VERSION 5.7 ;
  NOWIREEXTENSIONATPIN ON ;
  DIVIDERCHAR "/" ;
  BUSBITCHARS "[]" ;
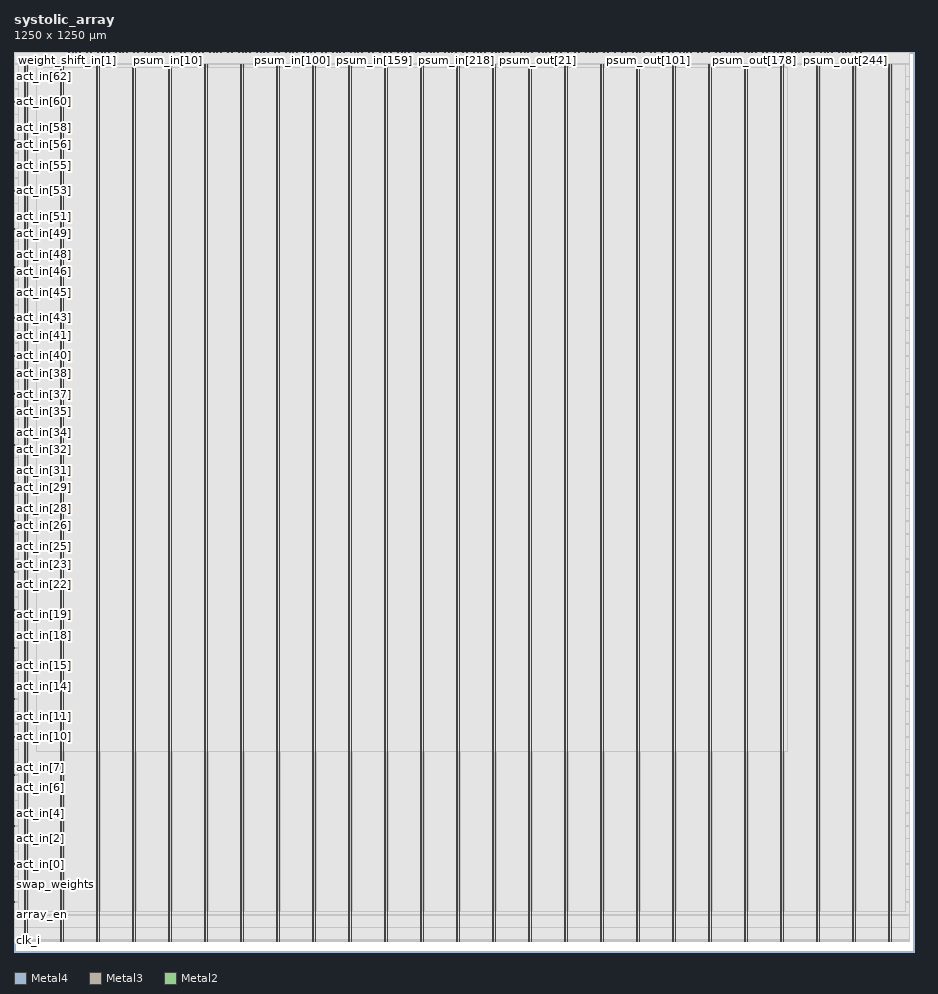
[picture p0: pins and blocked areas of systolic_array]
MACRO systolic_array
  CLASS BLOCK ;
  FOREIGN systolic_array ;
  ORIGIN 0.000 0.000 ;
  SIZE 1250.000 BY 1250.000 ;
  PIN VDD
    DIRECTION INOUT ;
    USE POWER ;
    PORT
      LAYER Metal4 ;
        RECT 15.260 14.900 16.260 1232.500 ;
    END
    PORT
      LAYER Metal4 ;
        RECT 65.260 14.900 66.260 1232.500 ;
    END
    PORT
      LAYER Metal4 ;
        RECT 115.260 14.900 116.260 1232.500 ;
    END
    PORT
      LAYER Metal4 ;
        RECT 165.260 14.900 166.260 1232.500 ;
    END
    PORT
      LAYER Metal4 ;
        RECT 215.260 14.900 216.260 1232.500 ;
    END
    PORT
      LAYER Metal4 ;
        RECT 265.260 14.900 266.260 1232.500 ;
    END
    PORT
      LAYER Metal4 ;
        RECT 315.260 14.900 316.260 1232.500 ;
    END
    PORT
      LAYER Metal4 ;
        RECT 365.260 14.900 366.260 1232.500 ;
    END
    PORT
      LAYER Metal4 ;
        RECT 415.260 14.900 416.260 1232.500 ;
    END
    PORT
      LAYER Metal4 ;
        RECT 465.260 14.900 466.260 1232.500 ;
    END
    PORT
      LAYER Metal4 ;
        RECT 515.260 14.900 516.260 1232.500 ;
    END
    PORT
      LAYER Metal4 ;
        RECT 565.260 14.900 566.260 1232.500 ;
    END
    PORT
      LAYER Metal4 ;
        RECT 615.260 14.900 616.260 1232.500 ;
    END
    PORT
      LAYER Metal4 ;
        RECT 665.260 14.900 666.260 1232.500 ;
    END
    PORT
      LAYER Metal4 ;
        RECT 715.260 14.900 716.260 1232.500 ;
    END
    PORT
      LAYER Metal4 ;
        RECT 765.260 14.900 766.260 1232.500 ;
    END
    PORT
      LAYER Metal4 ;
        RECT 815.260 14.900 816.260 1232.500 ;
    END
    PORT
      LAYER Metal4 ;
        RECT 865.260 14.900 866.260 1232.500 ;
    END
    PORT
      LAYER Metal4 ;
        RECT 915.260 14.900 916.260 1232.500 ;
    END
    PORT
      LAYER Metal4 ;
        RECT 965.260 14.900 966.260 1232.500 ;
    END
    PORT
      LAYER Metal4 ;
        RECT 1015.260 14.900 1016.260 1232.500 ;
    END
    PORT
      LAYER Metal4 ;
        RECT 1065.260 14.900 1066.260 1232.500 ;
    END
    PORT
      LAYER Metal4 ;
        RECT 1115.260 14.900 1116.260 1232.500 ;
    END
    PORT
      LAYER Metal4 ;
        RECT 1165.260 14.900 1166.260 1232.500 ;
    END
    PORT
      LAYER Metal4 ;
        RECT 1215.260 14.900 1216.260 1232.500 ;
    END
  END VDD
  PIN VSS
    DIRECTION INOUT ;
    USE GROUND ;
    PORT
      LAYER Metal4 ;
        RECT 18.260 14.900 19.260 1232.500 ;
    END
    PORT
      LAYER Metal4 ;
        RECT 68.260 14.900 69.260 1232.500 ;
    END
    PORT
      LAYER Metal4 ;
        RECT 118.260 14.900 119.260 1232.500 ;
    END
    PORT
      LAYER Metal4 ;
        RECT 168.260 14.900 169.260 1232.500 ;
    END
    PORT
      LAYER Metal4 ;
        RECT 218.260 14.900 219.260 1232.500 ;
    END
    PORT
      LAYER Metal4 ;
        RECT 268.260 14.900 269.260 1232.500 ;
    END
    PORT
      LAYER Metal4 ;
        RECT 318.260 14.900 319.260 1232.500 ;
    END
    PORT
      LAYER Metal4 ;
        RECT 368.260 14.900 369.260 1232.500 ;
    END
    PORT
      LAYER Metal4 ;
        RECT 418.260 14.900 419.260 1232.500 ;
    END
    PORT
      LAYER Metal4 ;
        RECT 468.260 14.900 469.260 1232.500 ;
    END
    PORT
      LAYER Metal4 ;
        RECT 518.260 14.900 519.260 1232.500 ;
    END
    PORT
      LAYER Metal4 ;
        RECT 568.260 14.900 569.260 1232.500 ;
    END
    PORT
      LAYER Metal4 ;
        RECT 618.260 14.900 619.260 1232.500 ;
    END
    PORT
      LAYER Metal4 ;
        RECT 668.260 14.900 669.260 1232.500 ;
    END
    PORT
      LAYER Metal4 ;
        RECT 718.260 14.900 719.260 1232.500 ;
    END
    PORT
      LAYER Metal4 ;
        RECT 768.260 14.900 769.260 1232.500 ;
    END
    PORT
      LAYER Metal4 ;
        RECT 818.260 14.900 819.260 1232.500 ;
    END
    PORT
      LAYER Metal4 ;
        RECT 868.260 14.900 869.260 1232.500 ;
    END
    PORT
      LAYER Metal4 ;
        RECT 918.260 14.900 919.260 1232.500 ;
    END
    PORT
      LAYER Metal4 ;
        RECT 968.260 14.900 969.260 1232.500 ;
    END
    PORT
      LAYER Metal4 ;
        RECT 1018.260 14.900 1019.260 1232.500 ;
    END
    PORT
      LAYER Metal4 ;
        RECT 1068.260 14.900 1069.260 1232.500 ;
    END
    PORT
      LAYER Metal4 ;
        RECT 1118.260 14.900 1119.260 1232.500 ;
    END
    PORT
      LAYER Metal4 ;
        RECT 1168.260 14.900 1169.260 1232.500 ;
    END
    PORT
      LAYER Metal4 ;
        RECT 1218.260 14.900 1219.260 1232.500 ;
    END
  END VSS
  PIN act_in[0]
    DIRECTION INPUT ;
    USE SIGNAL ;
    ANTENNAGATEAREA 0.180700 ;
    PORT
      LAYER Metal3 ;
        RECT 0.000 122.020 0.400 122.420 ;
    END
  END act_in[0]
  PIN act_in[10]
    DIRECTION INPUT ;
    USE SIGNAL ;
    ANTENNAGATEAREA 0.180700 ;
    PORT
      LAYER Metal3 ;
        RECT 0.000 298.420 0.400 298.820 ;
    END
  END act_in[10]
  PIN act_in[11]
    DIRECTION INPUT ;
    USE SIGNAL ;
    ANTENNAGATEAREA 0.180700 ;
    PORT
      LAYER Metal3 ;
        RECT 0.000 316.060 0.400 316.460 ;
    END
  END act_in[11]
  PIN act_in[12]
    DIRECTION INPUT ;
    USE SIGNAL ;
    ANTENNAGATEAREA 0.180700 ;
    PORT
      LAYER Metal3 ;
        RECT 0.000 333.700 0.400 334.100 ;
    END
  END act_in[12]
  PIN act_in[13]
    DIRECTION INPUT ;
    USE SIGNAL ;
    ANTENNAGATEAREA 0.180700 ;
    PORT
      LAYER Metal3 ;
        RECT 0.000 351.340 0.400 351.740 ;
    END
  END act_in[13]
  PIN act_in[14]
    DIRECTION INPUT ;
    USE SIGNAL ;
    ANTENNAGATEAREA 0.180700 ;
    PORT
      LAYER Metal3 ;
        RECT 0.000 368.980 0.400 369.380 ;
    END
  END act_in[14]
  PIN act_in[15]
    DIRECTION INPUT ;
    USE SIGNAL ;
    ANTENNAGATEAREA 0.180700 ;
    PORT
      LAYER Metal3 ;
        RECT 0.000 386.620 0.400 387.020 ;
    END
  END act_in[15]
  PIN act_in[16]
    DIRECTION INPUT ;
    USE SIGNAL ;
    ANTENNAGATEAREA 0.180700 ;
    PORT
      LAYER Metal3 ;
        RECT 0.000 404.260 0.400 404.660 ;
    END
  END act_in[16]
  PIN act_in[17]
    DIRECTION INPUT ;
    USE SIGNAL ;
    ANTENNAGATEAREA 0.180700 ;
    PORT
      LAYER Metal3 ;
        RECT 0.000 421.900 0.400 422.300 ;
    END
  END act_in[17]
  PIN act_in[18]
    DIRECTION INPUT ;
    USE SIGNAL ;
    ANTENNAGATEAREA 0.180700 ;
    PORT
      LAYER Metal3 ;
        RECT 0.000 439.540 0.400 439.940 ;
    END
  END act_in[18]
  PIN act_in[19]
    DIRECTION INPUT ;
    USE SIGNAL ;
    ANTENNAGATEAREA 0.180700 ;
    PORT
      LAYER Metal3 ;
        RECT 0.000 457.180 0.400 457.580 ;
    END
  END act_in[19]
  PIN act_in[1]
    DIRECTION INPUT ;
    USE SIGNAL ;
    ANTENNAGATEAREA 0.180700 ;
    PORT
      LAYER Metal3 ;
        RECT 0.000 139.660 0.400 140.060 ;
    END
  END act_in[1]
  PIN act_in[20]
    DIRECTION INPUT ;
    USE SIGNAL ;
    ANTENNAGATEAREA 0.180700 ;
    PORT
      LAYER Metal3 ;
        RECT 0.000 474.820 0.400 475.220 ;
    END
  END act_in[20]
  PIN act_in[21]
    DIRECTION INPUT ;
    USE SIGNAL ;
    ANTENNAGATEAREA 0.180700 ;
    PORT
      LAYER Metal3 ;
        RECT 0.000 492.460 0.400 492.860 ;
    END
  END act_in[21]
  PIN act_in[22]
    DIRECTION INPUT ;
    USE SIGNAL ;
    ANTENNAGATEAREA 0.180700 ;
    PORT
      LAYER Metal3 ;
        RECT 0.000 510.100 0.400 510.500 ;
    END
  END act_in[22]
  PIN act_in[23]
    DIRECTION INPUT ;
    USE SIGNAL ;
    ANTENNAGATEAREA 0.180700 ;
    PORT
      LAYER Metal3 ;
        RECT 0.000 527.740 0.400 528.140 ;
    END
  END act_in[23]
  PIN act_in[24]
    DIRECTION INPUT ;
    USE SIGNAL ;
    ANTENNAGATEAREA 0.180700 ;
    PORT
      LAYER Metal3 ;
        RECT 0.000 545.380 0.400 545.780 ;
    END
  END act_in[24]
  PIN act_in[25]
    DIRECTION INPUT ;
    USE SIGNAL ;
    ANTENNAGATEAREA 0.180700 ;
    PORT
      LAYER Metal3 ;
        RECT 0.000 563.020 0.400 563.420 ;
    END
  END act_in[25]
  PIN act_in[26]
    DIRECTION INPUT ;
    USE SIGNAL ;
    ANTENNAGATEAREA 0.180700 ;
    PORT
      LAYER Metal3 ;
        RECT 0.000 580.660 0.400 581.060 ;
    END
  END act_in[26]
  PIN act_in[27]
    DIRECTION INPUT ;
    USE SIGNAL ;
    ANTENNAGATEAREA 0.180700 ;
    PORT
      LAYER Metal3 ;
        RECT 0.000 598.300 0.400 598.700 ;
    END
  END act_in[27]
  PIN act_in[28]
    DIRECTION INPUT ;
    USE SIGNAL ;
    ANTENNAGATEAREA 0.180700 ;
    PORT
      LAYER Metal3 ;
        RECT 0.000 615.940 0.400 616.340 ;
    END
  END act_in[28]
  PIN act_in[29]
    DIRECTION INPUT ;
    USE SIGNAL ;
    ANTENNAGATEAREA 0.180700 ;
    PORT
      LAYER Metal3 ;
        RECT 0.000 633.580 0.400 633.980 ;
    END
  END act_in[29]
  PIN act_in[2]
    DIRECTION INPUT ;
    USE SIGNAL ;
    ANTENNAGATEAREA 0.180700 ;
    PORT
      LAYER Metal3 ;
        RECT 0.000 157.300 0.400 157.700 ;
    END
  END act_in[2]
  PIN act_in[30]
    DIRECTION INPUT ;
    USE SIGNAL ;
    ANTENNAGATEAREA 0.180700 ;
    PORT
      LAYER Metal3 ;
        RECT 0.000 651.220 0.400 651.620 ;
    END
  END act_in[30]
  PIN act_in[31]
    DIRECTION INPUT ;
    USE SIGNAL ;
    ANTENNAGATEAREA 0.180700 ;
    PORT
      LAYER Metal3 ;
        RECT 0.000 668.860 0.400 669.260 ;
    END
  END act_in[31]
  PIN act_in[32]
    DIRECTION INPUT ;
    USE SIGNAL ;
    ANTENNAGATEAREA 0.180700 ;
    PORT
      LAYER Metal3 ;
        RECT 0.000 686.500 0.400 686.900 ;
    END
  END act_in[32]
  PIN act_in[33]
    DIRECTION INPUT ;
    USE SIGNAL ;
    ANTENNAGATEAREA 0.180700 ;
    PORT
      LAYER Metal3 ;
        RECT 0.000 704.140 0.400 704.540 ;
    END
  END act_in[33]
  PIN act_in[34]
    DIRECTION INPUT ;
    USE SIGNAL ;
    ANTENNAGATEAREA 0.180700 ;
    PORT
      LAYER Metal3 ;
        RECT 0.000 721.780 0.400 722.180 ;
    END
  END act_in[34]
  PIN act_in[35]
    DIRECTION INPUT ;
    USE SIGNAL ;
    ANTENNAGATEAREA 0.180700 ;
    PORT
      LAYER Metal3 ;
        RECT 0.000 739.420 0.400 739.820 ;
    END
  END act_in[35]
  PIN act_in[36]
    DIRECTION INPUT ;
    USE SIGNAL ;
    ANTENNAGATEAREA 0.180700 ;
    PORT
      LAYER Metal3 ;
        RECT 0.000 757.060 0.400 757.460 ;
    END
  END act_in[36]
  PIN act_in[37]
    DIRECTION INPUT ;
    USE SIGNAL ;
    ANTENNAGATEAREA 0.180700 ;
    PORT
      LAYER Metal3 ;
        RECT 0.000 774.700 0.400 775.100 ;
    END
  END act_in[37]
  PIN act_in[38]
    DIRECTION INPUT ;
    USE SIGNAL ;
    ANTENNAGATEAREA 0.180700 ;
    PORT
      LAYER Metal3 ;
        RECT 0.000 792.340 0.400 792.740 ;
    END
  END act_in[38]
  PIN act_in[39]
    DIRECTION INPUT ;
    USE SIGNAL ;
    ANTENNAGATEAREA 0.180700 ;
    PORT
      LAYER Metal3 ;
        RECT 0.000 809.980 0.400 810.380 ;
    END
  END act_in[39]
  PIN act_in[3]
    DIRECTION INPUT ;
    USE SIGNAL ;
    ANTENNAGATEAREA 0.180700 ;
    PORT
      LAYER Metal3 ;
        RECT 0.000 174.940 0.400 175.340 ;
    END
  END act_in[3]
  PIN act_in[40]
    DIRECTION INPUT ;
    USE SIGNAL ;
    ANTENNAGATEAREA 0.180700 ;
    PORT
      LAYER Metal3 ;
        RECT 0.000 827.620 0.400 828.020 ;
    END
  END act_in[40]
  PIN act_in[41]
    DIRECTION INPUT ;
    USE SIGNAL ;
    ANTENNAGATEAREA 0.180700 ;
    PORT
      LAYER Metal3 ;
        RECT 0.000 845.260 0.400 845.660 ;
    END
  END act_in[41]
  PIN act_in[42]
    DIRECTION INPUT ;
    USE SIGNAL ;
    ANTENNAGATEAREA 0.180700 ;
    PORT
      LAYER Metal3 ;
        RECT 0.000 862.900 0.400 863.300 ;
    END
  END act_in[42]
  PIN act_in[43]
    DIRECTION INPUT ;
    USE SIGNAL ;
    ANTENNAGATEAREA 0.180700 ;
    PORT
      LAYER Metal3 ;
        RECT 0.000 880.540 0.400 880.940 ;
    END
  END act_in[43]
  PIN act_in[44]
    DIRECTION INPUT ;
    USE SIGNAL ;
    ANTENNAGATEAREA 0.180700 ;
    PORT
      LAYER Metal3 ;
        RECT 0.000 898.180 0.400 898.580 ;
    END
  END act_in[44]
  PIN act_in[45]
    DIRECTION INPUT ;
    USE SIGNAL ;
    ANTENNAGATEAREA 0.180700 ;
    PORT
      LAYER Metal3 ;
        RECT 0.000 915.820 0.400 916.220 ;
    END
  END act_in[45]
  PIN act_in[46]
    DIRECTION INPUT ;
    USE SIGNAL ;
    ANTENNAGATEAREA 0.180700 ;
    PORT
      LAYER Metal3 ;
        RECT 0.000 933.460 0.400 933.860 ;
    END
  END act_in[46]
  PIN act_in[47]
    DIRECTION INPUT ;
    USE SIGNAL ;
    ANTENNAGATEAREA 0.180700 ;
    PORT
      LAYER Metal3 ;
        RECT 0.000 951.100 0.400 951.500 ;
    END
  END act_in[47]
  PIN act_in[48]
    DIRECTION INPUT ;
    USE SIGNAL ;
    ANTENNAGATEAREA 0.180700 ;
    PORT
      LAYER Metal3 ;
        RECT 0.000 968.740 0.400 969.140 ;
    END
  END act_in[48]
  PIN act_in[49]
    DIRECTION INPUT ;
    USE SIGNAL ;
    ANTENNAGATEAREA 0.180700 ;
    PORT
      LAYER Metal3 ;
        RECT 0.000 986.380 0.400 986.780 ;
    END
  END act_in[49]
  PIN act_in[4]
    DIRECTION INPUT ;
    USE SIGNAL ;
    ANTENNAGATEAREA 0.180700 ;
    PORT
      LAYER Metal3 ;
        RECT 0.000 192.580 0.400 192.980 ;
    END
  END act_in[4]
  PIN act_in[50]
    DIRECTION INPUT ;
    USE SIGNAL ;
    ANTENNAGATEAREA 0.180700 ;
    PORT
      LAYER Metal3 ;
        RECT 0.000 1004.020 0.400 1004.420 ;
    END
  END act_in[50]
  PIN act_in[51]
    DIRECTION INPUT ;
    USE SIGNAL ;
    ANTENNAGATEAREA 0.180700 ;
    PORT
      LAYER Metal3 ;
        RECT 0.000 1021.660 0.400 1022.060 ;
    END
  END act_in[51]
  PIN act_in[52]
    DIRECTION INPUT ;
    USE SIGNAL ;
    ANTENNAGATEAREA 0.180700 ;
    PORT
      LAYER Metal3 ;
        RECT 0.000 1039.300 0.400 1039.700 ;
    END
  END act_in[52]
  PIN act_in[53]
    DIRECTION INPUT ;
    USE SIGNAL ;
    ANTENNAGATEAREA 0.180700 ;
    PORT
      LAYER Metal3 ;
        RECT 0.000 1056.940 0.400 1057.340 ;
    END
  END act_in[53]
  PIN act_in[54]
    DIRECTION INPUT ;
    USE SIGNAL ;
    ANTENNAGATEAREA 0.180700 ;
    PORT
      LAYER Metal3 ;
        RECT 0.000 1074.580 0.400 1074.980 ;
    END
  END act_in[54]
  PIN act_in[55]
    DIRECTION INPUT ;
    USE SIGNAL ;
    ANTENNAGATEAREA 0.180700 ;
    PORT
      LAYER Metal3 ;
        RECT 0.000 1092.220 0.400 1092.620 ;
    END
  END act_in[55]
  PIN act_in[56]
    DIRECTION INPUT ;
    USE SIGNAL ;
    ANTENNAGATEAREA 0.180700 ;
    PORT
      LAYER Metal3 ;
        RECT 0.000 1109.860 0.400 1110.260 ;
    END
  END act_in[56]
  PIN act_in[57]
    DIRECTION INPUT ;
    USE SIGNAL ;
    ANTENNAGATEAREA 0.180700 ;
    PORT
      LAYER Metal3 ;
        RECT 0.000 1127.500 0.400 1127.900 ;
    END
  END act_in[57]
  PIN act_in[58]
    DIRECTION INPUT ;
    USE SIGNAL ;
    ANTENNAGATEAREA 0.180700 ;
    PORT
      LAYER Metal3 ;
        RECT 0.000 1145.140 0.400 1145.540 ;
    END
  END act_in[58]
  PIN act_in[59]
    DIRECTION INPUT ;
    USE SIGNAL ;
    ANTENNAGATEAREA 0.180700 ;
    PORT
      LAYER Metal3 ;
        RECT 0.000 1162.780 0.400 1163.180 ;
    END
  END act_in[59]
  PIN act_in[5]
    DIRECTION INPUT ;
    USE SIGNAL ;
    ANTENNAGATEAREA 0.180700 ;
    PORT
      LAYER Metal3 ;
        RECT 0.000 210.220 0.400 210.620 ;
    END
  END act_in[5]
  PIN act_in[60]
    DIRECTION INPUT ;
    USE SIGNAL ;
    ANTENNAGATEAREA 0.180700 ;
    PORT
      LAYER Metal3 ;
        RECT 0.000 1180.420 0.400 1180.820 ;
    END
  END act_in[60]
  PIN act_in[61]
    DIRECTION INPUT ;
    USE SIGNAL ;
    ANTENNAGATEAREA 0.180700 ;
    PORT
      LAYER Metal3 ;
        RECT 0.000 1198.060 0.400 1198.460 ;
    END
  END act_in[61]
  PIN act_in[62]
    DIRECTION INPUT ;
    USE SIGNAL ;
    ANTENNAGATEAREA 0.180700 ;
    PORT
      LAYER Metal3 ;
        RECT 0.000 1215.700 0.400 1216.100 ;
    END
  END act_in[62]
  PIN act_in[63]
    DIRECTION INPUT ;
    USE SIGNAL ;
    ANTENNAGATEAREA 0.180700 ;
    PORT
      LAYER Metal3 ;
        RECT 0.000 1233.340 0.400 1233.740 ;
    END
  END act_in[63]
  PIN act_in[6]
    DIRECTION INPUT ;
    USE SIGNAL ;
    ANTENNAGATEAREA 0.180700 ;
    PORT
      LAYER Metal3 ;
        RECT 0.000 227.860 0.400 228.260 ;
    END
  END act_in[6]
  PIN act_in[7]
    DIRECTION INPUT ;
    USE SIGNAL ;
    ANTENNAGATEAREA 0.180700 ;
    PORT
      LAYER Metal3 ;
        RECT 0.000 245.500 0.400 245.900 ;
    END
  END act_in[7]
  PIN act_in[8]
    DIRECTION INPUT ;
    USE SIGNAL ;
    ANTENNAGATEAREA 0.180700 ;
    PORT
      LAYER Metal3 ;
        RECT 0.000 263.140 0.400 263.540 ;
    END
  END act_in[8]
  PIN act_in[9]
    DIRECTION INPUT ;
    USE SIGNAL ;
    ANTENNAGATEAREA 0.180700 ;
    PORT
      LAYER Metal3 ;
        RECT 0.000 280.780 0.400 281.180 ;
    END
  END act_in[9]
  PIN array_en
    DIRECTION INPUT ;
    USE SIGNAL ;
    ANTENNAGATEAREA 0.180700 ;
    PORT
      LAYER Metal3 ;
        RECT 0.000 51.460 0.400 51.860 ;
    END
  END array_en
  PIN clk_i
    DIRECTION INPUT ;
    USE SIGNAL ;
    ANTENNAGATEAREA 0.725400 ;
    PORT
      LAYER Metal3 ;
        RECT 0.000 16.180 0.400 16.580 ;
    END
  END clk_i
  PIN psum_in[0]
    DIRECTION INPUT ;
    USE SIGNAL ;
    ANTENNAGATEAREA 0.180700 ;
    PORT
      LAYER Metal2 ;
        RECT 195.160 1249.600 195.560 1250.000 ;
    END
  END psum_in[0]
  PIN psum_in[100]
    DIRECTION INPUT ;
    USE SIGNAL ;
    ANTENNAGATEAREA 0.180700 ;
    PORT
      LAYER Metal2 ;
        RECT 387.160 1249.600 387.560 1250.000 ;
    END
  END psum_in[100]
  PIN psum_in[101]
    DIRECTION INPUT ;
    USE SIGNAL ;
    ANTENNAGATEAREA 0.180700 ;
    PORT
      LAYER Metal2 ;
        RECT 389.080 1249.600 389.480 1250.000 ;
    END
  END psum_in[101]
  PIN psum_in[102]
    DIRECTION INPUT ;
    USE SIGNAL ;
    ANTENNAGATEAREA 0.180700 ;
    PORT
      LAYER Metal2 ;
        RECT 391.000 1249.600 391.400 1250.000 ;
    END
  END psum_in[102]
  PIN psum_in[103]
    DIRECTION INPUT ;
    USE SIGNAL ;
    ANTENNAGATEAREA 0.180700 ;
    PORT
      LAYER Metal2 ;
        RECT 392.920 1249.600 393.320 1250.000 ;
    END
  END psum_in[103]
  PIN psum_in[104]
    DIRECTION INPUT ;
    USE SIGNAL ;
    ANTENNAGATEAREA 0.180700 ;
    PORT
      LAYER Metal2 ;
        RECT 394.840 1249.600 395.240 1250.000 ;
    END
  END psum_in[104]
  PIN psum_in[105]
    DIRECTION INPUT ;
    USE SIGNAL ;
    ANTENNAGATEAREA 0.180700 ;
    PORT
      LAYER Metal2 ;
        RECT 396.760 1249.600 397.160 1250.000 ;
    END
  END psum_in[105]
  PIN psum_in[106]
    DIRECTION INPUT ;
    USE SIGNAL ;
    ANTENNAGATEAREA 0.180700 ;
    PORT
      LAYER Metal2 ;
        RECT 398.680 1249.600 399.080 1250.000 ;
    END
  END psum_in[106]
  PIN psum_in[107]
    DIRECTION INPUT ;
    USE SIGNAL ;
    ANTENNAGATEAREA 0.180700 ;
    PORT
      LAYER Metal2 ;
        RECT 400.600 1249.600 401.000 1250.000 ;
    END
  END psum_in[107]
  PIN psum_in[108]
    DIRECTION INPUT ;
    USE SIGNAL ;
    ANTENNAGATEAREA 0.180700 ;
    PORT
      LAYER Metal2 ;
        RECT 402.520 1249.600 402.920 1250.000 ;
    END
  END psum_in[108]
  PIN psum_in[109]
    DIRECTION INPUT ;
    USE SIGNAL ;
    ANTENNAGATEAREA 0.180700 ;
    PORT
      LAYER Metal2 ;
        RECT 404.440 1249.600 404.840 1250.000 ;
    END
  END psum_in[109]
  PIN psum_in[10]
    DIRECTION INPUT ;
    USE SIGNAL ;
    ANTENNAGATEAREA 0.180700 ;
    PORT
      LAYER Metal2 ;
        RECT 214.360 1249.600 214.760 1250.000 ;
    END
  END psum_in[10]
  PIN psum_in[110]
    DIRECTION INPUT ;
    USE SIGNAL ;
    ANTENNAGATEAREA 0.180700 ;
    PORT
      LAYER Metal2 ;
        RECT 406.360 1249.600 406.760 1250.000 ;
    END
  END psum_in[110]
  PIN psum_in[111]
    DIRECTION INPUT ;
    USE SIGNAL ;
    ANTENNAGATEAREA 0.180700 ;
    PORT
      LAYER Metal2 ;
        RECT 408.280 1249.600 408.680 1250.000 ;
    END
  END psum_in[111]
  PIN psum_in[112]
    DIRECTION INPUT ;
    USE SIGNAL ;
    ANTENNAGATEAREA 0.180700 ;
    PORT
      LAYER Metal2 ;
        RECT 410.200 1249.600 410.600 1250.000 ;
    END
  END psum_in[112]
  PIN psum_in[113]
    DIRECTION INPUT ;
    USE SIGNAL ;
    ANTENNAGATEAREA 0.180700 ;
    PORT
      LAYER Metal2 ;
        RECT 412.120 1249.600 412.520 1250.000 ;
    END
  END psum_in[113]
  PIN psum_in[114]
    DIRECTION INPUT ;
    USE SIGNAL ;
    ANTENNAGATEAREA 0.180700 ;
    PORT
      LAYER Metal2 ;
        RECT 414.040 1249.600 414.440 1250.000 ;
    END
  END psum_in[114]
  PIN psum_in[115]
    DIRECTION INPUT ;
    USE SIGNAL ;
    ANTENNAGATEAREA 0.180700 ;
    PORT
      LAYER Metal2 ;
        RECT 415.960 1249.600 416.360 1250.000 ;
    END
  END psum_in[115]
  PIN psum_in[116]
    DIRECTION INPUT ;
    USE SIGNAL ;
    ANTENNAGATEAREA 0.180700 ;
    PORT
      LAYER Metal2 ;
        RECT 417.880 1249.600 418.280 1250.000 ;
    END
  END psum_in[116]
  PIN psum_in[117]
    DIRECTION INPUT ;
    USE SIGNAL ;
    ANTENNAGATEAREA 0.180700 ;
    PORT
      LAYER Metal2 ;
        RECT 419.800 1249.600 420.200 1250.000 ;
    END
  END psum_in[117]
  PIN psum_in[118]
    DIRECTION INPUT ;
    USE SIGNAL ;
    ANTENNAGATEAREA 0.180700 ;
    PORT
      LAYER Metal2 ;
        RECT 421.720 1249.600 422.120 1250.000 ;
    END
  END psum_in[118]
  PIN psum_in[119]
    DIRECTION INPUT ;
    USE SIGNAL ;
    ANTENNAGATEAREA 0.180700 ;
    PORT
      LAYER Metal2 ;
        RECT 423.640 1249.600 424.040 1250.000 ;
    END
  END psum_in[119]
  PIN psum_in[11]
    DIRECTION INPUT ;
    USE SIGNAL ;
    ANTENNAGATEAREA 0.180700 ;
    PORT
      LAYER Metal2 ;
        RECT 216.280 1249.600 216.680 1250.000 ;
    END
  END psum_in[11]
  PIN psum_in[120]
    DIRECTION INPUT ;
    USE SIGNAL ;
    ANTENNAGATEAREA 0.180700 ;
    PORT
      LAYER Metal2 ;
        RECT 425.560 1249.600 425.960 1250.000 ;
    END
  END psum_in[120]
  PIN psum_in[121]
    DIRECTION INPUT ;
    USE SIGNAL ;
    ANTENNAGATEAREA 0.180700 ;
    PORT
      LAYER Metal2 ;
        RECT 427.480 1249.600 427.880 1250.000 ;
    END
  END psum_in[121]
  PIN psum_in[122]
    DIRECTION INPUT ;
    USE SIGNAL ;
    ANTENNAGATEAREA 0.180700 ;
    PORT
      LAYER Metal2 ;
        RECT 429.400 1249.600 429.800 1250.000 ;
    END
  END psum_in[122]
  PIN psum_in[123]
    DIRECTION INPUT ;
    USE SIGNAL ;
    ANTENNAGATEAREA 0.180700 ;
    PORT
      LAYER Metal2 ;
        RECT 431.320 1249.600 431.720 1250.000 ;
    END
  END psum_in[123]
  PIN psum_in[124]
    DIRECTION INPUT ;
    USE SIGNAL ;
    ANTENNAGATEAREA 0.180700 ;
    PORT
      LAYER Metal2 ;
        RECT 433.240 1249.600 433.640 1250.000 ;
    END
  END psum_in[124]
  PIN psum_in[125]
    DIRECTION INPUT ;
    USE SIGNAL ;
    ANTENNAGATEAREA 0.180700 ;
    PORT
      LAYER Metal2 ;
        RECT 435.160 1249.600 435.560 1250.000 ;
    END
  END psum_in[125]
  PIN psum_in[126]
    DIRECTION INPUT ;
    USE SIGNAL ;
    ANTENNAGATEAREA 0.180700 ;
    PORT
      LAYER Metal2 ;
        RECT 437.080 1249.600 437.480 1250.000 ;
    END
  END psum_in[126]
  PIN psum_in[127]
    DIRECTION INPUT ;
    USE SIGNAL ;
    ANTENNAGATEAREA 0.180700 ;
    PORT
      LAYER Metal2 ;
        RECT 439.000 1249.600 439.400 1250.000 ;
    END
  END psum_in[127]
  PIN psum_in[128]
    DIRECTION INPUT ;
    USE SIGNAL ;
    ANTENNAGATEAREA 0.180700 ;
    PORT
      LAYER Metal2 ;
        RECT 440.920 1249.600 441.320 1250.000 ;
    END
  END psum_in[128]
  PIN psum_in[129]
    DIRECTION INPUT ;
    USE SIGNAL ;
    ANTENNAGATEAREA 0.180700 ;
    PORT
      LAYER Metal2 ;
        RECT 442.840 1249.600 443.240 1250.000 ;
    END
  END psum_in[129]
  PIN psum_in[12]
    DIRECTION INPUT ;
    USE SIGNAL ;
    ANTENNAGATEAREA 0.180700 ;
    PORT
      LAYER Metal2 ;
        RECT 218.200 1249.600 218.600 1250.000 ;
    END
  END psum_in[12]
  PIN psum_in[130]
    DIRECTION INPUT ;
    USE SIGNAL ;
    ANTENNAGATEAREA 0.180700 ;
    PORT
      LAYER Metal2 ;
        RECT 444.760 1249.600 445.160 1250.000 ;
    END
  END psum_in[130]
  PIN psum_in[131]
    DIRECTION INPUT ;
    USE SIGNAL ;
    ANTENNAGATEAREA 0.180700 ;
    PORT
      LAYER Metal2 ;
        RECT 446.680 1249.600 447.080 1250.000 ;
    END
  END psum_in[131]
  PIN psum_in[132]
    DIRECTION INPUT ;
    USE SIGNAL ;
    ANTENNAGATEAREA 0.180700 ;
    PORT
      LAYER Metal2 ;
        RECT 448.600 1249.600 449.000 1250.000 ;
    END
  END psum_in[132]
  PIN psum_in[133]
    DIRECTION INPUT ;
    USE SIGNAL ;
    ANTENNAGATEAREA 0.180700 ;
    PORT
      LAYER Metal2 ;
        RECT 450.520 1249.600 450.920 1250.000 ;
    END
  END psum_in[133]
  PIN psum_in[134]
    DIRECTION INPUT ;
    USE SIGNAL ;
    ANTENNAGATEAREA 0.180700 ;
    PORT
      LAYER Metal2 ;
        RECT 452.440 1249.600 452.840 1250.000 ;
    END
  END psum_in[134]
  PIN psum_in[135]
    DIRECTION INPUT ;
    USE SIGNAL ;
    ANTENNAGATEAREA 0.180700 ;
    PORT
      LAYER Metal2 ;
        RECT 454.360 1249.600 454.760 1250.000 ;
    END
  END psum_in[135]
  PIN psum_in[136]
    DIRECTION INPUT ;
    USE SIGNAL ;
    ANTENNAGATEAREA 0.180700 ;
    PORT
      LAYER Metal2 ;
        RECT 456.280 1249.600 456.680 1250.000 ;
    END
  END psum_in[136]
  PIN psum_in[137]
    DIRECTION INPUT ;
    USE SIGNAL ;
    ANTENNAGATEAREA 0.180700 ;
    PORT
      LAYER Metal2 ;
        RECT 458.200 1249.600 458.600 1250.000 ;
    END
  END psum_in[137]
  PIN psum_in[138]
    DIRECTION INPUT ;
    USE SIGNAL ;
    ANTENNAGATEAREA 0.180700 ;
    PORT
      LAYER Metal2 ;
        RECT 460.120 1249.600 460.520 1250.000 ;
    END
  END psum_in[138]
  PIN psum_in[139]
    DIRECTION INPUT ;
    USE SIGNAL ;
    ANTENNAGATEAREA 0.180700 ;
    PORT
      LAYER Metal2 ;
        RECT 462.040 1249.600 462.440 1250.000 ;
    END
  END psum_in[139]
  PIN psum_in[13]
    DIRECTION INPUT ;
    USE SIGNAL ;
    ANTENNAGATEAREA 0.180700 ;
    PORT
      LAYER Metal2 ;
        RECT 220.120 1249.600 220.520 1250.000 ;
    END
  END psum_in[13]
  PIN psum_in[140]
    DIRECTION INPUT ;
    USE SIGNAL ;
    ANTENNAGATEAREA 0.180700 ;
    PORT
      LAYER Metal2 ;
        RECT 463.960 1249.600 464.360 1250.000 ;
    END
  END psum_in[140]
  PIN psum_in[141]
    DIRECTION INPUT ;
    USE SIGNAL ;
    ANTENNAGATEAREA 0.180700 ;
    PORT
      LAYER Metal2 ;
        RECT 465.880 1249.600 466.280 1250.000 ;
    END
  END psum_in[141]
  PIN psum_in[142]
    DIRECTION INPUT ;
    USE SIGNAL ;
    ANTENNAGATEAREA 0.180700 ;
    PORT
      LAYER Metal2 ;
        RECT 467.800 1249.600 468.200 1250.000 ;
    END
  END psum_in[142]
  PIN psum_in[143]
    DIRECTION INPUT ;
    USE SIGNAL ;
    ANTENNAGATEAREA 0.180700 ;
    PORT
      LAYER Metal2 ;
        RECT 469.720 1249.600 470.120 1250.000 ;
    END
  END psum_in[143]
  PIN psum_in[144]
    DIRECTION INPUT ;
    USE SIGNAL ;
    ANTENNAGATEAREA 0.180700 ;
    PORT
      LAYER Metal2 ;
        RECT 471.640 1249.600 472.040 1250.000 ;
    END
  END psum_in[144]
  PIN psum_in[145]
    DIRECTION INPUT ;
    USE SIGNAL ;
    ANTENNAGATEAREA 0.180700 ;
    PORT
      LAYER Metal2 ;
        RECT 473.560 1249.600 473.960 1250.000 ;
    END
  END psum_in[145]
  PIN psum_in[146]
    DIRECTION INPUT ;
    USE SIGNAL ;
    ANTENNAGATEAREA 0.180700 ;
    PORT
      LAYER Metal2 ;
        RECT 475.480 1249.600 475.880 1250.000 ;
    END
  END psum_in[146]
  PIN psum_in[147]
    DIRECTION INPUT ;
    USE SIGNAL ;
    ANTENNAGATEAREA 0.180700 ;
    PORT
      LAYER Metal2 ;
        RECT 477.400 1249.600 477.800 1250.000 ;
    END
  END psum_in[147]
  PIN psum_in[148]
    DIRECTION INPUT ;
    USE SIGNAL ;
    ANTENNAGATEAREA 0.180700 ;
    PORT
      LAYER Metal2 ;
        RECT 479.320 1249.600 479.720 1250.000 ;
    END
  END psum_in[148]
  PIN psum_in[149]
    DIRECTION INPUT ;
    USE SIGNAL ;
    ANTENNAGATEAREA 0.180700 ;
    PORT
      LAYER Metal2 ;
        RECT 481.240 1249.600 481.640 1250.000 ;
    END
  END psum_in[149]
  PIN psum_in[14]
    DIRECTION INPUT ;
    USE SIGNAL ;
    ANTENNAGATEAREA 0.180700 ;
    PORT
      LAYER Metal2 ;
        RECT 222.040 1249.600 222.440 1250.000 ;
    END
  END psum_in[14]
  PIN psum_in[150]
    DIRECTION INPUT ;
    USE SIGNAL ;
    ANTENNAGATEAREA 0.180700 ;
    PORT
      LAYER Metal2 ;
        RECT 483.160 1249.600 483.560 1250.000 ;
    END
  END psum_in[150]
  PIN psum_in[151]
    DIRECTION INPUT ;
    USE SIGNAL ;
    ANTENNAGATEAREA 0.180700 ;
    PORT
      LAYER Metal2 ;
        RECT 485.080 1249.600 485.480 1250.000 ;
    END
  END psum_in[151]
  PIN psum_in[152]
    DIRECTION INPUT ;
    USE SIGNAL ;
    ANTENNAGATEAREA 0.180700 ;
    PORT
      LAYER Metal2 ;
        RECT 487.000 1249.600 487.400 1250.000 ;
    END
  END psum_in[152]
  PIN psum_in[153]
    DIRECTION INPUT ;
    USE SIGNAL ;
    ANTENNAGATEAREA 0.180700 ;
    PORT
      LAYER Metal2 ;
        RECT 488.920 1249.600 489.320 1250.000 ;
    END
  END psum_in[153]
  PIN psum_in[154]
    DIRECTION INPUT ;
    USE SIGNAL ;
    ANTENNAGATEAREA 0.180700 ;
    PORT
      LAYER Metal2 ;
        RECT 490.840 1249.600 491.240 1250.000 ;
    END
  END psum_in[154]
  PIN psum_in[155]
    DIRECTION INPUT ;
    USE SIGNAL ;
    ANTENNAGATEAREA 0.180700 ;
    PORT
      LAYER Metal2 ;
        RECT 492.760 1249.600 493.160 1250.000 ;
    END
  END psum_in[155]
  PIN psum_in[156]
    DIRECTION INPUT ;
    USE SIGNAL ;
    ANTENNAGATEAREA 0.180700 ;
    PORT
      LAYER Metal2 ;
        RECT 494.680 1249.600 495.080 1250.000 ;
    END
  END psum_in[156]
  PIN psum_in[157]
    DIRECTION INPUT ;
    USE SIGNAL ;
    ANTENNAGATEAREA 0.180700 ;
    PORT
      LAYER Metal2 ;
        RECT 496.600 1249.600 497.000 1250.000 ;
    END
  END psum_in[157]
  PIN psum_in[158]
    DIRECTION INPUT ;
    USE SIGNAL ;
    ANTENNAGATEAREA 0.180700 ;
    PORT
      LAYER Metal2 ;
        RECT 498.520 1249.600 498.920 1250.000 ;
    END
  END psum_in[158]
  PIN psum_in[159]
    DIRECTION INPUT ;
    USE SIGNAL ;
    ANTENNAGATEAREA 0.180700 ;
    PORT
      LAYER Metal2 ;
        RECT 500.440 1249.600 500.840 1250.000 ;
    END
  END psum_in[159]
  PIN psum_in[15]
    DIRECTION INPUT ;
    USE SIGNAL ;
    ANTENNAGATEAREA 0.180700 ;
    PORT
      LAYER Metal2 ;
        RECT 223.960 1249.600 224.360 1250.000 ;
    END
  END psum_in[15]
  PIN psum_in[160]
    DIRECTION INPUT ;
    USE SIGNAL ;
    ANTENNAGATEAREA 0.180700 ;
    PORT
      LAYER Metal2 ;
        RECT 502.360 1249.600 502.760 1250.000 ;
    END
  END psum_in[160]
  PIN psum_in[161]
    DIRECTION INPUT ;
    USE SIGNAL ;
    ANTENNAGATEAREA 0.180700 ;
    PORT
      LAYER Metal2 ;
        RECT 504.280 1249.600 504.680 1250.000 ;
    END
  END psum_in[161]
  PIN psum_in[162]
    DIRECTION INPUT ;
    USE SIGNAL ;
    ANTENNAGATEAREA 0.180700 ;
    PORT
      LAYER Metal2 ;
        RECT 506.200 1249.600 506.600 1250.000 ;
    END
  END psum_in[162]
  PIN psum_in[163]
    DIRECTION INPUT ;
    USE SIGNAL ;
    ANTENNAGATEAREA 0.180700 ;
    PORT
      LAYER Metal2 ;
        RECT 508.120 1249.600 508.520 1250.000 ;
    END
  END psum_in[163]
  PIN psum_in[164]
    DIRECTION INPUT ;
    USE SIGNAL ;
    ANTENNAGATEAREA 0.180700 ;
    PORT
      LAYER Metal2 ;
        RECT 510.040 1249.600 510.440 1250.000 ;
    END
  END psum_in[164]
  PIN psum_in[165]
    DIRECTION INPUT ;
    USE SIGNAL ;
    ANTENNAGATEAREA 0.180700 ;
    PORT
      LAYER Metal2 ;
        RECT 511.960 1249.600 512.360 1250.000 ;
    END
  END psum_in[165]
  PIN psum_in[166]
    DIRECTION INPUT ;
    USE SIGNAL ;
    ANTENNAGATEAREA 0.180700 ;
    PORT
      LAYER Metal2 ;
        RECT 513.880 1249.600 514.280 1250.000 ;
    END
  END psum_in[166]
  PIN psum_in[167]
    DIRECTION INPUT ;
    USE SIGNAL ;
    ANTENNAGATEAREA 0.180700 ;
    PORT
      LAYER Metal2 ;
        RECT 515.800 1249.600 516.200 1250.000 ;
    END
  END psum_in[167]
  PIN psum_in[168]
    DIRECTION INPUT ;
    USE SIGNAL ;
    ANTENNAGATEAREA 0.180700 ;
    PORT
      LAYER Metal2 ;
        RECT 517.720 1249.600 518.120 1250.000 ;
    END
  END psum_in[168]
  PIN psum_in[169]
    DIRECTION INPUT ;
    USE SIGNAL ;
    ANTENNAGATEAREA 0.180700 ;
    PORT
      LAYER Metal2 ;
        RECT 519.640 1249.600 520.040 1250.000 ;
    END
  END psum_in[169]
  PIN psum_in[16]
    DIRECTION INPUT ;
    USE SIGNAL ;
    ANTENNAGATEAREA 0.180700 ;
    PORT
      LAYER Metal2 ;
        RECT 225.880 1249.600 226.280 1250.000 ;
    END
  END psum_in[16]
  PIN psum_in[170]
    DIRECTION INPUT ;
    USE SIGNAL ;
    ANTENNAGATEAREA 0.180700 ;
    PORT
      LAYER Metal2 ;
        RECT 521.560 1249.600 521.960 1250.000 ;
    END
  END psum_in[170]
  PIN psum_in[171]
    DIRECTION INPUT ;
    USE SIGNAL ;
    ANTENNAGATEAREA 0.180700 ;
    PORT
      LAYER Metal2 ;
        RECT 523.480 1249.600 523.880 1250.000 ;
    END
  END psum_in[171]
  PIN psum_in[172]
    DIRECTION INPUT ;
    USE SIGNAL ;
    ANTENNAGATEAREA 0.180700 ;
    PORT
      LAYER Metal2 ;
        RECT 525.400 1249.600 525.800 1250.000 ;
    END
  END psum_in[172]
  PIN psum_in[173]
    DIRECTION INPUT ;
    USE SIGNAL ;
    ANTENNAGATEAREA 0.180700 ;
    PORT
      LAYER Metal2 ;
        RECT 527.320 1249.600 527.720 1250.000 ;
    END
  END psum_in[173]
  PIN psum_in[174]
    DIRECTION INPUT ;
    USE SIGNAL ;
    ANTENNAGATEAREA 0.180700 ;
    PORT
      LAYER Metal2 ;
        RECT 529.240 1249.600 529.640 1250.000 ;
    END
  END psum_in[174]
  PIN psum_in[175]
    DIRECTION INPUT ;
    USE SIGNAL ;
    ANTENNAGATEAREA 0.180700 ;
    PORT
      LAYER Metal2 ;
        RECT 531.160 1249.600 531.560 1250.000 ;
    END
  END psum_in[175]
  PIN psum_in[176]
    DIRECTION INPUT ;
    USE SIGNAL ;
    ANTENNAGATEAREA 0.180700 ;
    PORT
      LAYER Metal2 ;
        RECT 533.080 1249.600 533.480 1250.000 ;
    END
  END psum_in[176]
  PIN psum_in[177]
    DIRECTION INPUT ;
    USE SIGNAL ;
    ANTENNAGATEAREA 0.180700 ;
    PORT
      LAYER Metal2 ;
        RECT 535.000 1249.600 535.400 1250.000 ;
    END
  END psum_in[177]
  PIN psum_in[178]
    DIRECTION INPUT ;
    USE SIGNAL ;
    ANTENNAGATEAREA 0.180700 ;
    PORT
      LAYER Metal2 ;
        RECT 536.920 1249.600 537.320 1250.000 ;
    END
  END psum_in[178]
  PIN psum_in[179]
    DIRECTION INPUT ;
    USE SIGNAL ;
    ANTENNAGATEAREA 0.180700 ;
    PORT
      LAYER Metal2 ;
        RECT 538.840 1249.600 539.240 1250.000 ;
    END
  END psum_in[179]
  PIN psum_in[17]
    DIRECTION INPUT ;
    USE SIGNAL ;
    ANTENNAGATEAREA 0.180700 ;
    PORT
      LAYER Metal2 ;
        RECT 227.800 1249.600 228.200 1250.000 ;
    END
  END psum_in[17]
  PIN psum_in[180]
    DIRECTION INPUT ;
    USE SIGNAL ;
    ANTENNAGATEAREA 0.180700 ;
    PORT
      LAYER Metal2 ;
        RECT 540.760 1249.600 541.160 1250.000 ;
    END
  END psum_in[180]
  PIN psum_in[181]
    DIRECTION INPUT ;
    USE SIGNAL ;
    ANTENNAGATEAREA 0.180700 ;
    PORT
      LAYER Metal2 ;
        RECT 542.680 1249.600 543.080 1250.000 ;
    END
  END psum_in[181]
  PIN psum_in[182]
    DIRECTION INPUT ;
    USE SIGNAL ;
    ANTENNAGATEAREA 0.180700 ;
    PORT
      LAYER Metal2 ;
        RECT 544.600 1249.600 545.000 1250.000 ;
    END
  END psum_in[182]
  PIN psum_in[183]
    DIRECTION INPUT ;
    USE SIGNAL ;
    ANTENNAGATEAREA 0.180700 ;
    PORT
      LAYER Metal2 ;
        RECT 546.520 1249.600 546.920 1250.000 ;
    END
  END psum_in[183]
  PIN psum_in[184]
    DIRECTION INPUT ;
    USE SIGNAL ;
    ANTENNAGATEAREA 0.180700 ;
    PORT
      LAYER Metal2 ;
        RECT 548.440 1249.600 548.840 1250.000 ;
    END
  END psum_in[184]
  PIN psum_in[185]
    DIRECTION INPUT ;
    USE SIGNAL ;
    ANTENNAGATEAREA 0.180700 ;
    PORT
      LAYER Metal2 ;
        RECT 550.360 1249.600 550.760 1250.000 ;
    END
  END psum_in[185]
  PIN psum_in[186]
    DIRECTION INPUT ;
    USE SIGNAL ;
    ANTENNAGATEAREA 0.180700 ;
    PORT
      LAYER Metal2 ;
        RECT 552.280 1249.600 552.680 1250.000 ;
    END
  END psum_in[186]
  PIN psum_in[187]
    DIRECTION INPUT ;
    USE SIGNAL ;
    ANTENNAGATEAREA 0.180700 ;
    PORT
      LAYER Metal2 ;
        RECT 554.200 1249.600 554.600 1250.000 ;
    END
  END psum_in[187]
  PIN psum_in[188]
    DIRECTION INPUT ;
    USE SIGNAL ;
    ANTENNAGATEAREA 0.180700 ;
    PORT
      LAYER Metal2 ;
        RECT 556.120 1249.600 556.520 1250.000 ;
    END
  END psum_in[188]
  PIN psum_in[189]
    DIRECTION INPUT ;
    USE SIGNAL ;
    ANTENNAGATEAREA 0.180700 ;
    PORT
      LAYER Metal2 ;
        RECT 558.040 1249.600 558.440 1250.000 ;
    END
  END psum_in[189]
  PIN psum_in[18]
    DIRECTION INPUT ;
    USE SIGNAL ;
    ANTENNAGATEAREA 0.180700 ;
    PORT
      LAYER Metal2 ;
        RECT 229.720 1249.600 230.120 1250.000 ;
    END
  END psum_in[18]
  PIN psum_in[190]
    DIRECTION INPUT ;
    USE SIGNAL ;
    ANTENNAGATEAREA 0.180700 ;
    PORT
      LAYER Metal2 ;
        RECT 559.960 1249.600 560.360 1250.000 ;
    END
  END psum_in[190]
  PIN psum_in[191]
    DIRECTION INPUT ;
    USE SIGNAL ;
    ANTENNAGATEAREA 0.180700 ;
    PORT
      LAYER Metal2 ;
        RECT 561.880 1249.600 562.280 1250.000 ;
    END
  END psum_in[191]
  PIN psum_in[192]
    DIRECTION INPUT ;
    USE SIGNAL ;
    ANTENNAGATEAREA 0.180700 ;
    PORT
      LAYER Metal2 ;
        RECT 563.800 1249.600 564.200 1250.000 ;
    END
  END psum_in[192]
  PIN psum_in[193]
    DIRECTION INPUT ;
    USE SIGNAL ;
    ANTENNAGATEAREA 0.180700 ;
    PORT
      LAYER Metal2 ;
        RECT 565.720 1249.600 566.120 1250.000 ;
    END
  END psum_in[193]
  PIN psum_in[194]
    DIRECTION INPUT ;
    USE SIGNAL ;
    ANTENNAGATEAREA 0.180700 ;
    PORT
      LAYER Metal2 ;
        RECT 567.640 1249.600 568.040 1250.000 ;
    END
  END psum_in[194]
  PIN psum_in[195]
    DIRECTION INPUT ;
    USE SIGNAL ;
    ANTENNAGATEAREA 0.180700 ;
    PORT
      LAYER Metal2 ;
        RECT 569.560 1249.600 569.960 1250.000 ;
    END
  END psum_in[195]
  PIN psum_in[196]
    DIRECTION INPUT ;
    USE SIGNAL ;
    ANTENNAGATEAREA 0.180700 ;
    PORT
      LAYER Metal2 ;
        RECT 571.480 1249.600 571.880 1250.000 ;
    END
  END psum_in[196]
  PIN psum_in[197]
    DIRECTION INPUT ;
    USE SIGNAL ;
    ANTENNAGATEAREA 0.180700 ;
    PORT
      LAYER Metal2 ;
        RECT 573.400 1249.600 573.800 1250.000 ;
    END
  END psum_in[197]
  PIN psum_in[198]
    DIRECTION INPUT ;
    USE SIGNAL ;
    ANTENNAGATEAREA 0.180700 ;
    PORT
      LAYER Metal2 ;
        RECT 575.320 1249.600 575.720 1250.000 ;
    END
  END psum_in[198]
  PIN psum_in[199]
    DIRECTION INPUT ;
    USE SIGNAL ;
    ANTENNAGATEAREA 0.180700 ;
    PORT
      LAYER Metal2 ;
        RECT 577.240 1249.600 577.640 1250.000 ;
    END
  END psum_in[199]
  PIN psum_in[19]
    DIRECTION INPUT ;
    USE SIGNAL ;
    ANTENNAGATEAREA 0.180700 ;
    PORT
      LAYER Metal2 ;
        RECT 231.640 1249.600 232.040 1250.000 ;
    END
  END psum_in[19]
  PIN psum_in[1]
    DIRECTION INPUT ;
    USE SIGNAL ;
    ANTENNAGATEAREA 0.180700 ;
    PORT
      LAYER Metal2 ;
        RECT 197.080 1249.600 197.480 1250.000 ;
    END
  END psum_in[1]
  PIN psum_in[200]
    DIRECTION INPUT ;
    USE SIGNAL ;
    ANTENNAGATEAREA 0.180700 ;
    PORT
      LAYER Metal2 ;
        RECT 579.160 1249.600 579.560 1250.000 ;
    END
  END psum_in[200]
  PIN psum_in[201]
    DIRECTION INPUT ;
    USE SIGNAL ;
    ANTENNAGATEAREA 0.180700 ;
    PORT
      LAYER Metal2 ;
        RECT 581.080 1249.600 581.480 1250.000 ;
    END
  END psum_in[201]
  PIN psum_in[202]
    DIRECTION INPUT ;
    USE SIGNAL ;
    ANTENNAGATEAREA 0.180700 ;
    PORT
      LAYER Metal2 ;
        RECT 583.000 1249.600 583.400 1250.000 ;
    END
  END psum_in[202]
  PIN psum_in[203]
    DIRECTION INPUT ;
    USE SIGNAL ;
    ANTENNAGATEAREA 0.180700 ;
    PORT
      LAYER Metal2 ;
        RECT 584.920 1249.600 585.320 1250.000 ;
    END
  END psum_in[203]
  PIN psum_in[204]
    DIRECTION INPUT ;
    USE SIGNAL ;
    ANTENNAGATEAREA 0.180700 ;
    PORT
      LAYER Metal2 ;
        RECT 586.840 1249.600 587.240 1250.000 ;
    END
  END psum_in[204]
  PIN psum_in[205]
    DIRECTION INPUT ;
    USE SIGNAL ;
    ANTENNAGATEAREA 0.180700 ;
    PORT
      LAYER Metal2 ;
        RECT 588.760 1249.600 589.160 1250.000 ;
    END
  END psum_in[205]
  PIN psum_in[206]
    DIRECTION INPUT ;
    USE SIGNAL ;
    ANTENNAGATEAREA 0.180700 ;
    PORT
      LAYER Metal2 ;
        RECT 590.680 1249.600 591.080 1250.000 ;
    END
  END psum_in[206]
  PIN psum_in[207]
    DIRECTION INPUT ;
    USE SIGNAL ;
    ANTENNAGATEAREA 0.180700 ;
    PORT
      LAYER Metal2 ;
        RECT 592.600 1249.600 593.000 1250.000 ;
    END
  END psum_in[207]
  PIN psum_in[208]
    DIRECTION INPUT ;
    USE SIGNAL ;
    ANTENNAGATEAREA 0.180700 ;
    PORT
      LAYER Metal2 ;
        RECT 594.520 1249.600 594.920 1250.000 ;
    END
  END psum_in[208]
  PIN psum_in[209]
    DIRECTION INPUT ;
    USE SIGNAL ;
    ANTENNAGATEAREA 0.180700 ;
    PORT
      LAYER Metal2 ;
        RECT 596.440 1249.600 596.840 1250.000 ;
    END
  END psum_in[209]
  PIN psum_in[20]
    DIRECTION INPUT ;
    USE SIGNAL ;
    ANTENNAGATEAREA 0.180700 ;
    PORT
      LAYER Metal2 ;
        RECT 233.560 1249.600 233.960 1250.000 ;
    END
  END psum_in[20]
  PIN psum_in[210]
    DIRECTION INPUT ;
    USE SIGNAL ;
    ANTENNAGATEAREA 0.180700 ;
    PORT
      LAYER Metal2 ;
        RECT 598.360 1249.600 598.760 1250.000 ;
    END
  END psum_in[210]
  PIN psum_in[211]
    DIRECTION INPUT ;
    USE SIGNAL ;
    ANTENNAGATEAREA 0.180700 ;
    PORT
      LAYER Metal2 ;
        RECT 600.280 1249.600 600.680 1250.000 ;
    END
  END psum_in[211]
  PIN psum_in[212]
    DIRECTION INPUT ;
    USE SIGNAL ;
    ANTENNAGATEAREA 0.180700 ;
    PORT
      LAYER Metal2 ;
        RECT 602.200 1249.600 602.600 1250.000 ;
    END
  END psum_in[212]
  PIN psum_in[213]
    DIRECTION INPUT ;
    USE SIGNAL ;
    ANTENNAGATEAREA 0.180700 ;
    PORT
      LAYER Metal2 ;
        RECT 604.120 1249.600 604.520 1250.000 ;
    END
  END psum_in[213]
  PIN psum_in[214]
    DIRECTION INPUT ;
    USE SIGNAL ;
    ANTENNAGATEAREA 0.180700 ;
    PORT
      LAYER Metal2 ;
        RECT 606.040 1249.600 606.440 1250.000 ;
    END
  END psum_in[214]
  PIN psum_in[215]
    DIRECTION INPUT ;
    USE SIGNAL ;
    ANTENNAGATEAREA 0.180700 ;
    PORT
      LAYER Metal2 ;
        RECT 607.960 1249.600 608.360 1250.000 ;
    END
  END psum_in[215]
  PIN psum_in[216]
    DIRECTION INPUT ;
    USE SIGNAL ;
    ANTENNAGATEAREA 0.180700 ;
    PORT
      LAYER Metal2 ;
        RECT 609.880 1249.600 610.280 1250.000 ;
    END
  END psum_in[216]
  PIN psum_in[217]
    DIRECTION INPUT ;
    USE SIGNAL ;
    ANTENNAGATEAREA 0.180700 ;
    PORT
      LAYER Metal2 ;
        RECT 611.800 1249.600 612.200 1250.000 ;
    END
  END psum_in[217]
  PIN psum_in[218]
    DIRECTION INPUT ;
    USE SIGNAL ;
    ANTENNAGATEAREA 0.180700 ;
    PORT
      LAYER Metal2 ;
        RECT 613.720 1249.600 614.120 1250.000 ;
    END
  END psum_in[218]
  PIN psum_in[219]
    DIRECTION INPUT ;
    USE SIGNAL ;
    ANTENNAGATEAREA 0.180700 ;
    PORT
      LAYER Metal2 ;
        RECT 615.640 1249.600 616.040 1250.000 ;
    END
  END psum_in[219]
  PIN psum_in[21]
    DIRECTION INPUT ;
    USE SIGNAL ;
    ANTENNAGATEAREA 0.180700 ;
    PORT
      LAYER Metal2 ;
        RECT 235.480 1249.600 235.880 1250.000 ;
    END
  END psum_in[21]
  PIN psum_in[220]
    DIRECTION INPUT ;
    USE SIGNAL ;
    ANTENNAGATEAREA 0.180700 ;
    PORT
      LAYER Metal2 ;
        RECT 617.560 1249.600 617.960 1250.000 ;
    END
  END psum_in[220]
  PIN psum_in[221]
    DIRECTION INPUT ;
    USE SIGNAL ;
    ANTENNAGATEAREA 0.180700 ;
    PORT
      LAYER Metal2 ;
        RECT 619.480 1249.600 619.880 1250.000 ;
    END
  END psum_in[221]
  PIN psum_in[222]
    DIRECTION INPUT ;
    USE SIGNAL ;
    ANTENNAGATEAREA 0.180700 ;
    PORT
      LAYER Metal2 ;
        RECT 621.400 1249.600 621.800 1250.000 ;
    END
  END psum_in[222]
  PIN psum_in[223]
    DIRECTION INPUT ;
    USE SIGNAL ;
    ANTENNAGATEAREA 0.180700 ;
    PORT
      LAYER Metal2 ;
        RECT 623.320 1249.600 623.720 1250.000 ;
    END
  END psum_in[223]
  PIN psum_in[224]
    DIRECTION INPUT ;
    USE SIGNAL ;
    ANTENNAGATEAREA 0.180700 ;
    PORT
      LAYER Metal2 ;
        RECT 625.240 1249.600 625.640 1250.000 ;
    END
  END psum_in[224]
  PIN psum_in[225]
    DIRECTION INPUT ;
    USE SIGNAL ;
    ANTENNAGATEAREA 0.180700 ;
    PORT
      LAYER Metal2 ;
        RECT 627.160 1249.600 627.560 1250.000 ;
    END
  END psum_in[225]
  PIN psum_in[226]
    DIRECTION INPUT ;
    USE SIGNAL ;
    ANTENNAGATEAREA 0.180700 ;
    PORT
      LAYER Metal2 ;
        RECT 629.080 1249.600 629.480 1250.000 ;
    END
  END psum_in[226]
  PIN psum_in[227]
    DIRECTION INPUT ;
    USE SIGNAL ;
    ANTENNAGATEAREA 0.180700 ;
    PORT
      LAYER Metal2 ;
        RECT 631.000 1249.600 631.400 1250.000 ;
    END
  END psum_in[227]
  PIN psum_in[228]
    DIRECTION INPUT ;
    USE SIGNAL ;
    ANTENNAGATEAREA 0.180700 ;
    PORT
      LAYER Metal2 ;
        RECT 632.920 1249.600 633.320 1250.000 ;
    END
  END psum_in[228]
  PIN psum_in[229]
    DIRECTION INPUT ;
    USE SIGNAL ;
    ANTENNAGATEAREA 0.180700 ;
    PORT
      LAYER Metal2 ;
        RECT 634.840 1249.600 635.240 1250.000 ;
    END
  END psum_in[229]
  PIN psum_in[22]
    DIRECTION INPUT ;
    USE SIGNAL ;
    ANTENNAGATEAREA 0.180700 ;
    PORT
      LAYER Metal2 ;
        RECT 237.400 1249.600 237.800 1250.000 ;
    END
  END psum_in[22]
  PIN psum_in[230]
    DIRECTION INPUT ;
    USE SIGNAL ;
    ANTENNAGATEAREA 0.180700 ;
    PORT
      LAYER Metal2 ;
        RECT 636.760 1249.600 637.160 1250.000 ;
    END
  END psum_in[230]
  PIN psum_in[231]
    DIRECTION INPUT ;
    USE SIGNAL ;
    ANTENNAGATEAREA 0.180700 ;
    PORT
      LAYER Metal2 ;
        RECT 638.680 1249.600 639.080 1250.000 ;
    END
  END psum_in[231]
  PIN psum_in[232]
    DIRECTION INPUT ;
    USE SIGNAL ;
    ANTENNAGATEAREA 0.180700 ;
    PORT
      LAYER Metal2 ;
        RECT 640.600 1249.600 641.000 1250.000 ;
    END
  END psum_in[232]
  PIN psum_in[233]
    DIRECTION INPUT ;
    USE SIGNAL ;
    ANTENNAGATEAREA 0.180700 ;
    PORT
      LAYER Metal2 ;
        RECT 642.520 1249.600 642.920 1250.000 ;
    END
  END psum_in[233]
  PIN psum_in[234]
    DIRECTION INPUT ;
    USE SIGNAL ;
    ANTENNAGATEAREA 0.180700 ;
    PORT
      LAYER Metal2 ;
        RECT 644.440 1249.600 644.840 1250.000 ;
    END
  END psum_in[234]
  PIN psum_in[235]
    DIRECTION INPUT ;
    USE SIGNAL ;
    ANTENNAGATEAREA 0.180700 ;
    PORT
      LAYER Metal2 ;
        RECT 646.360 1249.600 646.760 1250.000 ;
    END
  END psum_in[235]
  PIN psum_in[236]
    DIRECTION INPUT ;
    USE SIGNAL ;
    ANTENNAGATEAREA 0.180700 ;
    PORT
      LAYER Metal2 ;
        RECT 648.280 1249.600 648.680 1250.000 ;
    END
  END psum_in[236]
  PIN psum_in[237]
    DIRECTION INPUT ;
    USE SIGNAL ;
    ANTENNAGATEAREA 0.180700 ;
    PORT
      LAYER Metal2 ;
        RECT 650.200 1249.600 650.600 1250.000 ;
    END
  END psum_in[237]
  PIN psum_in[238]
    DIRECTION INPUT ;
    USE SIGNAL ;
    ANTENNAGATEAREA 0.180700 ;
    PORT
      LAYER Metal2 ;
        RECT 652.120 1249.600 652.520 1250.000 ;
    END
  END psum_in[238]
  PIN psum_in[239]
    DIRECTION INPUT ;
    USE SIGNAL ;
    ANTENNAGATEAREA 0.180700 ;
    PORT
      LAYER Metal2 ;
        RECT 654.040 1249.600 654.440 1250.000 ;
    END
  END psum_in[239]
  PIN psum_in[23]
    DIRECTION INPUT ;
    USE SIGNAL ;
    ANTENNAGATEAREA 0.180700 ;
    PORT
      LAYER Metal2 ;
        RECT 239.320 1249.600 239.720 1250.000 ;
    END
  END psum_in[23]
  PIN psum_in[240]
    DIRECTION INPUT ;
    USE SIGNAL ;
    ANTENNAGATEAREA 0.180700 ;
    PORT
      LAYER Metal2 ;
        RECT 655.960 1249.600 656.360 1250.000 ;
    END
  END psum_in[240]
  PIN psum_in[241]
    DIRECTION INPUT ;
    USE SIGNAL ;
    ANTENNAGATEAREA 0.180700 ;
    PORT
      LAYER Metal2 ;
        RECT 657.880 1249.600 658.280 1250.000 ;
    END
  END psum_in[241]
  PIN psum_in[242]
    DIRECTION INPUT ;
    USE SIGNAL ;
    ANTENNAGATEAREA 0.180700 ;
    PORT
      LAYER Metal2 ;
        RECT 659.800 1249.600 660.200 1250.000 ;
    END
  END psum_in[242]
  PIN psum_in[243]
    DIRECTION INPUT ;
    USE SIGNAL ;
    ANTENNAGATEAREA 0.180700 ;
    PORT
      LAYER Metal2 ;
        RECT 661.720 1249.600 662.120 1250.000 ;
    END
  END psum_in[243]
  PIN psum_in[244]
    DIRECTION INPUT ;
    USE SIGNAL ;
    ANTENNAGATEAREA 0.180700 ;
    PORT
      LAYER Metal2 ;
        RECT 663.640 1249.600 664.040 1250.000 ;
    END
  END psum_in[244]
  PIN psum_in[245]
    DIRECTION INPUT ;
    USE SIGNAL ;
    ANTENNAGATEAREA 0.180700 ;
    PORT
      LAYER Metal2 ;
        RECT 665.560 1249.600 665.960 1250.000 ;
    END
  END psum_in[245]
  PIN psum_in[246]
    DIRECTION INPUT ;
    USE SIGNAL ;
    ANTENNAGATEAREA 0.180700 ;
    PORT
      LAYER Metal2 ;
        RECT 667.480 1249.600 667.880 1250.000 ;
    END
  END psum_in[246]
  PIN psum_in[247]
    DIRECTION INPUT ;
    USE SIGNAL ;
    ANTENNAGATEAREA 0.180700 ;
    PORT
      LAYER Metal2 ;
        RECT 669.400 1249.600 669.800 1250.000 ;
    END
  END psum_in[247]
  PIN psum_in[248]
    DIRECTION INPUT ;
    USE SIGNAL ;
    ANTENNAGATEAREA 0.180700 ;
    PORT
      LAYER Metal2 ;
        RECT 671.320 1249.600 671.720 1250.000 ;
    END
  END psum_in[248]
  PIN psum_in[249]
    DIRECTION INPUT ;
    USE SIGNAL ;
    ANTENNAGATEAREA 0.180700 ;
    PORT
      LAYER Metal2 ;
        RECT 673.240 1249.600 673.640 1250.000 ;
    END
  END psum_in[249]
  PIN psum_in[24]
    DIRECTION INPUT ;
    USE SIGNAL ;
    ANTENNAGATEAREA 0.180700 ;
    PORT
      LAYER Metal2 ;
        RECT 241.240 1249.600 241.640 1250.000 ;
    END
  END psum_in[24]
  PIN psum_in[250]
    DIRECTION INPUT ;
    USE SIGNAL ;
    ANTENNAGATEAREA 0.180700 ;
    PORT
      LAYER Metal2 ;
        RECT 675.160 1249.600 675.560 1250.000 ;
    END
  END psum_in[250]
  PIN psum_in[251]
    DIRECTION INPUT ;
    USE SIGNAL ;
    ANTENNAGATEAREA 0.180700 ;
    PORT
      LAYER Metal2 ;
        RECT 677.080 1249.600 677.480 1250.000 ;
    END
  END psum_in[251]
  PIN psum_in[252]
    DIRECTION INPUT ;
    USE SIGNAL ;
    ANTENNAGATEAREA 0.180700 ;
    PORT
      LAYER Metal2 ;
        RECT 679.000 1249.600 679.400 1250.000 ;
    END
  END psum_in[252]
  PIN psum_in[253]
    DIRECTION INPUT ;
    USE SIGNAL ;
    ANTENNAGATEAREA 0.180700 ;
    PORT
      LAYER Metal2 ;
        RECT 680.920 1249.600 681.320 1250.000 ;
    END
  END psum_in[253]
  PIN psum_in[254]
    DIRECTION INPUT ;
    USE SIGNAL ;
    ANTENNAGATEAREA 0.180700 ;
    PORT
      LAYER Metal2 ;
        RECT 682.840 1249.600 683.240 1250.000 ;
    END
  END psum_in[254]
  PIN psum_in[255]
    DIRECTION INPUT ;
    USE SIGNAL ;
    ANTENNAGATEAREA 0.180700 ;
    PORT
      LAYER Metal2 ;
        RECT 684.760 1249.600 685.160 1250.000 ;
    END
  END psum_in[255]
  PIN psum_in[25]
    DIRECTION INPUT ;
    USE SIGNAL ;
    ANTENNAGATEAREA 0.180700 ;
    PORT
      LAYER Metal2 ;
        RECT 243.160 1249.600 243.560 1250.000 ;
    END
  END psum_in[25]
  PIN psum_in[26]
    DIRECTION INPUT ;
    USE SIGNAL ;
    ANTENNAGATEAREA 0.180700 ;
    PORT
      LAYER Metal2 ;
        RECT 245.080 1249.600 245.480 1250.000 ;
    END
  END psum_in[26]
  PIN psum_in[27]
    DIRECTION INPUT ;
    USE SIGNAL ;
    ANTENNAGATEAREA 0.180700 ;
    PORT
      LAYER Metal2 ;
        RECT 247.000 1249.600 247.400 1250.000 ;
    END
  END psum_in[27]
  PIN psum_in[28]
    DIRECTION INPUT ;
    USE SIGNAL ;
    ANTENNAGATEAREA 0.180700 ;
    PORT
      LAYER Metal2 ;
        RECT 248.920 1249.600 249.320 1250.000 ;
    END
  END psum_in[28]
  PIN psum_in[29]
    DIRECTION INPUT ;
    USE SIGNAL ;
    ANTENNAGATEAREA 0.180700 ;
    PORT
      LAYER Metal2 ;
        RECT 250.840 1249.600 251.240 1250.000 ;
    END
  END psum_in[29]
  PIN psum_in[2]
    DIRECTION INPUT ;
    USE SIGNAL ;
    ANTENNAGATEAREA 0.180700 ;
    PORT
      LAYER Metal2 ;
        RECT 199.000 1249.600 199.400 1250.000 ;
    END
  END psum_in[2]
  PIN psum_in[30]
    DIRECTION INPUT ;
    USE SIGNAL ;
    ANTENNAGATEAREA 0.180700 ;
    PORT
      LAYER Metal2 ;
        RECT 252.760 1249.600 253.160 1250.000 ;
    END
  END psum_in[30]
  PIN psum_in[31]
    DIRECTION INPUT ;
    USE SIGNAL ;
    ANTENNAGATEAREA 0.180700 ;
    PORT
      LAYER Metal2 ;
        RECT 254.680 1249.600 255.080 1250.000 ;
    END
  END psum_in[31]
  PIN psum_in[32]
    DIRECTION INPUT ;
    USE SIGNAL ;
    ANTENNAGATEAREA 0.180700 ;
    PORT
      LAYER Metal2 ;
        RECT 256.600 1249.600 257.000 1250.000 ;
    END
  END psum_in[32]
  PIN psum_in[33]
    DIRECTION INPUT ;
    USE SIGNAL ;
    ANTENNAGATEAREA 0.180700 ;
    PORT
      LAYER Metal2 ;
        RECT 258.520 1249.600 258.920 1250.000 ;
    END
  END psum_in[33]
  PIN psum_in[34]
    DIRECTION INPUT ;
    USE SIGNAL ;
    ANTENNAGATEAREA 0.180700 ;
    PORT
      LAYER Metal2 ;
        RECT 260.440 1249.600 260.840 1250.000 ;
    END
  END psum_in[34]
  PIN psum_in[35]
    DIRECTION INPUT ;
    USE SIGNAL ;
    ANTENNAGATEAREA 0.180700 ;
    PORT
      LAYER Metal2 ;
        RECT 262.360 1249.600 262.760 1250.000 ;
    END
  END psum_in[35]
  PIN psum_in[36]
    DIRECTION INPUT ;
    USE SIGNAL ;
    ANTENNAGATEAREA 0.180700 ;
    PORT
      LAYER Metal2 ;
        RECT 264.280 1249.600 264.680 1250.000 ;
    END
  END psum_in[36]
  PIN psum_in[37]
    DIRECTION INPUT ;
    USE SIGNAL ;
    ANTENNAGATEAREA 0.180700 ;
    PORT
      LAYER Metal2 ;
        RECT 266.200 1249.600 266.600 1250.000 ;
    END
  END psum_in[37]
  PIN psum_in[38]
    DIRECTION INPUT ;
    USE SIGNAL ;
    ANTENNAGATEAREA 0.180700 ;
    PORT
      LAYER Metal2 ;
        RECT 268.120 1249.600 268.520 1250.000 ;
    END
  END psum_in[38]
  PIN psum_in[39]
    DIRECTION INPUT ;
    USE SIGNAL ;
    ANTENNAGATEAREA 0.180700 ;
    PORT
      LAYER Metal2 ;
        RECT 270.040 1249.600 270.440 1250.000 ;
    END
  END psum_in[39]
  PIN psum_in[3]
    DIRECTION INPUT ;
    USE SIGNAL ;
    ANTENNAGATEAREA 0.180700 ;
    PORT
      LAYER Metal2 ;
        RECT 200.920 1249.600 201.320 1250.000 ;
    END
  END psum_in[3]
  PIN psum_in[40]
    DIRECTION INPUT ;
    USE SIGNAL ;
    ANTENNAGATEAREA 0.180700 ;
    PORT
      LAYER Metal2 ;
        RECT 271.960 1249.600 272.360 1250.000 ;
    END
  END psum_in[40]
  PIN psum_in[41]
    DIRECTION INPUT ;
    USE SIGNAL ;
    ANTENNAGATEAREA 0.180700 ;
    PORT
      LAYER Metal2 ;
        RECT 273.880 1249.600 274.280 1250.000 ;
    END
  END psum_in[41]
  PIN psum_in[42]
    DIRECTION INPUT ;
    USE SIGNAL ;
    ANTENNAGATEAREA 0.180700 ;
    PORT
      LAYER Metal2 ;
        RECT 275.800 1249.600 276.200 1250.000 ;
    END
  END psum_in[42]
  PIN psum_in[43]
    DIRECTION INPUT ;
    USE SIGNAL ;
    ANTENNAGATEAREA 0.180700 ;
    PORT
      LAYER Metal2 ;
        RECT 277.720 1249.600 278.120 1250.000 ;
    END
  END psum_in[43]
  PIN psum_in[44]
    DIRECTION INPUT ;
    USE SIGNAL ;
    ANTENNAGATEAREA 0.180700 ;
    PORT
      LAYER Metal2 ;
        RECT 279.640 1249.600 280.040 1250.000 ;
    END
  END psum_in[44]
  PIN psum_in[45]
    DIRECTION INPUT ;
    USE SIGNAL ;
    ANTENNAGATEAREA 0.180700 ;
    PORT
      LAYER Metal2 ;
        RECT 281.560 1249.600 281.960 1250.000 ;
    END
  END psum_in[45]
  PIN psum_in[46]
    DIRECTION INPUT ;
    USE SIGNAL ;
    ANTENNAGATEAREA 0.180700 ;
    PORT
      LAYER Metal2 ;
        RECT 283.480 1249.600 283.880 1250.000 ;
    END
  END psum_in[46]
  PIN psum_in[47]
    DIRECTION INPUT ;
    USE SIGNAL ;
    ANTENNAGATEAREA 0.180700 ;
    PORT
      LAYER Metal2 ;
        RECT 285.400 1249.600 285.800 1250.000 ;
    END
  END psum_in[47]
  PIN psum_in[48]
    DIRECTION INPUT ;
    USE SIGNAL ;
    ANTENNAGATEAREA 0.180700 ;
    PORT
      LAYER Metal2 ;
        RECT 287.320 1249.600 287.720 1250.000 ;
    END
  END psum_in[48]
  PIN psum_in[49]
    DIRECTION INPUT ;
    USE SIGNAL ;
    ANTENNAGATEAREA 0.180700 ;
    PORT
      LAYER Metal2 ;
        RECT 289.240 1249.600 289.640 1250.000 ;
    END
  END psum_in[49]
  PIN psum_in[4]
    DIRECTION INPUT ;
    USE SIGNAL ;
    ANTENNAGATEAREA 0.180700 ;
    PORT
      LAYER Metal2 ;
        RECT 202.840 1249.600 203.240 1250.000 ;
    END
  END psum_in[4]
  PIN psum_in[50]
    DIRECTION INPUT ;
    USE SIGNAL ;
    ANTENNAGATEAREA 0.180700 ;
    PORT
      LAYER Metal2 ;
        RECT 291.160 1249.600 291.560 1250.000 ;
    END
  END psum_in[50]
  PIN psum_in[51]
    DIRECTION INPUT ;
    USE SIGNAL ;
    ANTENNAGATEAREA 0.180700 ;
    PORT
      LAYER Metal2 ;
        RECT 293.080 1249.600 293.480 1250.000 ;
    END
  END psum_in[51]
  PIN psum_in[52]
    DIRECTION INPUT ;
    USE SIGNAL ;
    ANTENNAGATEAREA 0.180700 ;
    PORT
      LAYER Metal2 ;
        RECT 295.000 1249.600 295.400 1250.000 ;
    END
  END psum_in[52]
  PIN psum_in[53]
    DIRECTION INPUT ;
    USE SIGNAL ;
    ANTENNAGATEAREA 0.180700 ;
    PORT
      LAYER Metal2 ;
        RECT 296.920 1249.600 297.320 1250.000 ;
    END
  END psum_in[53]
  PIN psum_in[54]
    DIRECTION INPUT ;
    USE SIGNAL ;
    ANTENNAGATEAREA 0.180700 ;
    PORT
      LAYER Metal2 ;
        RECT 298.840 1249.600 299.240 1250.000 ;
    END
  END psum_in[54]
  PIN psum_in[55]
    DIRECTION INPUT ;
    USE SIGNAL ;
    ANTENNAGATEAREA 0.180700 ;
    PORT
      LAYER Metal2 ;
        RECT 300.760 1249.600 301.160 1250.000 ;
    END
  END psum_in[55]
  PIN psum_in[56]
    DIRECTION INPUT ;
    USE SIGNAL ;
    ANTENNAGATEAREA 0.180700 ;
    PORT
      LAYER Metal2 ;
        RECT 302.680 1249.600 303.080 1250.000 ;
    END
  END psum_in[56]
  PIN psum_in[57]
    DIRECTION INPUT ;
    USE SIGNAL ;
    ANTENNAGATEAREA 0.180700 ;
    PORT
      LAYER Metal2 ;
        RECT 304.600 1249.600 305.000 1250.000 ;
    END
  END psum_in[57]
  PIN psum_in[58]
    DIRECTION INPUT ;
    USE SIGNAL ;
    ANTENNAGATEAREA 0.180700 ;
    PORT
      LAYER Metal2 ;
        RECT 306.520 1249.600 306.920 1250.000 ;
    END
  END psum_in[58]
  PIN psum_in[59]
    DIRECTION INPUT ;
    USE SIGNAL ;
    ANTENNAGATEAREA 0.180700 ;
    PORT
      LAYER Metal2 ;
        RECT 308.440 1249.600 308.840 1250.000 ;
    END
  END psum_in[59]
  PIN psum_in[5]
    DIRECTION INPUT ;
    USE SIGNAL ;
    ANTENNAGATEAREA 0.180700 ;
    PORT
      LAYER Metal2 ;
        RECT 204.760 1249.600 205.160 1250.000 ;
    END
  END psum_in[5]
  PIN psum_in[60]
    DIRECTION INPUT ;
    USE SIGNAL ;
    ANTENNAGATEAREA 0.180700 ;
    PORT
      LAYER Metal2 ;
        RECT 310.360 1249.600 310.760 1250.000 ;
    END
  END psum_in[60]
  PIN psum_in[61]
    DIRECTION INPUT ;
    USE SIGNAL ;
    ANTENNAGATEAREA 0.180700 ;
    PORT
      LAYER Metal2 ;
        RECT 312.280 1249.600 312.680 1250.000 ;
    END
  END psum_in[61]
  PIN psum_in[62]
    DIRECTION INPUT ;
    USE SIGNAL ;
    ANTENNAGATEAREA 0.180700 ;
    PORT
      LAYER Metal2 ;
        RECT 314.200 1249.600 314.600 1250.000 ;
    END
  END psum_in[62]
  PIN psum_in[63]
    DIRECTION INPUT ;
    USE SIGNAL ;
    ANTENNAGATEAREA 0.180700 ;
    PORT
      LAYER Metal2 ;
        RECT 316.120 1249.600 316.520 1250.000 ;
    END
  END psum_in[63]
  PIN psum_in[64]
    DIRECTION INPUT ;
    USE SIGNAL ;
    ANTENNAGATEAREA 0.180700 ;
    PORT
      LAYER Metal2 ;
        RECT 318.040 1249.600 318.440 1250.000 ;
    END
  END psum_in[64]
  PIN psum_in[65]
    DIRECTION INPUT ;
    USE SIGNAL ;
    ANTENNAGATEAREA 0.180700 ;
    PORT
      LAYER Metal2 ;
        RECT 319.960 1249.600 320.360 1250.000 ;
    END
  END psum_in[65]
  PIN psum_in[66]
    DIRECTION INPUT ;
    USE SIGNAL ;
    ANTENNAGATEAREA 0.180700 ;
    PORT
      LAYER Metal2 ;
        RECT 321.880 1249.600 322.280 1250.000 ;
    END
  END psum_in[66]
  PIN psum_in[67]
    DIRECTION INPUT ;
    USE SIGNAL ;
    ANTENNAGATEAREA 0.180700 ;
    PORT
      LAYER Metal2 ;
        RECT 323.800 1249.600 324.200 1250.000 ;
    END
  END psum_in[67]
  PIN psum_in[68]
    DIRECTION INPUT ;
    USE SIGNAL ;
    ANTENNAGATEAREA 0.180700 ;
    PORT
      LAYER Metal2 ;
        RECT 325.720 1249.600 326.120 1250.000 ;
    END
  END psum_in[68]
  PIN psum_in[69]
    DIRECTION INPUT ;
    USE SIGNAL ;
    ANTENNAGATEAREA 0.180700 ;
    PORT
      LAYER Metal2 ;
        RECT 327.640 1249.600 328.040 1250.000 ;
    END
  END psum_in[69]
  PIN psum_in[6]
    DIRECTION INPUT ;
    USE SIGNAL ;
    ANTENNAGATEAREA 0.180700 ;
    PORT
      LAYER Metal2 ;
        RECT 206.680 1249.600 207.080 1250.000 ;
    END
  END psum_in[6]
  PIN psum_in[70]
    DIRECTION INPUT ;
    USE SIGNAL ;
    ANTENNAGATEAREA 0.180700 ;
    PORT
      LAYER Metal2 ;
        RECT 329.560 1249.600 329.960 1250.000 ;
    END
  END psum_in[70]
  PIN psum_in[71]
    DIRECTION INPUT ;
    USE SIGNAL ;
    ANTENNAGATEAREA 0.180700 ;
    PORT
      LAYER Metal2 ;
        RECT 331.480 1249.600 331.880 1250.000 ;
    END
  END psum_in[71]
  PIN psum_in[72]
    DIRECTION INPUT ;
    USE SIGNAL ;
    ANTENNAGATEAREA 0.180700 ;
    PORT
      LAYER Metal2 ;
        RECT 333.400 1249.600 333.800 1250.000 ;
    END
  END psum_in[72]
  PIN psum_in[73]
    DIRECTION INPUT ;
    USE SIGNAL ;
    ANTENNAGATEAREA 0.180700 ;
    PORT
      LAYER Metal2 ;
        RECT 335.320 1249.600 335.720 1250.000 ;
    END
  END psum_in[73]
  PIN psum_in[74]
    DIRECTION INPUT ;
    USE SIGNAL ;
    ANTENNAGATEAREA 0.180700 ;
    PORT
      LAYER Metal2 ;
        RECT 337.240 1249.600 337.640 1250.000 ;
    END
  END psum_in[74]
  PIN psum_in[75]
    DIRECTION INPUT ;
    USE SIGNAL ;
    ANTENNAGATEAREA 0.180700 ;
    PORT
      LAYER Metal2 ;
        RECT 339.160 1249.600 339.560 1250.000 ;
    END
  END psum_in[75]
  PIN psum_in[76]
    DIRECTION INPUT ;
    USE SIGNAL ;
    ANTENNAGATEAREA 0.180700 ;
    PORT
      LAYER Metal2 ;
        RECT 341.080 1249.600 341.480 1250.000 ;
    END
  END psum_in[76]
  PIN psum_in[77]
    DIRECTION INPUT ;
    USE SIGNAL ;
    ANTENNAGATEAREA 0.180700 ;
    PORT
      LAYER Metal2 ;
        RECT 343.000 1249.600 343.400 1250.000 ;
    END
  END psum_in[77]
  PIN psum_in[78]
    DIRECTION INPUT ;
    USE SIGNAL ;
    ANTENNAGATEAREA 0.180700 ;
    PORT
      LAYER Metal2 ;
        RECT 344.920 1249.600 345.320 1250.000 ;
    END
  END psum_in[78]
  PIN psum_in[79]
    DIRECTION INPUT ;
    USE SIGNAL ;
    ANTENNAGATEAREA 0.180700 ;
    PORT
      LAYER Metal2 ;
        RECT 346.840 1249.600 347.240 1250.000 ;
    END
  END psum_in[79]
  PIN psum_in[7]
    DIRECTION INPUT ;
    USE SIGNAL ;
    ANTENNAGATEAREA 0.180700 ;
    PORT
      LAYER Metal2 ;
        RECT 208.600 1249.600 209.000 1250.000 ;
    END
  END psum_in[7]
  PIN psum_in[80]
    DIRECTION INPUT ;
    USE SIGNAL ;
    ANTENNAGATEAREA 0.180700 ;
    PORT
      LAYER Metal2 ;
        RECT 348.760 1249.600 349.160 1250.000 ;
    END
  END psum_in[80]
  PIN psum_in[81]
    DIRECTION INPUT ;
    USE SIGNAL ;
    ANTENNAGATEAREA 0.180700 ;
    PORT
      LAYER Metal2 ;
        RECT 350.680 1249.600 351.080 1250.000 ;
    END
  END psum_in[81]
  PIN psum_in[82]
    DIRECTION INPUT ;
    USE SIGNAL ;
    ANTENNAGATEAREA 0.180700 ;
    PORT
      LAYER Metal2 ;
        RECT 352.600 1249.600 353.000 1250.000 ;
    END
  END psum_in[82]
  PIN psum_in[83]
    DIRECTION INPUT ;
    USE SIGNAL ;
    ANTENNAGATEAREA 0.180700 ;
    PORT
      LAYER Metal2 ;
        RECT 354.520 1249.600 354.920 1250.000 ;
    END
  END psum_in[83]
  PIN psum_in[84]
    DIRECTION INPUT ;
    USE SIGNAL ;
    ANTENNAGATEAREA 0.180700 ;
    PORT
      LAYER Metal2 ;
        RECT 356.440 1249.600 356.840 1250.000 ;
    END
  END psum_in[84]
  PIN psum_in[85]
    DIRECTION INPUT ;
    USE SIGNAL ;
    ANTENNAGATEAREA 0.180700 ;
    PORT
      LAYER Metal2 ;
        RECT 358.360 1249.600 358.760 1250.000 ;
    END
  END psum_in[85]
  PIN psum_in[86]
    DIRECTION INPUT ;
    USE SIGNAL ;
    ANTENNAGATEAREA 0.180700 ;
    PORT
      LAYER Metal2 ;
        RECT 360.280 1249.600 360.680 1250.000 ;
    END
  END psum_in[86]
  PIN psum_in[87]
    DIRECTION INPUT ;
    USE SIGNAL ;
    ANTENNAGATEAREA 0.180700 ;
    PORT
      LAYER Metal2 ;
        RECT 362.200 1249.600 362.600 1250.000 ;
    END
  END psum_in[87]
  PIN psum_in[88]
    DIRECTION INPUT ;
    USE SIGNAL ;
    ANTENNAGATEAREA 0.180700 ;
    PORT
      LAYER Metal2 ;
        RECT 364.120 1249.600 364.520 1250.000 ;
    END
  END psum_in[88]
  PIN psum_in[89]
    DIRECTION INPUT ;
    USE SIGNAL ;
    ANTENNAGATEAREA 0.180700 ;
    PORT
      LAYER Metal2 ;
        RECT 366.040 1249.600 366.440 1250.000 ;
    END
  END psum_in[89]
  PIN psum_in[8]
    DIRECTION INPUT ;
    USE SIGNAL ;
    ANTENNAGATEAREA 0.180700 ;
    PORT
      LAYER Metal2 ;
        RECT 210.520 1249.600 210.920 1250.000 ;
    END
  END psum_in[8]
  PIN psum_in[90]
    DIRECTION INPUT ;
    USE SIGNAL ;
    ANTENNAGATEAREA 0.180700 ;
    PORT
      LAYER Metal2 ;
        RECT 367.960 1249.600 368.360 1250.000 ;
    END
  END psum_in[90]
  PIN psum_in[91]
    DIRECTION INPUT ;
    USE SIGNAL ;
    ANTENNAGATEAREA 0.180700 ;
    PORT
      LAYER Metal2 ;
        RECT 369.880 1249.600 370.280 1250.000 ;
    END
  END psum_in[91]
  PIN psum_in[92]
    DIRECTION INPUT ;
    USE SIGNAL ;
    ANTENNAGATEAREA 0.180700 ;
    PORT
      LAYER Metal2 ;
        RECT 371.800 1249.600 372.200 1250.000 ;
    END
  END psum_in[92]
  PIN psum_in[93]
    DIRECTION INPUT ;
    USE SIGNAL ;
    ANTENNAGATEAREA 0.180700 ;
    PORT
      LAYER Metal2 ;
        RECT 373.720 1249.600 374.120 1250.000 ;
    END
  END psum_in[93]
  PIN psum_in[94]
    DIRECTION INPUT ;
    USE SIGNAL ;
    ANTENNAGATEAREA 0.180700 ;
    PORT
      LAYER Metal2 ;
        RECT 375.640 1249.600 376.040 1250.000 ;
    END
  END psum_in[94]
  PIN psum_in[95]
    DIRECTION INPUT ;
    USE SIGNAL ;
    ANTENNAGATEAREA 0.180700 ;
    PORT
      LAYER Metal2 ;
        RECT 377.560 1249.600 377.960 1250.000 ;
    END
  END psum_in[95]
  PIN psum_in[96]
    DIRECTION INPUT ;
    USE SIGNAL ;
    ANTENNAGATEAREA 0.180700 ;
    PORT
      LAYER Metal2 ;
        RECT 379.480 1249.600 379.880 1250.000 ;
    END
  END psum_in[96]
  PIN psum_in[97]
    DIRECTION INPUT ;
    USE SIGNAL ;
    ANTENNAGATEAREA 0.180700 ;
    PORT
      LAYER Metal2 ;
        RECT 381.400 1249.600 381.800 1250.000 ;
    END
  END psum_in[97]
  PIN psum_in[98]
    DIRECTION INPUT ;
    USE SIGNAL ;
    ANTENNAGATEAREA 0.180700 ;
    PORT
      LAYER Metal2 ;
        RECT 383.320 1249.600 383.720 1250.000 ;
    END
  END psum_in[98]
  PIN psum_in[99]
    DIRECTION INPUT ;
    USE SIGNAL ;
    ANTENNAGATEAREA 0.180700 ;
    PORT
      LAYER Metal2 ;
        RECT 385.240 1249.600 385.640 1250.000 ;
    END
  END psum_in[99]
  PIN psum_in[9]
    DIRECTION INPUT ;
    USE SIGNAL ;
    ANTENNAGATEAREA 0.180700 ;
    PORT
      LAYER Metal2 ;
        RECT 212.440 1249.600 212.840 1250.000 ;
    END
  END psum_in[9]
  PIN psum_out[0]
    DIRECTION OUTPUT ;
    USE SIGNAL ;
    ANTENNADIFFAREA 0.708600 ;
    PORT
      LAYER Metal2 ;
        RECT 686.680 1249.600 687.080 1250.000 ;
    END
  END psum_out[0]
  PIN psum_out[100]
    DIRECTION OUTPUT ;
    USE SIGNAL ;
    ANTENNADIFFAREA 0.708600 ;
    PORT
      LAYER Metal2 ;
        RECT 878.680 1249.600 879.080 1250.000 ;
    END
  END psum_out[100]
  PIN psum_out[101]
    DIRECTION OUTPUT ;
    USE SIGNAL ;
    ANTENNADIFFAREA 0.708600 ;
    PORT
      LAYER Metal2 ;
        RECT 880.600 1249.600 881.000 1250.000 ;
    END
  END psum_out[101]
  PIN psum_out[102]
    DIRECTION OUTPUT ;
    USE SIGNAL ;
    ANTENNADIFFAREA 0.708600 ;
    PORT
      LAYER Metal2 ;
        RECT 882.520 1249.600 882.920 1250.000 ;
    END
  END psum_out[102]
  PIN psum_out[103]
    DIRECTION OUTPUT ;
    USE SIGNAL ;
    ANTENNADIFFAREA 0.708600 ;
    PORT
      LAYER Metal2 ;
        RECT 884.440 1249.600 884.840 1250.000 ;
    END
  END psum_out[103]
  PIN psum_out[104]
    DIRECTION OUTPUT ;
    USE SIGNAL ;
    ANTENNADIFFAREA 0.708600 ;
    PORT
      LAYER Metal2 ;
        RECT 886.360 1249.600 886.760 1250.000 ;
    END
  END psum_out[104]
  PIN psum_out[105]
    DIRECTION OUTPUT ;
    USE SIGNAL ;
    ANTENNADIFFAREA 0.708600 ;
    PORT
      LAYER Metal2 ;
        RECT 888.280 1249.600 888.680 1250.000 ;
    END
  END psum_out[105]
  PIN psum_out[106]
    DIRECTION OUTPUT ;
    USE SIGNAL ;
    ANTENNADIFFAREA 0.708600 ;
    PORT
      LAYER Metal2 ;
        RECT 890.200 1249.600 890.600 1250.000 ;
    END
  END psum_out[106]
  PIN psum_out[107]
    DIRECTION OUTPUT ;
    USE SIGNAL ;
    ANTENNADIFFAREA 0.708600 ;
    PORT
      LAYER Metal2 ;
        RECT 892.120 1249.600 892.520 1250.000 ;
    END
  END psum_out[107]
  PIN psum_out[108]
    DIRECTION OUTPUT ;
    USE SIGNAL ;
    ANTENNADIFFAREA 0.708600 ;
    PORT
      LAYER Metal2 ;
        RECT 894.040 1249.600 894.440 1250.000 ;
    END
  END psum_out[108]
  PIN psum_out[109]
    DIRECTION OUTPUT ;
    USE SIGNAL ;
    ANTENNADIFFAREA 0.708600 ;
    PORT
      LAYER Metal2 ;
        RECT 895.960 1249.600 896.360 1250.000 ;
    END
  END psum_out[109]
  PIN psum_out[10]
    DIRECTION OUTPUT ;
    USE SIGNAL ;
    ANTENNADIFFAREA 0.708600 ;
    PORT
      LAYER Metal2 ;
        RECT 705.880 1249.600 706.280 1250.000 ;
    END
  END psum_out[10]
  PIN psum_out[110]
    DIRECTION OUTPUT ;
    USE SIGNAL ;
    ANTENNADIFFAREA 0.708600 ;
    PORT
      LAYER Metal2 ;
        RECT 897.880 1249.600 898.280 1250.000 ;
    END
  END psum_out[110]
  PIN psum_out[111]
    DIRECTION OUTPUT ;
    USE SIGNAL ;
    ANTENNADIFFAREA 0.708600 ;
    PORT
      LAYER Metal2 ;
        RECT 899.800 1249.600 900.200 1250.000 ;
    END
  END psum_out[111]
  PIN psum_out[112]
    DIRECTION OUTPUT ;
    USE SIGNAL ;
    ANTENNADIFFAREA 0.708600 ;
    PORT
      LAYER Metal2 ;
        RECT 901.720 1249.600 902.120 1250.000 ;
    END
  END psum_out[112]
  PIN psum_out[113]
    DIRECTION OUTPUT ;
    USE SIGNAL ;
    ANTENNADIFFAREA 0.708600 ;
    PORT
      LAYER Metal2 ;
        RECT 903.640 1249.600 904.040 1250.000 ;
    END
  END psum_out[113]
  PIN psum_out[114]
    DIRECTION OUTPUT ;
    USE SIGNAL ;
    ANTENNADIFFAREA 0.708600 ;
    PORT
      LAYER Metal2 ;
        RECT 905.560 1249.600 905.960 1250.000 ;
    END
  END psum_out[114]
  PIN psum_out[115]
    DIRECTION OUTPUT ;
    USE SIGNAL ;
    ANTENNADIFFAREA 0.708600 ;
    PORT
      LAYER Metal2 ;
        RECT 907.480 1249.600 907.880 1250.000 ;
    END
  END psum_out[115]
  PIN psum_out[116]
    DIRECTION OUTPUT ;
    USE SIGNAL ;
    ANTENNADIFFAREA 0.708600 ;
    PORT
      LAYER Metal2 ;
        RECT 909.400 1249.600 909.800 1250.000 ;
    END
  END psum_out[116]
  PIN psum_out[117]
    DIRECTION OUTPUT ;
    USE SIGNAL ;
    ANTENNADIFFAREA 0.708600 ;
    PORT
      LAYER Metal2 ;
        RECT 911.320 1249.600 911.720 1250.000 ;
    END
  END psum_out[117]
  PIN psum_out[118]
    DIRECTION OUTPUT ;
    USE SIGNAL ;
    ANTENNADIFFAREA 0.708600 ;
    PORT
      LAYER Metal2 ;
        RECT 913.240 1249.600 913.640 1250.000 ;
    END
  END psum_out[118]
  PIN psum_out[119]
    DIRECTION OUTPUT ;
    USE SIGNAL ;
    ANTENNADIFFAREA 0.708600 ;
    PORT
      LAYER Metal2 ;
        RECT 915.160 1249.600 915.560 1250.000 ;
    END
  END psum_out[119]
  PIN psum_out[11]
    DIRECTION OUTPUT ;
    USE SIGNAL ;
    ANTENNADIFFAREA 0.708600 ;
    PORT
      LAYER Metal2 ;
        RECT 707.800 1249.600 708.200 1250.000 ;
    END
  END psum_out[11]
  PIN psum_out[120]
    DIRECTION OUTPUT ;
    USE SIGNAL ;
    ANTENNADIFFAREA 0.708600 ;
    PORT
      LAYER Metal2 ;
        RECT 917.080 1249.600 917.480 1250.000 ;
    END
  END psum_out[120]
  PIN psum_out[121]
    DIRECTION OUTPUT ;
    USE SIGNAL ;
    ANTENNADIFFAREA 0.708600 ;
    PORT
      LAYER Metal2 ;
        RECT 919.000 1249.600 919.400 1250.000 ;
    END
  END psum_out[121]
  PIN psum_out[122]
    DIRECTION OUTPUT ;
    USE SIGNAL ;
    ANTENNADIFFAREA 0.708600 ;
    PORT
      LAYER Metal2 ;
        RECT 920.920 1249.600 921.320 1250.000 ;
    END
  END psum_out[122]
  PIN psum_out[123]
    DIRECTION OUTPUT ;
    USE SIGNAL ;
    ANTENNADIFFAREA 0.708600 ;
    PORT
      LAYER Metal2 ;
        RECT 922.840 1249.600 923.240 1250.000 ;
    END
  END psum_out[123]
  PIN psum_out[124]
    DIRECTION OUTPUT ;
    USE SIGNAL ;
    ANTENNADIFFAREA 0.708600 ;
    PORT
      LAYER Metal2 ;
        RECT 924.760 1249.600 925.160 1250.000 ;
    END
  END psum_out[124]
  PIN psum_out[125]
    DIRECTION OUTPUT ;
    USE SIGNAL ;
    ANTENNADIFFAREA 0.708600 ;
    PORT
      LAYER Metal2 ;
        RECT 926.680 1249.600 927.080 1250.000 ;
    END
  END psum_out[125]
  PIN psum_out[126]
    DIRECTION OUTPUT ;
    USE SIGNAL ;
    ANTENNADIFFAREA 0.708600 ;
    PORT
      LAYER Metal2 ;
        RECT 928.600 1249.600 929.000 1250.000 ;
    END
  END psum_out[126]
  PIN psum_out[127]
    DIRECTION OUTPUT ;
    USE SIGNAL ;
    ANTENNADIFFAREA 0.708600 ;
    PORT
      LAYER Metal2 ;
        RECT 930.520 1249.600 930.920 1250.000 ;
    END
  END psum_out[127]
  PIN psum_out[128]
    DIRECTION OUTPUT ;
    USE SIGNAL ;
    ANTENNADIFFAREA 0.708600 ;
    PORT
      LAYER Metal2 ;
        RECT 932.440 1249.600 932.840 1250.000 ;
    END
  END psum_out[128]
  PIN psum_out[129]
    DIRECTION OUTPUT ;
    USE SIGNAL ;
    ANTENNADIFFAREA 0.708600 ;
    PORT
      LAYER Metal2 ;
        RECT 934.360 1249.600 934.760 1250.000 ;
    END
  END psum_out[129]
  PIN psum_out[12]
    DIRECTION OUTPUT ;
    USE SIGNAL ;
    ANTENNADIFFAREA 0.708600 ;
    PORT
      LAYER Metal2 ;
        RECT 709.720 1249.600 710.120 1250.000 ;
    END
  END psum_out[12]
  PIN psum_out[130]
    DIRECTION OUTPUT ;
    USE SIGNAL ;
    ANTENNADIFFAREA 0.708600 ;
    PORT
      LAYER Metal2 ;
        RECT 936.280 1249.600 936.680 1250.000 ;
    END
  END psum_out[130]
  PIN psum_out[131]
    DIRECTION OUTPUT ;
    USE SIGNAL ;
    ANTENNADIFFAREA 0.708600 ;
    PORT
      LAYER Metal2 ;
        RECT 938.200 1249.600 938.600 1250.000 ;
    END
  END psum_out[131]
  PIN psum_out[132]
    DIRECTION OUTPUT ;
    USE SIGNAL ;
    ANTENNADIFFAREA 0.708600 ;
    PORT
      LAYER Metal2 ;
        RECT 940.120 1249.600 940.520 1250.000 ;
    END
  END psum_out[132]
  PIN psum_out[133]
    DIRECTION OUTPUT ;
    USE SIGNAL ;
    ANTENNADIFFAREA 0.708600 ;
    PORT
      LAYER Metal2 ;
        RECT 942.040 1249.600 942.440 1250.000 ;
    END
  END psum_out[133]
  PIN psum_out[134]
    DIRECTION OUTPUT ;
    USE SIGNAL ;
    ANTENNADIFFAREA 0.708600 ;
    PORT
      LAYER Metal2 ;
        RECT 943.960 1249.600 944.360 1250.000 ;
    END
  END psum_out[134]
  PIN psum_out[135]
    DIRECTION OUTPUT ;
    USE SIGNAL ;
    ANTENNADIFFAREA 0.708600 ;
    PORT
      LAYER Metal2 ;
        RECT 945.880 1249.600 946.280 1250.000 ;
    END
  END psum_out[135]
  PIN psum_out[136]
    DIRECTION OUTPUT ;
    USE SIGNAL ;
    ANTENNADIFFAREA 0.708600 ;
    PORT
      LAYER Metal2 ;
        RECT 947.800 1249.600 948.200 1250.000 ;
    END
  END psum_out[136]
  PIN psum_out[137]
    DIRECTION OUTPUT ;
    USE SIGNAL ;
    ANTENNADIFFAREA 0.708600 ;
    PORT
      LAYER Metal2 ;
        RECT 949.720 1249.600 950.120 1250.000 ;
    END
  END psum_out[137]
  PIN psum_out[138]
    DIRECTION OUTPUT ;
    USE SIGNAL ;
    ANTENNADIFFAREA 0.708600 ;
    PORT
      LAYER Metal2 ;
        RECT 951.640 1249.600 952.040 1250.000 ;
    END
  END psum_out[138]
  PIN psum_out[139]
    DIRECTION OUTPUT ;
    USE SIGNAL ;
    ANTENNADIFFAREA 0.708600 ;
    PORT
      LAYER Metal2 ;
        RECT 953.560 1249.600 953.960 1250.000 ;
    END
  END psum_out[139]
  PIN psum_out[13]
    DIRECTION OUTPUT ;
    USE SIGNAL ;
    ANTENNADIFFAREA 0.708600 ;
    PORT
      LAYER Metal2 ;
        RECT 711.640 1249.600 712.040 1250.000 ;
    END
  END psum_out[13]
  PIN psum_out[140]
    DIRECTION OUTPUT ;
    USE SIGNAL ;
    ANTENNADIFFAREA 0.708600 ;
    PORT
      LAYER Metal2 ;
        RECT 955.480 1249.600 955.880 1250.000 ;
    END
  END psum_out[140]
  PIN psum_out[141]
    DIRECTION OUTPUT ;
    USE SIGNAL ;
    ANTENNADIFFAREA 0.708600 ;
    PORT
      LAYER Metal2 ;
        RECT 957.400 1249.600 957.800 1250.000 ;
    END
  END psum_out[141]
  PIN psum_out[142]
    DIRECTION OUTPUT ;
    USE SIGNAL ;
    ANTENNADIFFAREA 0.708600 ;
    PORT
      LAYER Metal2 ;
        RECT 959.320 1249.600 959.720 1250.000 ;
    END
  END psum_out[142]
  PIN psum_out[143]
    DIRECTION OUTPUT ;
    USE SIGNAL ;
    ANTENNADIFFAREA 0.708600 ;
    PORT
      LAYER Metal2 ;
        RECT 961.240 1249.600 961.640 1250.000 ;
    END
  END psum_out[143]
  PIN psum_out[144]
    DIRECTION OUTPUT ;
    USE SIGNAL ;
    ANTENNADIFFAREA 0.708600 ;
    PORT
      LAYER Metal2 ;
        RECT 963.160 1249.600 963.560 1250.000 ;
    END
  END psum_out[144]
  PIN psum_out[145]
    DIRECTION OUTPUT ;
    USE SIGNAL ;
    ANTENNADIFFAREA 0.708600 ;
    PORT
      LAYER Metal2 ;
        RECT 965.080 1249.600 965.480 1250.000 ;
    END
  END psum_out[145]
  PIN psum_out[146]
    DIRECTION OUTPUT ;
    USE SIGNAL ;
    ANTENNADIFFAREA 0.708600 ;
    PORT
      LAYER Metal2 ;
        RECT 967.000 1249.600 967.400 1250.000 ;
    END
  END psum_out[146]
  PIN psum_out[147]
    DIRECTION OUTPUT ;
    USE SIGNAL ;
    ANTENNADIFFAREA 0.708600 ;
    PORT
      LAYER Metal2 ;
        RECT 968.920 1249.600 969.320 1250.000 ;
    END
  END psum_out[147]
  PIN psum_out[148]
    DIRECTION OUTPUT ;
    USE SIGNAL ;
    ANTENNADIFFAREA 0.708600 ;
    PORT
      LAYER Metal2 ;
        RECT 970.840 1249.600 971.240 1250.000 ;
    END
  END psum_out[148]
  PIN psum_out[149]
    DIRECTION OUTPUT ;
    USE SIGNAL ;
    ANTENNADIFFAREA 0.708600 ;
    PORT
      LAYER Metal2 ;
        RECT 972.760 1249.600 973.160 1250.000 ;
    END
  END psum_out[149]
  PIN psum_out[14]
    DIRECTION OUTPUT ;
    USE SIGNAL ;
    ANTENNADIFFAREA 0.708600 ;
    PORT
      LAYER Metal2 ;
        RECT 713.560 1249.600 713.960 1250.000 ;
    END
  END psum_out[14]
  PIN psum_out[150]
    DIRECTION OUTPUT ;
    USE SIGNAL ;
    ANTENNADIFFAREA 0.708600 ;
    PORT
      LAYER Metal2 ;
        RECT 974.680 1249.600 975.080 1250.000 ;
    END
  END psum_out[150]
  PIN psum_out[151]
    DIRECTION OUTPUT ;
    USE SIGNAL ;
    ANTENNADIFFAREA 0.708600 ;
    PORT
      LAYER Metal2 ;
        RECT 976.600 1249.600 977.000 1250.000 ;
    END
  END psum_out[151]
  PIN psum_out[152]
    DIRECTION OUTPUT ;
    USE SIGNAL ;
    ANTENNADIFFAREA 0.708600 ;
    PORT
      LAYER Metal2 ;
        RECT 978.520 1249.600 978.920 1250.000 ;
    END
  END psum_out[152]
  PIN psum_out[153]
    DIRECTION OUTPUT ;
    USE SIGNAL ;
    ANTENNADIFFAREA 0.708600 ;
    PORT
      LAYER Metal2 ;
        RECT 980.440 1249.600 980.840 1250.000 ;
    END
  END psum_out[153]
  PIN psum_out[154]
    DIRECTION OUTPUT ;
    USE SIGNAL ;
    ANTENNADIFFAREA 0.708600 ;
    PORT
      LAYER Metal2 ;
        RECT 982.360 1249.600 982.760 1250.000 ;
    END
  END psum_out[154]
  PIN psum_out[155]
    DIRECTION OUTPUT ;
    USE SIGNAL ;
    ANTENNADIFFAREA 0.708600 ;
    PORT
      LAYER Metal2 ;
        RECT 984.280 1249.600 984.680 1250.000 ;
    END
  END psum_out[155]
  PIN psum_out[156]
    DIRECTION OUTPUT ;
    USE SIGNAL ;
    ANTENNADIFFAREA 0.708600 ;
    PORT
      LAYER Metal2 ;
        RECT 986.200 1249.600 986.600 1250.000 ;
    END
  END psum_out[156]
  PIN psum_out[157]
    DIRECTION OUTPUT ;
    USE SIGNAL ;
    ANTENNADIFFAREA 0.708600 ;
    PORT
      LAYER Metal2 ;
        RECT 988.120 1249.600 988.520 1250.000 ;
    END
  END psum_out[157]
  PIN psum_out[158]
    DIRECTION OUTPUT ;
    USE SIGNAL ;
    ANTENNADIFFAREA 0.708600 ;
    PORT
      LAYER Metal2 ;
        RECT 990.040 1249.600 990.440 1250.000 ;
    END
  END psum_out[158]
  PIN psum_out[159]
    DIRECTION OUTPUT ;
    USE SIGNAL ;
    ANTENNADIFFAREA 0.708600 ;
    PORT
      LAYER Metal2 ;
        RECT 991.960 1249.600 992.360 1250.000 ;
    END
  END psum_out[159]
  PIN psum_out[15]
    DIRECTION OUTPUT ;
    USE SIGNAL ;
    ANTENNADIFFAREA 0.708600 ;
    PORT
      LAYER Metal2 ;
        RECT 715.480 1249.600 715.880 1250.000 ;
    END
  END psum_out[15]
  PIN psum_out[160]
    DIRECTION OUTPUT ;
    USE SIGNAL ;
    ANTENNADIFFAREA 0.708600 ;
    PORT
      LAYER Metal2 ;
        RECT 993.880 1249.600 994.280 1250.000 ;
    END
  END psum_out[160]
  PIN psum_out[161]
    DIRECTION OUTPUT ;
    USE SIGNAL ;
    ANTENNADIFFAREA 0.708600 ;
    PORT
      LAYER Metal2 ;
        RECT 995.800 1249.600 996.200 1250.000 ;
    END
  END psum_out[161]
  PIN psum_out[162]
    DIRECTION OUTPUT ;
    USE SIGNAL ;
    ANTENNADIFFAREA 0.708600 ;
    PORT
      LAYER Metal2 ;
        RECT 997.720 1249.600 998.120 1250.000 ;
    END
  END psum_out[162]
  PIN psum_out[163]
    DIRECTION OUTPUT ;
    USE SIGNAL ;
    ANTENNADIFFAREA 0.708600 ;
    PORT
      LAYER Metal2 ;
        RECT 999.640 1249.600 1000.040 1250.000 ;
    END
  END psum_out[163]
  PIN psum_out[164]
    DIRECTION OUTPUT ;
    USE SIGNAL ;
    ANTENNADIFFAREA 0.708600 ;
    PORT
      LAYER Metal2 ;
        RECT 1001.560 1249.600 1001.960 1250.000 ;
    END
  END psum_out[164]
  PIN psum_out[165]
    DIRECTION OUTPUT ;
    USE SIGNAL ;
    ANTENNADIFFAREA 0.708600 ;
    PORT
      LAYER Metal2 ;
        RECT 1003.480 1249.600 1003.880 1250.000 ;
    END
  END psum_out[165]
  PIN psum_out[166]
    DIRECTION OUTPUT ;
    USE SIGNAL ;
    ANTENNADIFFAREA 0.708600 ;
    PORT
      LAYER Metal2 ;
        RECT 1005.400 1249.600 1005.800 1250.000 ;
    END
  END psum_out[166]
  PIN psum_out[167]
    DIRECTION OUTPUT ;
    USE SIGNAL ;
    ANTENNADIFFAREA 0.708600 ;
    PORT
      LAYER Metal2 ;
        RECT 1007.320 1249.600 1007.720 1250.000 ;
    END
  END psum_out[167]
  PIN psum_out[168]
    DIRECTION OUTPUT ;
    USE SIGNAL ;
    ANTENNADIFFAREA 0.708600 ;
    PORT
      LAYER Metal2 ;
        RECT 1009.240 1249.600 1009.640 1250.000 ;
    END
  END psum_out[168]
  PIN psum_out[169]
    DIRECTION OUTPUT ;
    USE SIGNAL ;
    ANTENNADIFFAREA 0.708600 ;
    PORT
      LAYER Metal2 ;
        RECT 1011.160 1249.600 1011.560 1250.000 ;
    END
  END psum_out[169]
  PIN psum_out[16]
    DIRECTION OUTPUT ;
    USE SIGNAL ;
    ANTENNADIFFAREA 0.708600 ;
    PORT
      LAYER Metal2 ;
        RECT 717.400 1249.600 717.800 1250.000 ;
    END
  END psum_out[16]
  PIN psum_out[170]
    DIRECTION OUTPUT ;
    USE SIGNAL ;
    ANTENNADIFFAREA 0.708600 ;
    PORT
      LAYER Metal2 ;
        RECT 1013.080 1249.600 1013.480 1250.000 ;
    END
  END psum_out[170]
  PIN psum_out[171]
    DIRECTION OUTPUT ;
    USE SIGNAL ;
    ANTENNADIFFAREA 0.708600 ;
    PORT
      LAYER Metal2 ;
        RECT 1015.000 1249.600 1015.400 1250.000 ;
    END
  END psum_out[171]
  PIN psum_out[172]
    DIRECTION OUTPUT ;
    USE SIGNAL ;
    ANTENNADIFFAREA 0.708600 ;
    PORT
      LAYER Metal2 ;
        RECT 1016.920 1249.600 1017.320 1250.000 ;
    END
  END psum_out[172]
  PIN psum_out[173]
    DIRECTION OUTPUT ;
    USE SIGNAL ;
    ANTENNADIFFAREA 0.708600 ;
    PORT
      LAYER Metal2 ;
        RECT 1018.840 1249.600 1019.240 1250.000 ;
    END
  END psum_out[173]
  PIN psum_out[174]
    DIRECTION OUTPUT ;
    USE SIGNAL ;
    ANTENNADIFFAREA 0.708600 ;
    PORT
      LAYER Metal2 ;
        RECT 1020.760 1249.600 1021.160 1250.000 ;
    END
  END psum_out[174]
  PIN psum_out[175]
    DIRECTION OUTPUT ;
    USE SIGNAL ;
    ANTENNADIFFAREA 0.708600 ;
    PORT
      LAYER Metal2 ;
        RECT 1022.680 1249.600 1023.080 1250.000 ;
    END
  END psum_out[175]
  PIN psum_out[176]
    DIRECTION OUTPUT ;
    USE SIGNAL ;
    ANTENNADIFFAREA 0.708600 ;
    PORT
      LAYER Metal2 ;
        RECT 1024.600 1249.600 1025.000 1250.000 ;
    END
  END psum_out[176]
  PIN psum_out[177]
    DIRECTION OUTPUT ;
    USE SIGNAL ;
    ANTENNADIFFAREA 0.708600 ;
    PORT
      LAYER Metal2 ;
        RECT 1026.520 1249.600 1026.920 1250.000 ;
    END
  END psum_out[177]
  PIN psum_out[178]
    DIRECTION OUTPUT ;
    USE SIGNAL ;
    ANTENNADIFFAREA 0.708600 ;
    PORT
      LAYER Metal2 ;
        RECT 1028.440 1249.600 1028.840 1250.000 ;
    END
  END psum_out[178]
  PIN psum_out[179]
    DIRECTION OUTPUT ;
    USE SIGNAL ;
    ANTENNADIFFAREA 0.708600 ;
    PORT
      LAYER Metal2 ;
        RECT 1030.360 1249.600 1030.760 1250.000 ;
    END
  END psum_out[179]
  PIN psum_out[17]
    DIRECTION OUTPUT ;
    USE SIGNAL ;
    ANTENNADIFFAREA 0.708600 ;
    PORT
      LAYER Metal2 ;
        RECT 719.320 1249.600 719.720 1250.000 ;
    END
  END psum_out[17]
  PIN psum_out[180]
    DIRECTION OUTPUT ;
    USE SIGNAL ;
    ANTENNADIFFAREA 0.708600 ;
    PORT
      LAYER Metal2 ;
        RECT 1032.280 1249.600 1032.680 1250.000 ;
    END
  END psum_out[180]
  PIN psum_out[181]
    DIRECTION OUTPUT ;
    USE SIGNAL ;
    ANTENNADIFFAREA 0.708600 ;
    PORT
      LAYER Metal2 ;
        RECT 1034.200 1249.600 1034.600 1250.000 ;
    END
  END psum_out[181]
  PIN psum_out[182]
    DIRECTION OUTPUT ;
    USE SIGNAL ;
    ANTENNADIFFAREA 0.708600 ;
    PORT
      LAYER Metal2 ;
        RECT 1036.120 1249.600 1036.520 1250.000 ;
    END
  END psum_out[182]
  PIN psum_out[183]
    DIRECTION OUTPUT ;
    USE SIGNAL ;
    ANTENNADIFFAREA 0.708600 ;
    PORT
      LAYER Metal2 ;
        RECT 1038.040 1249.600 1038.440 1250.000 ;
    END
  END psum_out[183]
  PIN psum_out[184]
    DIRECTION OUTPUT ;
    USE SIGNAL ;
    ANTENNADIFFAREA 0.708600 ;
    PORT
      LAYER Metal2 ;
        RECT 1039.960 1249.600 1040.360 1250.000 ;
    END
  END psum_out[184]
  PIN psum_out[185]
    DIRECTION OUTPUT ;
    USE SIGNAL ;
    ANTENNADIFFAREA 0.708600 ;
    PORT
      LAYER Metal2 ;
        RECT 1041.880 1249.600 1042.280 1250.000 ;
    END
  END psum_out[185]
  PIN psum_out[186]
    DIRECTION OUTPUT ;
    USE SIGNAL ;
    ANTENNADIFFAREA 0.708600 ;
    PORT
      LAYER Metal2 ;
        RECT 1043.800 1249.600 1044.200 1250.000 ;
    END
  END psum_out[186]
  PIN psum_out[187]
    DIRECTION OUTPUT ;
    USE SIGNAL ;
    ANTENNADIFFAREA 0.708600 ;
    PORT
      LAYER Metal2 ;
        RECT 1045.720 1249.600 1046.120 1250.000 ;
    END
  END psum_out[187]
  PIN psum_out[188]
    DIRECTION OUTPUT ;
    USE SIGNAL ;
    ANTENNADIFFAREA 0.708600 ;
    PORT
      LAYER Metal2 ;
        RECT 1047.640 1249.600 1048.040 1250.000 ;
    END
  END psum_out[188]
  PIN psum_out[189]
    DIRECTION OUTPUT ;
    USE SIGNAL ;
    ANTENNADIFFAREA 0.708600 ;
    PORT
      LAYER Metal2 ;
        RECT 1049.560 1249.600 1049.960 1250.000 ;
    END
  END psum_out[189]
  PIN psum_out[18]
    DIRECTION OUTPUT ;
    USE SIGNAL ;
    ANTENNADIFFAREA 0.708600 ;
    PORT
      LAYER Metal2 ;
        RECT 721.240 1249.600 721.640 1250.000 ;
    END
  END psum_out[18]
  PIN psum_out[190]
    DIRECTION OUTPUT ;
    USE SIGNAL ;
    ANTENNADIFFAREA 0.708600 ;
    PORT
      LAYER Metal2 ;
        RECT 1051.480 1249.600 1051.880 1250.000 ;
    END
  END psum_out[190]
  PIN psum_out[191]
    DIRECTION OUTPUT ;
    USE SIGNAL ;
    ANTENNADIFFAREA 0.708600 ;
    PORT
      LAYER Metal2 ;
        RECT 1053.400 1249.600 1053.800 1250.000 ;
    END
  END psum_out[191]
  PIN psum_out[192]
    DIRECTION OUTPUT ;
    USE SIGNAL ;
    ANTENNADIFFAREA 0.708600 ;
    PORT
      LAYER Metal2 ;
        RECT 1055.320 1249.600 1055.720 1250.000 ;
    END
  END psum_out[192]
  PIN psum_out[193]
    DIRECTION OUTPUT ;
    USE SIGNAL ;
    ANTENNADIFFAREA 0.708600 ;
    PORT
      LAYER Metal2 ;
        RECT 1057.240 1249.600 1057.640 1250.000 ;
    END
  END psum_out[193]
  PIN psum_out[194]
    DIRECTION OUTPUT ;
    USE SIGNAL ;
    ANTENNADIFFAREA 0.708600 ;
    PORT
      LAYER Metal2 ;
        RECT 1059.160 1249.600 1059.560 1250.000 ;
    END
  END psum_out[194]
  PIN psum_out[195]
    DIRECTION OUTPUT ;
    USE SIGNAL ;
    ANTENNADIFFAREA 0.708600 ;
    PORT
      LAYER Metal2 ;
        RECT 1061.080 1249.600 1061.480 1250.000 ;
    END
  END psum_out[195]
  PIN psum_out[196]
    DIRECTION OUTPUT ;
    USE SIGNAL ;
    ANTENNADIFFAREA 0.708600 ;
    PORT
      LAYER Metal2 ;
        RECT 1063.000 1249.600 1063.400 1250.000 ;
    END
  END psum_out[196]
  PIN psum_out[197]
    DIRECTION OUTPUT ;
    USE SIGNAL ;
    ANTENNADIFFAREA 0.708600 ;
    PORT
      LAYER Metal2 ;
        RECT 1064.920 1249.600 1065.320 1250.000 ;
    END
  END psum_out[197]
  PIN psum_out[198]
    DIRECTION OUTPUT ;
    USE SIGNAL ;
    ANTENNADIFFAREA 0.708600 ;
    PORT
      LAYER Metal2 ;
        RECT 1066.840 1249.600 1067.240 1250.000 ;
    END
  END psum_out[198]
  PIN psum_out[199]
    DIRECTION OUTPUT ;
    USE SIGNAL ;
    ANTENNADIFFAREA 0.708600 ;
    PORT
      LAYER Metal2 ;
        RECT 1068.760 1249.600 1069.160 1250.000 ;
    END
  END psum_out[199]
  PIN psum_out[19]
    DIRECTION OUTPUT ;
    USE SIGNAL ;
    ANTENNADIFFAREA 0.708600 ;
    PORT
      LAYER Metal2 ;
        RECT 723.160 1249.600 723.560 1250.000 ;
    END
  END psum_out[19]
  PIN psum_out[1]
    DIRECTION OUTPUT ;
    USE SIGNAL ;
    ANTENNADIFFAREA 0.708600 ;
    PORT
      LAYER Metal2 ;
        RECT 688.600 1249.600 689.000 1250.000 ;
    END
  END psum_out[1]
  PIN psum_out[200]
    DIRECTION OUTPUT ;
    USE SIGNAL ;
    ANTENNADIFFAREA 0.708600 ;
    PORT
      LAYER Metal2 ;
        RECT 1070.680 1249.600 1071.080 1250.000 ;
    END
  END psum_out[200]
  PIN psum_out[201]
    DIRECTION OUTPUT ;
    USE SIGNAL ;
    ANTENNADIFFAREA 0.708600 ;
    PORT
      LAYER Metal2 ;
        RECT 1072.600 1249.600 1073.000 1250.000 ;
    END
  END psum_out[201]
  PIN psum_out[202]
    DIRECTION OUTPUT ;
    USE SIGNAL ;
    ANTENNADIFFAREA 0.708600 ;
    PORT
      LAYER Metal2 ;
        RECT 1074.520 1249.600 1074.920 1250.000 ;
    END
  END psum_out[202]
  PIN psum_out[203]
    DIRECTION OUTPUT ;
    USE SIGNAL ;
    ANTENNADIFFAREA 0.708600 ;
    PORT
      LAYER Metal2 ;
        RECT 1076.440 1249.600 1076.840 1250.000 ;
    END
  END psum_out[203]
  PIN psum_out[204]
    DIRECTION OUTPUT ;
    USE SIGNAL ;
    ANTENNADIFFAREA 0.708600 ;
    PORT
      LAYER Metal2 ;
        RECT 1078.360 1249.600 1078.760 1250.000 ;
    END
  END psum_out[204]
  PIN psum_out[205]
    DIRECTION OUTPUT ;
    USE SIGNAL ;
    ANTENNADIFFAREA 0.708600 ;
    PORT
      LAYER Metal2 ;
        RECT 1080.280 1249.600 1080.680 1250.000 ;
    END
  END psum_out[205]
  PIN psum_out[206]
    DIRECTION OUTPUT ;
    USE SIGNAL ;
    ANTENNADIFFAREA 0.708600 ;
    PORT
      LAYER Metal2 ;
        RECT 1082.200 1249.600 1082.600 1250.000 ;
    END
  END psum_out[206]
  PIN psum_out[207]
    DIRECTION OUTPUT ;
    USE SIGNAL ;
    ANTENNADIFFAREA 0.708600 ;
    PORT
      LAYER Metal2 ;
        RECT 1084.120 1249.600 1084.520 1250.000 ;
    END
  END psum_out[207]
  PIN psum_out[208]
    DIRECTION OUTPUT ;
    USE SIGNAL ;
    ANTENNADIFFAREA 0.708600 ;
    PORT
      LAYER Metal2 ;
        RECT 1086.040 1249.600 1086.440 1250.000 ;
    END
  END psum_out[208]
  PIN psum_out[209]
    DIRECTION OUTPUT ;
    USE SIGNAL ;
    ANTENNADIFFAREA 0.708600 ;
    PORT
      LAYER Metal2 ;
        RECT 1087.960 1249.600 1088.360 1250.000 ;
    END
  END psum_out[209]
  PIN psum_out[20]
    DIRECTION OUTPUT ;
    USE SIGNAL ;
    ANTENNADIFFAREA 0.708600 ;
    PORT
      LAYER Metal2 ;
        RECT 725.080 1249.600 725.480 1250.000 ;
    END
  END psum_out[20]
  PIN psum_out[210]
    DIRECTION OUTPUT ;
    USE SIGNAL ;
    ANTENNADIFFAREA 0.708600 ;
    PORT
      LAYER Metal2 ;
        RECT 1089.880 1249.600 1090.280 1250.000 ;
    END
  END psum_out[210]
  PIN psum_out[211]
    DIRECTION OUTPUT ;
    USE SIGNAL ;
    ANTENNADIFFAREA 0.708600 ;
    PORT
      LAYER Metal2 ;
        RECT 1091.800 1249.600 1092.200 1250.000 ;
    END
  END psum_out[211]
  PIN psum_out[212]
    DIRECTION OUTPUT ;
    USE SIGNAL ;
    ANTENNADIFFAREA 0.708600 ;
    PORT
      LAYER Metal2 ;
        RECT 1093.720 1249.600 1094.120 1250.000 ;
    END
  END psum_out[212]
  PIN psum_out[213]
    DIRECTION OUTPUT ;
    USE SIGNAL ;
    ANTENNADIFFAREA 0.708600 ;
    PORT
      LAYER Metal2 ;
        RECT 1095.640 1249.600 1096.040 1250.000 ;
    END
  END psum_out[213]
  PIN psum_out[214]
    DIRECTION OUTPUT ;
    USE SIGNAL ;
    ANTENNADIFFAREA 0.708600 ;
    PORT
      LAYER Metal2 ;
        RECT 1097.560 1249.600 1097.960 1250.000 ;
    END
  END psum_out[214]
  PIN psum_out[215]
    DIRECTION OUTPUT ;
    USE SIGNAL ;
    ANTENNADIFFAREA 0.708600 ;
    PORT
      LAYER Metal2 ;
        RECT 1099.480 1249.600 1099.880 1250.000 ;
    END
  END psum_out[215]
  PIN psum_out[216]
    DIRECTION OUTPUT ;
    USE SIGNAL ;
    ANTENNADIFFAREA 0.708600 ;
    PORT
      LAYER Metal2 ;
        RECT 1101.400 1249.600 1101.800 1250.000 ;
    END
  END psum_out[216]
  PIN psum_out[217]
    DIRECTION OUTPUT ;
    USE SIGNAL ;
    ANTENNADIFFAREA 0.708600 ;
    PORT
      LAYER Metal2 ;
        RECT 1103.320 1249.600 1103.720 1250.000 ;
    END
  END psum_out[217]
  PIN psum_out[218]
    DIRECTION OUTPUT ;
    USE SIGNAL ;
    ANTENNADIFFAREA 0.708600 ;
    PORT
      LAYER Metal2 ;
        RECT 1105.240 1249.600 1105.640 1250.000 ;
    END
  END psum_out[218]
  PIN psum_out[219]
    DIRECTION OUTPUT ;
    USE SIGNAL ;
    ANTENNADIFFAREA 0.708600 ;
    PORT
      LAYER Metal2 ;
        RECT 1107.160 1249.600 1107.560 1250.000 ;
    END
  END psum_out[219]
  PIN psum_out[21]
    DIRECTION OUTPUT ;
    USE SIGNAL ;
    ANTENNADIFFAREA 0.708600 ;
    PORT
      LAYER Metal2 ;
        RECT 727.000 1249.600 727.400 1250.000 ;
    END
  END psum_out[21]
  PIN psum_out[220]
    DIRECTION OUTPUT ;
    USE SIGNAL ;
    ANTENNADIFFAREA 0.708600 ;
    PORT
      LAYER Metal2 ;
        RECT 1109.080 1249.600 1109.480 1250.000 ;
    END
  END psum_out[220]
  PIN psum_out[221]
    DIRECTION OUTPUT ;
    USE SIGNAL ;
    ANTENNADIFFAREA 0.708600 ;
    PORT
      LAYER Metal2 ;
        RECT 1111.000 1249.600 1111.400 1250.000 ;
    END
  END psum_out[221]
  PIN psum_out[222]
    DIRECTION OUTPUT ;
    USE SIGNAL ;
    ANTENNADIFFAREA 0.708600 ;
    PORT
      LAYER Metal2 ;
        RECT 1112.920 1249.600 1113.320 1250.000 ;
    END
  END psum_out[222]
  PIN psum_out[223]
    DIRECTION OUTPUT ;
    USE SIGNAL ;
    ANTENNADIFFAREA 0.708600 ;
    PORT
      LAYER Metal2 ;
        RECT 1114.840 1249.600 1115.240 1250.000 ;
    END
  END psum_out[223]
  PIN psum_out[224]
    DIRECTION OUTPUT ;
    USE SIGNAL ;
    ANTENNADIFFAREA 0.708600 ;
    PORT
      LAYER Metal2 ;
        RECT 1116.760 1249.600 1117.160 1250.000 ;
    END
  END psum_out[224]
  PIN psum_out[225]
    DIRECTION OUTPUT ;
    USE SIGNAL ;
    ANTENNADIFFAREA 0.708600 ;
    PORT
      LAYER Metal2 ;
        RECT 1118.680 1249.600 1119.080 1250.000 ;
    END
  END psum_out[225]
  PIN psum_out[226]
    DIRECTION OUTPUT ;
    USE SIGNAL ;
    ANTENNADIFFAREA 0.708600 ;
    PORT
      LAYER Metal2 ;
        RECT 1120.600 1249.600 1121.000 1250.000 ;
    END
  END psum_out[226]
  PIN psum_out[227]
    DIRECTION OUTPUT ;
    USE SIGNAL ;
    ANTENNADIFFAREA 0.708600 ;
    PORT
      LAYER Metal2 ;
        RECT 1122.520 1249.600 1122.920 1250.000 ;
    END
  END psum_out[227]
  PIN psum_out[228]
    DIRECTION OUTPUT ;
    USE SIGNAL ;
    ANTENNADIFFAREA 0.708600 ;
    PORT
      LAYER Metal2 ;
        RECT 1124.440 1249.600 1124.840 1250.000 ;
    END
  END psum_out[228]
  PIN psum_out[229]
    DIRECTION OUTPUT ;
    USE SIGNAL ;
    ANTENNADIFFAREA 0.708600 ;
    PORT
      LAYER Metal2 ;
        RECT 1126.360 1249.600 1126.760 1250.000 ;
    END
  END psum_out[229]
  PIN psum_out[22]
    DIRECTION OUTPUT ;
    USE SIGNAL ;
    ANTENNADIFFAREA 0.708600 ;
    PORT
      LAYER Metal2 ;
        RECT 728.920 1249.600 729.320 1250.000 ;
    END
  END psum_out[22]
  PIN psum_out[230]
    DIRECTION OUTPUT ;
    USE SIGNAL ;
    ANTENNADIFFAREA 0.708600 ;
    PORT
      LAYER Metal2 ;
        RECT 1128.280 1249.600 1128.680 1250.000 ;
    END
  END psum_out[230]
  PIN psum_out[231]
    DIRECTION OUTPUT ;
    USE SIGNAL ;
    ANTENNADIFFAREA 0.708600 ;
    PORT
      LAYER Metal2 ;
        RECT 1130.200 1249.600 1130.600 1250.000 ;
    END
  END psum_out[231]
  PIN psum_out[232]
    DIRECTION OUTPUT ;
    USE SIGNAL ;
    ANTENNADIFFAREA 0.708600 ;
    PORT
      LAYER Metal2 ;
        RECT 1132.120 1249.600 1132.520 1250.000 ;
    END
  END psum_out[232]
  PIN psum_out[233]
    DIRECTION OUTPUT ;
    USE SIGNAL ;
    ANTENNADIFFAREA 0.708600 ;
    PORT
      LAYER Metal2 ;
        RECT 1134.040 1249.600 1134.440 1250.000 ;
    END
  END psum_out[233]
  PIN psum_out[234]
    DIRECTION OUTPUT ;
    USE SIGNAL ;
    ANTENNADIFFAREA 0.708600 ;
    PORT
      LAYER Metal2 ;
        RECT 1135.960 1249.600 1136.360 1250.000 ;
    END
  END psum_out[234]
  PIN psum_out[235]
    DIRECTION OUTPUT ;
    USE SIGNAL ;
    ANTENNADIFFAREA 0.708600 ;
    PORT
      LAYER Metal2 ;
        RECT 1137.880 1249.600 1138.280 1250.000 ;
    END
  END psum_out[235]
  PIN psum_out[236]
    DIRECTION OUTPUT ;
    USE SIGNAL ;
    ANTENNADIFFAREA 0.708600 ;
    PORT
      LAYER Metal2 ;
        RECT 1139.800 1249.600 1140.200 1250.000 ;
    END
  END psum_out[236]
  PIN psum_out[237]
    DIRECTION OUTPUT ;
    USE SIGNAL ;
    ANTENNADIFFAREA 0.708600 ;
    PORT
      LAYER Metal2 ;
        RECT 1141.720 1249.600 1142.120 1250.000 ;
    END
  END psum_out[237]
  PIN psum_out[238]
    DIRECTION OUTPUT ;
    USE SIGNAL ;
    ANTENNADIFFAREA 0.708600 ;
    PORT
      LAYER Metal2 ;
        RECT 1143.640 1249.600 1144.040 1250.000 ;
    END
  END psum_out[238]
  PIN psum_out[239]
    DIRECTION OUTPUT ;
    USE SIGNAL ;
    ANTENNADIFFAREA 0.708600 ;
    PORT
      LAYER Metal2 ;
        RECT 1145.560 1249.600 1145.960 1250.000 ;
    END
  END psum_out[239]
  PIN psum_out[23]
    DIRECTION OUTPUT ;
    USE SIGNAL ;
    ANTENNADIFFAREA 0.708600 ;
    PORT
      LAYER Metal2 ;
        RECT 730.840 1249.600 731.240 1250.000 ;
    END
  END psum_out[23]
  PIN psum_out[240]
    DIRECTION OUTPUT ;
    USE SIGNAL ;
    ANTENNADIFFAREA 0.708600 ;
    PORT
      LAYER Metal2 ;
        RECT 1147.480 1249.600 1147.880 1250.000 ;
    END
  END psum_out[240]
  PIN psum_out[241]
    DIRECTION OUTPUT ;
    USE SIGNAL ;
    ANTENNADIFFAREA 0.708600 ;
    PORT
      LAYER Metal2 ;
        RECT 1149.400 1249.600 1149.800 1250.000 ;
    END
  END psum_out[241]
  PIN psum_out[242]
    DIRECTION OUTPUT ;
    USE SIGNAL ;
    ANTENNADIFFAREA 0.708600 ;
    PORT
      LAYER Metal2 ;
        RECT 1151.320 1249.600 1151.720 1250.000 ;
    END
  END psum_out[242]
  PIN psum_out[243]
    DIRECTION OUTPUT ;
    USE SIGNAL ;
    ANTENNADIFFAREA 0.708600 ;
    PORT
      LAYER Metal2 ;
        RECT 1153.240 1249.600 1153.640 1250.000 ;
    END
  END psum_out[243]
  PIN psum_out[244]
    DIRECTION OUTPUT ;
    USE SIGNAL ;
    ANTENNADIFFAREA 0.708600 ;
    PORT
      LAYER Metal2 ;
        RECT 1155.160 1249.600 1155.560 1250.000 ;
    END
  END psum_out[244]
  PIN psum_out[245]
    DIRECTION OUTPUT ;
    USE SIGNAL ;
    ANTENNADIFFAREA 0.708600 ;
    PORT
      LAYER Metal2 ;
        RECT 1157.080 1249.600 1157.480 1250.000 ;
    END
  END psum_out[245]
  PIN psum_out[246]
    DIRECTION OUTPUT ;
    USE SIGNAL ;
    ANTENNADIFFAREA 0.708600 ;
    PORT
      LAYER Metal2 ;
        RECT 1159.000 1249.600 1159.400 1250.000 ;
    END
  END psum_out[246]
  PIN psum_out[247]
    DIRECTION OUTPUT ;
    USE SIGNAL ;
    ANTENNADIFFAREA 0.708600 ;
    PORT
      LAYER Metal2 ;
        RECT 1160.920 1249.600 1161.320 1250.000 ;
    END
  END psum_out[247]
  PIN psum_out[248]
    DIRECTION OUTPUT ;
    USE SIGNAL ;
    ANTENNADIFFAREA 0.708600 ;
    PORT
      LAYER Metal2 ;
        RECT 1162.840 1249.600 1163.240 1250.000 ;
    END
  END psum_out[248]
  PIN psum_out[249]
    DIRECTION OUTPUT ;
    USE SIGNAL ;
    ANTENNADIFFAREA 0.708600 ;
    PORT
      LAYER Metal2 ;
        RECT 1164.760 1249.600 1165.160 1250.000 ;
    END
  END psum_out[249]
  PIN psum_out[24]
    DIRECTION OUTPUT ;
    USE SIGNAL ;
    ANTENNADIFFAREA 0.708600 ;
    PORT
      LAYER Metal2 ;
        RECT 732.760 1249.600 733.160 1250.000 ;
    END
  END psum_out[24]
  PIN psum_out[250]
    DIRECTION OUTPUT ;
    USE SIGNAL ;
    ANTENNADIFFAREA 0.708600 ;
    PORT
      LAYER Metal2 ;
        RECT 1166.680 1249.600 1167.080 1250.000 ;
    END
  END psum_out[250]
  PIN psum_out[251]
    DIRECTION OUTPUT ;
    USE SIGNAL ;
    ANTENNADIFFAREA 0.708600 ;
    PORT
      LAYER Metal2 ;
        RECT 1168.600 1249.600 1169.000 1250.000 ;
    END
  END psum_out[251]
  PIN psum_out[252]
    DIRECTION OUTPUT ;
    USE SIGNAL ;
    ANTENNADIFFAREA 0.708600 ;
    PORT
      LAYER Metal2 ;
        RECT 1170.520 1249.600 1170.920 1250.000 ;
    END
  END psum_out[252]
  PIN psum_out[253]
    DIRECTION OUTPUT ;
    USE SIGNAL ;
    ANTENNADIFFAREA 0.708600 ;
    PORT
      LAYER Metal2 ;
        RECT 1172.440 1249.600 1172.840 1250.000 ;
    END
  END psum_out[253]
  PIN psum_out[254]
    DIRECTION OUTPUT ;
    USE SIGNAL ;
    ANTENNADIFFAREA 0.708600 ;
    PORT
      LAYER Metal2 ;
        RECT 1174.360 1249.600 1174.760 1250.000 ;
    END
  END psum_out[254]
  PIN psum_out[255]
    DIRECTION OUTPUT ;
    USE SIGNAL ;
    ANTENNADIFFAREA 0.708600 ;
    PORT
      LAYER Metal2 ;
        RECT 1176.280 1249.600 1176.680 1250.000 ;
    END
  END psum_out[255]
  PIN psum_out[25]
    DIRECTION OUTPUT ;
    USE SIGNAL ;
    ANTENNADIFFAREA 0.708600 ;
    PORT
      LAYER Metal2 ;
        RECT 734.680 1249.600 735.080 1250.000 ;
    END
  END psum_out[25]
  PIN psum_out[26]
    DIRECTION OUTPUT ;
    USE SIGNAL ;
    ANTENNADIFFAREA 0.708600 ;
    PORT
      LAYER Metal2 ;
        RECT 736.600 1249.600 737.000 1250.000 ;
    END
  END psum_out[26]
  PIN psum_out[27]
    DIRECTION OUTPUT ;
    USE SIGNAL ;
    ANTENNADIFFAREA 0.708600 ;
    PORT
      LAYER Metal2 ;
        RECT 738.520 1249.600 738.920 1250.000 ;
    END
  END psum_out[27]
  PIN psum_out[28]
    DIRECTION OUTPUT ;
    USE SIGNAL ;
    ANTENNADIFFAREA 0.708600 ;
    PORT
      LAYER Metal2 ;
        RECT 740.440 1249.600 740.840 1250.000 ;
    END
  END psum_out[28]
  PIN psum_out[29]
    DIRECTION OUTPUT ;
    USE SIGNAL ;
    ANTENNADIFFAREA 0.708600 ;
    PORT
      LAYER Metal2 ;
        RECT 742.360 1249.600 742.760 1250.000 ;
    END
  END psum_out[29]
  PIN psum_out[2]
    DIRECTION OUTPUT ;
    USE SIGNAL ;
    ANTENNADIFFAREA 0.708600 ;
    PORT
      LAYER Metal2 ;
        RECT 690.520 1249.600 690.920 1250.000 ;
    END
  END psum_out[2]
  PIN psum_out[30]
    DIRECTION OUTPUT ;
    USE SIGNAL ;
    ANTENNADIFFAREA 0.708600 ;
    PORT
      LAYER Metal2 ;
        RECT 744.280 1249.600 744.680 1250.000 ;
    END
  END psum_out[30]
  PIN psum_out[31]
    DIRECTION OUTPUT ;
    USE SIGNAL ;
    ANTENNADIFFAREA 0.708600 ;
    PORT
      LAYER Metal2 ;
        RECT 746.200 1249.600 746.600 1250.000 ;
    END
  END psum_out[31]
  PIN psum_out[32]
    DIRECTION OUTPUT ;
    USE SIGNAL ;
    ANTENNADIFFAREA 0.708600 ;
    PORT
      LAYER Metal2 ;
        RECT 748.120 1249.600 748.520 1250.000 ;
    END
  END psum_out[32]
  PIN psum_out[33]
    DIRECTION OUTPUT ;
    USE SIGNAL ;
    ANTENNADIFFAREA 0.708600 ;
    PORT
      LAYER Metal2 ;
        RECT 750.040 1249.600 750.440 1250.000 ;
    END
  END psum_out[33]
  PIN psum_out[34]
    DIRECTION OUTPUT ;
    USE SIGNAL ;
    ANTENNADIFFAREA 0.708600 ;
    PORT
      LAYER Metal2 ;
        RECT 751.960 1249.600 752.360 1250.000 ;
    END
  END psum_out[34]
  PIN psum_out[35]
    DIRECTION OUTPUT ;
    USE SIGNAL ;
    ANTENNADIFFAREA 0.708600 ;
    PORT
      LAYER Metal2 ;
        RECT 753.880 1249.600 754.280 1250.000 ;
    END
  END psum_out[35]
  PIN psum_out[36]
    DIRECTION OUTPUT ;
    USE SIGNAL ;
    ANTENNADIFFAREA 0.708600 ;
    PORT
      LAYER Metal2 ;
        RECT 755.800 1249.600 756.200 1250.000 ;
    END
  END psum_out[36]
  PIN psum_out[37]
    DIRECTION OUTPUT ;
    USE SIGNAL ;
    ANTENNADIFFAREA 0.708600 ;
    PORT
      LAYER Metal2 ;
        RECT 757.720 1249.600 758.120 1250.000 ;
    END
  END psum_out[37]
  PIN psum_out[38]
    DIRECTION OUTPUT ;
    USE SIGNAL ;
    ANTENNADIFFAREA 0.708600 ;
    PORT
      LAYER Metal2 ;
        RECT 759.640 1249.600 760.040 1250.000 ;
    END
  END psum_out[38]
  PIN psum_out[39]
    DIRECTION OUTPUT ;
    USE SIGNAL ;
    ANTENNADIFFAREA 0.708600 ;
    PORT
      LAYER Metal2 ;
        RECT 761.560 1249.600 761.960 1250.000 ;
    END
  END psum_out[39]
  PIN psum_out[3]
    DIRECTION OUTPUT ;
    USE SIGNAL ;
    ANTENNADIFFAREA 0.708600 ;
    PORT
      LAYER Metal2 ;
        RECT 692.440 1249.600 692.840 1250.000 ;
    END
  END psum_out[3]
  PIN psum_out[40]
    DIRECTION OUTPUT ;
    USE SIGNAL ;
    ANTENNADIFFAREA 0.708600 ;
    PORT
      LAYER Metal2 ;
        RECT 763.480 1249.600 763.880 1250.000 ;
    END
  END psum_out[40]
  PIN psum_out[41]
    DIRECTION OUTPUT ;
    USE SIGNAL ;
    ANTENNADIFFAREA 0.708600 ;
    PORT
      LAYER Metal2 ;
        RECT 765.400 1249.600 765.800 1250.000 ;
    END
  END psum_out[41]
  PIN psum_out[42]
    DIRECTION OUTPUT ;
    USE SIGNAL ;
    ANTENNADIFFAREA 0.708600 ;
    PORT
      LAYER Metal2 ;
        RECT 767.320 1249.600 767.720 1250.000 ;
    END
  END psum_out[42]
  PIN psum_out[43]
    DIRECTION OUTPUT ;
    USE SIGNAL ;
    ANTENNADIFFAREA 0.708600 ;
    PORT
      LAYER Metal2 ;
        RECT 769.240 1249.600 769.640 1250.000 ;
    END
  END psum_out[43]
  PIN psum_out[44]
    DIRECTION OUTPUT ;
    USE SIGNAL ;
    ANTENNADIFFAREA 0.708600 ;
    PORT
      LAYER Metal2 ;
        RECT 771.160 1249.600 771.560 1250.000 ;
    END
  END psum_out[44]
  PIN psum_out[45]
    DIRECTION OUTPUT ;
    USE SIGNAL ;
    ANTENNADIFFAREA 0.708600 ;
    PORT
      LAYER Metal2 ;
        RECT 773.080 1249.600 773.480 1250.000 ;
    END
  END psum_out[45]
  PIN psum_out[46]
    DIRECTION OUTPUT ;
    USE SIGNAL ;
    ANTENNADIFFAREA 0.708600 ;
    PORT
      LAYER Metal2 ;
        RECT 775.000 1249.600 775.400 1250.000 ;
    END
  END psum_out[46]
  PIN psum_out[47]
    DIRECTION OUTPUT ;
    USE SIGNAL ;
    ANTENNADIFFAREA 0.708600 ;
    PORT
      LAYER Metal2 ;
        RECT 776.920 1249.600 777.320 1250.000 ;
    END
  END psum_out[47]
  PIN psum_out[48]
    DIRECTION OUTPUT ;
    USE SIGNAL ;
    ANTENNADIFFAREA 0.708600 ;
    PORT
      LAYER Metal2 ;
        RECT 778.840 1249.600 779.240 1250.000 ;
    END
  END psum_out[48]
  PIN psum_out[49]
    DIRECTION OUTPUT ;
    USE SIGNAL ;
    ANTENNADIFFAREA 0.708600 ;
    PORT
      LAYER Metal2 ;
        RECT 780.760 1249.600 781.160 1250.000 ;
    END
  END psum_out[49]
  PIN psum_out[4]
    DIRECTION OUTPUT ;
    USE SIGNAL ;
    ANTENNADIFFAREA 0.708600 ;
    PORT
      LAYER Metal2 ;
        RECT 694.360 1249.600 694.760 1250.000 ;
    END
  END psum_out[4]
  PIN psum_out[50]
    DIRECTION OUTPUT ;
    USE SIGNAL ;
    ANTENNADIFFAREA 0.708600 ;
    PORT
      LAYER Metal2 ;
        RECT 782.680 1249.600 783.080 1250.000 ;
    END
  END psum_out[50]
  PIN psum_out[51]
    DIRECTION OUTPUT ;
    USE SIGNAL ;
    ANTENNADIFFAREA 0.708600 ;
    PORT
      LAYER Metal2 ;
        RECT 784.600 1249.600 785.000 1250.000 ;
    END
  END psum_out[51]
  PIN psum_out[52]
    DIRECTION OUTPUT ;
    USE SIGNAL ;
    ANTENNADIFFAREA 0.708600 ;
    PORT
      LAYER Metal2 ;
        RECT 786.520 1249.600 786.920 1250.000 ;
    END
  END psum_out[52]
  PIN psum_out[53]
    DIRECTION OUTPUT ;
    USE SIGNAL ;
    ANTENNADIFFAREA 0.708600 ;
    PORT
      LAYER Metal2 ;
        RECT 788.440 1249.600 788.840 1250.000 ;
    END
  END psum_out[53]
  PIN psum_out[54]
    DIRECTION OUTPUT ;
    USE SIGNAL ;
    ANTENNADIFFAREA 0.708600 ;
    PORT
      LAYER Metal2 ;
        RECT 790.360 1249.600 790.760 1250.000 ;
    END
  END psum_out[54]
  PIN psum_out[55]
    DIRECTION OUTPUT ;
    USE SIGNAL ;
    ANTENNADIFFAREA 0.708600 ;
    PORT
      LAYER Metal2 ;
        RECT 792.280 1249.600 792.680 1250.000 ;
    END
  END psum_out[55]
  PIN psum_out[56]
    DIRECTION OUTPUT ;
    USE SIGNAL ;
    ANTENNADIFFAREA 0.708600 ;
    PORT
      LAYER Metal2 ;
        RECT 794.200 1249.600 794.600 1250.000 ;
    END
  END psum_out[56]
  PIN psum_out[57]
    DIRECTION OUTPUT ;
    USE SIGNAL ;
    ANTENNADIFFAREA 0.708600 ;
    PORT
      LAYER Metal2 ;
        RECT 796.120 1249.600 796.520 1250.000 ;
    END
  END psum_out[57]
  PIN psum_out[58]
    DIRECTION OUTPUT ;
    USE SIGNAL ;
    ANTENNADIFFAREA 0.708600 ;
    PORT
      LAYER Metal2 ;
        RECT 798.040 1249.600 798.440 1250.000 ;
    END
  END psum_out[58]
  PIN psum_out[59]
    DIRECTION OUTPUT ;
    USE SIGNAL ;
    ANTENNADIFFAREA 0.708600 ;
    PORT
      LAYER Metal2 ;
        RECT 799.960 1249.600 800.360 1250.000 ;
    END
  END psum_out[59]
  PIN psum_out[5]
    DIRECTION OUTPUT ;
    USE SIGNAL ;
    ANTENNADIFFAREA 0.708600 ;
    PORT
      LAYER Metal2 ;
        RECT 696.280 1249.600 696.680 1250.000 ;
    END
  END psum_out[5]
  PIN psum_out[60]
    DIRECTION OUTPUT ;
    USE SIGNAL ;
    ANTENNADIFFAREA 0.708600 ;
    PORT
      LAYER Metal2 ;
        RECT 801.880 1249.600 802.280 1250.000 ;
    END
  END psum_out[60]
  PIN psum_out[61]
    DIRECTION OUTPUT ;
    USE SIGNAL ;
    ANTENNADIFFAREA 0.708600 ;
    PORT
      LAYER Metal2 ;
        RECT 803.800 1249.600 804.200 1250.000 ;
    END
  END psum_out[61]
  PIN psum_out[62]
    DIRECTION OUTPUT ;
    USE SIGNAL ;
    ANTENNADIFFAREA 0.708600 ;
    PORT
      LAYER Metal2 ;
        RECT 805.720 1249.600 806.120 1250.000 ;
    END
  END psum_out[62]
  PIN psum_out[63]
    DIRECTION OUTPUT ;
    USE SIGNAL ;
    ANTENNADIFFAREA 0.708600 ;
    PORT
      LAYER Metal2 ;
        RECT 807.640 1249.600 808.040 1250.000 ;
    END
  END psum_out[63]
  PIN psum_out[64]
    DIRECTION OUTPUT ;
    USE SIGNAL ;
    ANTENNADIFFAREA 0.708600 ;
    PORT
      LAYER Metal2 ;
        RECT 809.560 1249.600 809.960 1250.000 ;
    END
  END psum_out[64]
  PIN psum_out[65]
    DIRECTION OUTPUT ;
    USE SIGNAL ;
    ANTENNADIFFAREA 0.708600 ;
    PORT
      LAYER Metal2 ;
        RECT 811.480 1249.600 811.880 1250.000 ;
    END
  END psum_out[65]
  PIN psum_out[66]
    DIRECTION OUTPUT ;
    USE SIGNAL ;
    ANTENNADIFFAREA 0.708600 ;
    PORT
      LAYER Metal2 ;
        RECT 813.400 1249.600 813.800 1250.000 ;
    END
  END psum_out[66]
  PIN psum_out[67]
    DIRECTION OUTPUT ;
    USE SIGNAL ;
    ANTENNADIFFAREA 0.708600 ;
    PORT
      LAYER Metal2 ;
        RECT 815.320 1249.600 815.720 1250.000 ;
    END
  END psum_out[67]
  PIN psum_out[68]
    DIRECTION OUTPUT ;
    USE SIGNAL ;
    ANTENNADIFFAREA 0.708600 ;
    PORT
      LAYER Metal2 ;
        RECT 817.240 1249.600 817.640 1250.000 ;
    END
  END psum_out[68]
  PIN psum_out[69]
    DIRECTION OUTPUT ;
    USE SIGNAL ;
    ANTENNADIFFAREA 0.708600 ;
    PORT
      LAYER Metal2 ;
        RECT 819.160 1249.600 819.560 1250.000 ;
    END
  END psum_out[69]
  PIN psum_out[6]
    DIRECTION OUTPUT ;
    USE SIGNAL ;
    ANTENNADIFFAREA 0.708600 ;
    PORT
      LAYER Metal2 ;
        RECT 698.200 1249.600 698.600 1250.000 ;
    END
  END psum_out[6]
  PIN psum_out[70]
    DIRECTION OUTPUT ;
    USE SIGNAL ;
    ANTENNADIFFAREA 0.708600 ;
    PORT
      LAYER Metal2 ;
        RECT 821.080 1249.600 821.480 1250.000 ;
    END
  END psum_out[70]
  PIN psum_out[71]
    DIRECTION OUTPUT ;
    USE SIGNAL ;
    ANTENNADIFFAREA 0.708600 ;
    PORT
      LAYER Metal2 ;
        RECT 823.000 1249.600 823.400 1250.000 ;
    END
  END psum_out[71]
  PIN psum_out[72]
    DIRECTION OUTPUT ;
    USE SIGNAL ;
    ANTENNADIFFAREA 0.708600 ;
    PORT
      LAYER Metal2 ;
        RECT 824.920 1249.600 825.320 1250.000 ;
    END
  END psum_out[72]
  PIN psum_out[73]
    DIRECTION OUTPUT ;
    USE SIGNAL ;
    ANTENNADIFFAREA 0.708600 ;
    PORT
      LAYER Metal2 ;
        RECT 826.840 1249.600 827.240 1250.000 ;
    END
  END psum_out[73]
  PIN psum_out[74]
    DIRECTION OUTPUT ;
    USE SIGNAL ;
    ANTENNADIFFAREA 0.708600 ;
    PORT
      LAYER Metal2 ;
        RECT 828.760 1249.600 829.160 1250.000 ;
    END
  END psum_out[74]
  PIN psum_out[75]
    DIRECTION OUTPUT ;
    USE SIGNAL ;
    ANTENNADIFFAREA 0.708600 ;
    PORT
      LAYER Metal2 ;
        RECT 830.680 1249.600 831.080 1250.000 ;
    END
  END psum_out[75]
  PIN psum_out[76]
    DIRECTION OUTPUT ;
    USE SIGNAL ;
    ANTENNADIFFAREA 0.708600 ;
    PORT
      LAYER Metal2 ;
        RECT 832.600 1249.600 833.000 1250.000 ;
    END
  END psum_out[76]
  PIN psum_out[77]
    DIRECTION OUTPUT ;
    USE SIGNAL ;
    ANTENNADIFFAREA 0.708600 ;
    PORT
      LAYER Metal2 ;
        RECT 834.520 1249.600 834.920 1250.000 ;
    END
  END psum_out[77]
  PIN psum_out[78]
    DIRECTION OUTPUT ;
    USE SIGNAL ;
    ANTENNADIFFAREA 0.708600 ;
    PORT
      LAYER Metal2 ;
        RECT 836.440 1249.600 836.840 1250.000 ;
    END
  END psum_out[78]
  PIN psum_out[79]
    DIRECTION OUTPUT ;
    USE SIGNAL ;
    ANTENNADIFFAREA 0.708600 ;
    PORT
      LAYER Metal2 ;
        RECT 838.360 1249.600 838.760 1250.000 ;
    END
  END psum_out[79]
  PIN psum_out[7]
    DIRECTION OUTPUT ;
    USE SIGNAL ;
    ANTENNADIFFAREA 0.708600 ;
    PORT
      LAYER Metal2 ;
        RECT 700.120 1249.600 700.520 1250.000 ;
    END
  END psum_out[7]
  PIN psum_out[80]
    DIRECTION OUTPUT ;
    USE SIGNAL ;
    ANTENNADIFFAREA 0.708600 ;
    PORT
      LAYER Metal2 ;
        RECT 840.280 1249.600 840.680 1250.000 ;
    END
  END psum_out[80]
  PIN psum_out[81]
    DIRECTION OUTPUT ;
    USE SIGNAL ;
    ANTENNADIFFAREA 0.708600 ;
    PORT
      LAYER Metal2 ;
        RECT 842.200 1249.600 842.600 1250.000 ;
    END
  END psum_out[81]
  PIN psum_out[82]
    DIRECTION OUTPUT ;
    USE SIGNAL ;
    ANTENNADIFFAREA 0.708600 ;
    PORT
      LAYER Metal2 ;
        RECT 844.120 1249.600 844.520 1250.000 ;
    END
  END psum_out[82]
  PIN psum_out[83]
    DIRECTION OUTPUT ;
    USE SIGNAL ;
    ANTENNADIFFAREA 0.708600 ;
    PORT
      LAYER Metal2 ;
        RECT 846.040 1249.600 846.440 1250.000 ;
    END
  END psum_out[83]
  PIN psum_out[84]
    DIRECTION OUTPUT ;
    USE SIGNAL ;
    ANTENNADIFFAREA 0.708600 ;
    PORT
      LAYER Metal2 ;
        RECT 847.960 1249.600 848.360 1250.000 ;
    END
  END psum_out[84]
  PIN psum_out[85]
    DIRECTION OUTPUT ;
    USE SIGNAL ;
    ANTENNADIFFAREA 0.708600 ;
    PORT
      LAYER Metal2 ;
        RECT 849.880 1249.600 850.280 1250.000 ;
    END
  END psum_out[85]
  PIN psum_out[86]
    DIRECTION OUTPUT ;
    USE SIGNAL ;
    ANTENNADIFFAREA 0.708600 ;
    PORT
      LAYER Metal2 ;
        RECT 851.800 1249.600 852.200 1250.000 ;
    END
  END psum_out[86]
  PIN psum_out[87]
    DIRECTION OUTPUT ;
    USE SIGNAL ;
    ANTENNADIFFAREA 0.708600 ;
    PORT
      LAYER Metal2 ;
        RECT 853.720 1249.600 854.120 1250.000 ;
    END
  END psum_out[87]
  PIN psum_out[88]
    DIRECTION OUTPUT ;
    USE SIGNAL ;
    ANTENNADIFFAREA 0.708600 ;
    PORT
      LAYER Metal2 ;
        RECT 855.640 1249.600 856.040 1250.000 ;
    END
  END psum_out[88]
  PIN psum_out[89]
    DIRECTION OUTPUT ;
    USE SIGNAL ;
    ANTENNADIFFAREA 0.708600 ;
    PORT
      LAYER Metal2 ;
        RECT 857.560 1249.600 857.960 1250.000 ;
    END
  END psum_out[89]
  PIN psum_out[8]
    DIRECTION OUTPUT ;
    USE SIGNAL ;
    ANTENNADIFFAREA 0.708600 ;
    PORT
      LAYER Metal2 ;
        RECT 702.040 1249.600 702.440 1250.000 ;
    END
  END psum_out[8]
  PIN psum_out[90]
    DIRECTION OUTPUT ;
    USE SIGNAL ;
    ANTENNADIFFAREA 0.708600 ;
    PORT
      LAYER Metal2 ;
        RECT 859.480 1249.600 859.880 1250.000 ;
    END
  END psum_out[90]
  PIN psum_out[91]
    DIRECTION OUTPUT ;
    USE SIGNAL ;
    ANTENNADIFFAREA 0.708600 ;
    PORT
      LAYER Metal2 ;
        RECT 861.400 1249.600 861.800 1250.000 ;
    END
  END psum_out[91]
  PIN psum_out[92]
    DIRECTION OUTPUT ;
    USE SIGNAL ;
    ANTENNADIFFAREA 0.708600 ;
    PORT
      LAYER Metal2 ;
        RECT 863.320 1249.600 863.720 1250.000 ;
    END
  END psum_out[92]
  PIN psum_out[93]
    DIRECTION OUTPUT ;
    USE SIGNAL ;
    ANTENNADIFFAREA 0.708600 ;
    PORT
      LAYER Metal2 ;
        RECT 865.240 1249.600 865.640 1250.000 ;
    END
  END psum_out[93]
  PIN psum_out[94]
    DIRECTION OUTPUT ;
    USE SIGNAL ;
    ANTENNADIFFAREA 0.708600 ;
    PORT
      LAYER Metal2 ;
        RECT 867.160 1249.600 867.560 1250.000 ;
    END
  END psum_out[94]
  PIN psum_out[95]
    DIRECTION OUTPUT ;
    USE SIGNAL ;
    ANTENNADIFFAREA 0.708600 ;
    PORT
      LAYER Metal2 ;
        RECT 869.080 1249.600 869.480 1250.000 ;
    END
  END psum_out[95]
  PIN psum_out[96]
    DIRECTION OUTPUT ;
    USE SIGNAL ;
    ANTENNADIFFAREA 0.708600 ;
    PORT
      LAYER Metal2 ;
        RECT 871.000 1249.600 871.400 1250.000 ;
    END
  END psum_out[96]
  PIN psum_out[97]
    DIRECTION OUTPUT ;
    USE SIGNAL ;
    ANTENNADIFFAREA 0.708600 ;
    PORT
      LAYER Metal2 ;
        RECT 872.920 1249.600 873.320 1250.000 ;
    END
  END psum_out[97]
  PIN psum_out[98]
    DIRECTION OUTPUT ;
    USE SIGNAL ;
    ANTENNADIFFAREA 0.708600 ;
    PORT
      LAYER Metal2 ;
        RECT 874.840 1249.600 875.240 1250.000 ;
    END
  END psum_out[98]
  PIN psum_out[99]
    DIRECTION OUTPUT ;
    USE SIGNAL ;
    ANTENNADIFFAREA 0.708600 ;
    PORT
      LAYER Metal2 ;
        RECT 876.760 1249.600 877.160 1250.000 ;
    END
  END psum_out[99]
  PIN psum_out[9]
    DIRECTION OUTPUT ;
    USE SIGNAL ;
    ANTENNADIFFAREA 0.708600 ;
    PORT
      LAYER Metal2 ;
        RECT 703.960 1249.600 704.360 1250.000 ;
    END
  END psum_out[9]
  PIN rst_n
    DIRECTION INPUT ;
    USE SIGNAL ;
    ANTENNAGATEAREA 0.180700 ;
    PORT
      LAYER Metal3 ;
        RECT 0.000 33.820 0.400 34.220 ;
    END
  END rst_n
  PIN swap_weights
    DIRECTION INPUT ;
    USE SIGNAL ;
    ANTENNAGATEAREA 0.180700 ;
    PORT
      LAYER Metal3 ;
        RECT 0.000 104.380 0.400 104.780 ;
    END
  END swap_weights
  PIN weight_shift_en[0]
    DIRECTION INPUT ;
    USE SIGNAL ;
    ANTENNAGATEAREA 0.180700 ;
    PORT
      LAYER Metal3 ;
        RECT 0.000 69.100 0.400 69.500 ;
    END
  END weight_shift_en[0]
  PIN weight_shift_en[1]
    DIRECTION INPUT ;
    USE SIGNAL ;
    ANTENNAGATEAREA 0.180700 ;
    PORT
      LAYER Metal3 ;
        RECT 0.000 86.740 0.400 87.140 ;
    END
  END weight_shift_en[1]
  PIN weight_shift_in[0]
    DIRECTION INPUT ;
    USE SIGNAL ;
    ANTENNAGATEAREA 0.180700 ;
    PORT
      LAYER Metal2 ;
        RECT 72.280 1249.600 72.680 1250.000 ;
    END
  END weight_shift_in[0]
  PIN weight_shift_in[10]
    DIRECTION INPUT ;
    USE SIGNAL ;
    ANTENNAGATEAREA 0.180700 ;
    PORT
      LAYER Metal2 ;
        RECT 91.480 1249.600 91.880 1250.000 ;
    END
  END weight_shift_in[10]
  PIN weight_shift_in[11]
    DIRECTION INPUT ;
    USE SIGNAL ;
    ANTENNAGATEAREA 0.180700 ;
    PORT
      LAYER Metal2 ;
        RECT 93.400 1249.600 93.800 1250.000 ;
    END
  END weight_shift_in[11]
  PIN weight_shift_in[12]
    DIRECTION INPUT ;
    USE SIGNAL ;
    ANTENNAGATEAREA 0.180700 ;
    PORT
      LAYER Metal2 ;
        RECT 95.320 1249.600 95.720 1250.000 ;
    END
  END weight_shift_in[12]
  PIN weight_shift_in[13]
    DIRECTION INPUT ;
    USE SIGNAL ;
    ANTENNAGATEAREA 0.180700 ;
    PORT
      LAYER Metal2 ;
        RECT 97.240 1249.600 97.640 1250.000 ;
    END
  END weight_shift_in[13]
  PIN weight_shift_in[14]
    DIRECTION INPUT ;
    USE SIGNAL ;
    ANTENNAGATEAREA 0.180700 ;
    PORT
      LAYER Metal2 ;
        RECT 99.160 1249.600 99.560 1250.000 ;
    END
  END weight_shift_in[14]
  PIN weight_shift_in[15]
    DIRECTION INPUT ;
    USE SIGNAL ;
    ANTENNAGATEAREA 0.180700 ;
    PORT
      LAYER Metal2 ;
        RECT 101.080 1249.600 101.480 1250.000 ;
    END
  END weight_shift_in[15]
  PIN weight_shift_in[16]
    DIRECTION INPUT ;
    USE SIGNAL ;
    ANTENNAGATEAREA 0.180700 ;
    PORT
      LAYER Metal2 ;
        RECT 103.000 1249.600 103.400 1250.000 ;
    END
  END weight_shift_in[16]
  PIN weight_shift_in[17]
    DIRECTION INPUT ;
    USE SIGNAL ;
    ANTENNAGATEAREA 0.180700 ;
    PORT
      LAYER Metal2 ;
        RECT 104.920 1249.600 105.320 1250.000 ;
    END
  END weight_shift_in[17]
  PIN weight_shift_in[18]
    DIRECTION INPUT ;
    USE SIGNAL ;
    ANTENNAGATEAREA 0.180700 ;
    PORT
      LAYER Metal2 ;
        RECT 106.840 1249.600 107.240 1250.000 ;
    END
  END weight_shift_in[18]
  PIN weight_shift_in[19]
    DIRECTION INPUT ;
    USE SIGNAL ;
    ANTENNAGATEAREA 0.180700 ;
    PORT
      LAYER Metal2 ;
        RECT 108.760 1249.600 109.160 1250.000 ;
    END
  END weight_shift_in[19]
  PIN weight_shift_in[1]
    DIRECTION INPUT ;
    USE SIGNAL ;
    ANTENNAGATEAREA 0.180700 ;
    PORT
      LAYER Metal2 ;
        RECT 74.200 1249.600 74.600 1250.000 ;
    END
  END weight_shift_in[1]
  PIN weight_shift_in[20]
    DIRECTION INPUT ;
    USE SIGNAL ;
    ANTENNAGATEAREA 0.180700 ;
    PORT
      LAYER Metal2 ;
        RECT 110.680 1249.600 111.080 1250.000 ;
    END
  END weight_shift_in[20]
  PIN weight_shift_in[21]
    DIRECTION INPUT ;
    USE SIGNAL ;
    ANTENNAGATEAREA 0.180700 ;
    PORT
      LAYER Metal2 ;
        RECT 112.600 1249.600 113.000 1250.000 ;
    END
  END weight_shift_in[21]
  PIN weight_shift_in[22]
    DIRECTION INPUT ;
    USE SIGNAL ;
    ANTENNAGATEAREA 0.180700 ;
    PORT
      LAYER Metal2 ;
        RECT 114.520 1249.600 114.920 1250.000 ;
    END
  END weight_shift_in[22]
  PIN weight_shift_in[23]
    DIRECTION INPUT ;
    USE SIGNAL ;
    ANTENNAGATEAREA 0.180700 ;
    PORT
      LAYER Metal2 ;
        RECT 116.440 1249.600 116.840 1250.000 ;
    END
  END weight_shift_in[23]
  PIN weight_shift_in[24]
    DIRECTION INPUT ;
    USE SIGNAL ;
    ANTENNAGATEAREA 0.180700 ;
    PORT
      LAYER Metal2 ;
        RECT 118.360 1249.600 118.760 1250.000 ;
    END
  END weight_shift_in[24]
  PIN weight_shift_in[25]
    DIRECTION INPUT ;
    USE SIGNAL ;
    ANTENNAGATEAREA 0.180700 ;
    PORT
      LAYER Metal2 ;
        RECT 120.280 1249.600 120.680 1250.000 ;
    END
  END weight_shift_in[25]
  PIN weight_shift_in[26]
    DIRECTION INPUT ;
    USE SIGNAL ;
    ANTENNAGATEAREA 0.180700 ;
    PORT
      LAYER Metal2 ;
        RECT 122.200 1249.600 122.600 1250.000 ;
    END
  END weight_shift_in[26]
  PIN weight_shift_in[27]
    DIRECTION INPUT ;
    USE SIGNAL ;
    ANTENNAGATEAREA 0.180700 ;
    PORT
      LAYER Metal2 ;
        RECT 124.120 1249.600 124.520 1250.000 ;
    END
  END weight_shift_in[27]
  PIN weight_shift_in[28]
    DIRECTION INPUT ;
    USE SIGNAL ;
    ANTENNAGATEAREA 0.180700 ;
    PORT
      LAYER Metal2 ;
        RECT 126.040 1249.600 126.440 1250.000 ;
    END
  END weight_shift_in[28]
  PIN weight_shift_in[29]
    DIRECTION INPUT ;
    USE SIGNAL ;
    ANTENNAGATEAREA 0.180700 ;
    PORT
      LAYER Metal2 ;
        RECT 127.960 1249.600 128.360 1250.000 ;
    END
  END weight_shift_in[29]
  PIN weight_shift_in[2]
    DIRECTION INPUT ;
    USE SIGNAL ;
    ANTENNAGATEAREA 0.180700 ;
    PORT
      LAYER Metal2 ;
        RECT 76.120 1249.600 76.520 1250.000 ;
    END
  END weight_shift_in[2]
  PIN weight_shift_in[30]
    DIRECTION INPUT ;
    USE SIGNAL ;
    ANTENNAGATEAREA 0.180700 ;
    PORT
      LAYER Metal2 ;
        RECT 129.880 1249.600 130.280 1250.000 ;
    END
  END weight_shift_in[30]
  PIN weight_shift_in[31]
    DIRECTION INPUT ;
    USE SIGNAL ;
    ANTENNAGATEAREA 0.180700 ;
    PORT
      LAYER Metal2 ;
        RECT 131.800 1249.600 132.200 1250.000 ;
    END
  END weight_shift_in[31]
  PIN weight_shift_in[32]
    DIRECTION INPUT ;
    USE SIGNAL ;
    ANTENNAGATEAREA 0.180700 ;
    PORT
      LAYER Metal2 ;
        RECT 133.720 1249.600 134.120 1250.000 ;
    END
  END weight_shift_in[32]
  PIN weight_shift_in[33]
    DIRECTION INPUT ;
    USE SIGNAL ;
    ANTENNAGATEAREA 0.180700 ;
    PORT
      LAYER Metal2 ;
        RECT 135.640 1249.600 136.040 1250.000 ;
    END
  END weight_shift_in[33]
  PIN weight_shift_in[34]
    DIRECTION INPUT ;
    USE SIGNAL ;
    ANTENNAGATEAREA 0.180700 ;
    PORT
      LAYER Metal2 ;
        RECT 137.560 1249.600 137.960 1250.000 ;
    END
  END weight_shift_in[34]
  PIN weight_shift_in[35]
    DIRECTION INPUT ;
    USE SIGNAL ;
    ANTENNAGATEAREA 0.180700 ;
    PORT
      LAYER Metal2 ;
        RECT 139.480 1249.600 139.880 1250.000 ;
    END
  END weight_shift_in[35]
  PIN weight_shift_in[36]
    DIRECTION INPUT ;
    USE SIGNAL ;
    ANTENNAGATEAREA 0.180700 ;
    PORT
      LAYER Metal2 ;
        RECT 141.400 1249.600 141.800 1250.000 ;
    END
  END weight_shift_in[36]
  PIN weight_shift_in[37]
    DIRECTION INPUT ;
    USE SIGNAL ;
    ANTENNAGATEAREA 0.180700 ;
    PORT
      LAYER Metal2 ;
        RECT 143.320 1249.600 143.720 1250.000 ;
    END
  END weight_shift_in[37]
  PIN weight_shift_in[38]
    DIRECTION INPUT ;
    USE SIGNAL ;
    ANTENNAGATEAREA 0.180700 ;
    PORT
      LAYER Metal2 ;
        RECT 145.240 1249.600 145.640 1250.000 ;
    END
  END weight_shift_in[38]
  PIN weight_shift_in[39]
    DIRECTION INPUT ;
    USE SIGNAL ;
    ANTENNAGATEAREA 0.180700 ;
    PORT
      LAYER Metal2 ;
        RECT 147.160 1249.600 147.560 1250.000 ;
    END
  END weight_shift_in[39]
  PIN weight_shift_in[3]
    DIRECTION INPUT ;
    USE SIGNAL ;
    ANTENNAGATEAREA 0.180700 ;
    PORT
      LAYER Metal2 ;
        RECT 78.040 1249.600 78.440 1250.000 ;
    END
  END weight_shift_in[3]
  PIN weight_shift_in[40]
    DIRECTION INPUT ;
    USE SIGNAL ;
    ANTENNAGATEAREA 0.180700 ;
    PORT
      LAYER Metal2 ;
        RECT 149.080 1249.600 149.480 1250.000 ;
    END
  END weight_shift_in[40]
  PIN weight_shift_in[41]
    DIRECTION INPUT ;
    USE SIGNAL ;
    ANTENNAGATEAREA 0.180700 ;
    PORT
      LAYER Metal2 ;
        RECT 151.000 1249.600 151.400 1250.000 ;
    END
  END weight_shift_in[41]
  PIN weight_shift_in[42]
    DIRECTION INPUT ;
    USE SIGNAL ;
    ANTENNAGATEAREA 0.180700 ;
    PORT
      LAYER Metal2 ;
        RECT 152.920 1249.600 153.320 1250.000 ;
    END
  END weight_shift_in[42]
  PIN weight_shift_in[43]
    DIRECTION INPUT ;
    USE SIGNAL ;
    ANTENNAGATEAREA 0.180700 ;
    PORT
      LAYER Metal2 ;
        RECT 154.840 1249.600 155.240 1250.000 ;
    END
  END weight_shift_in[43]
  PIN weight_shift_in[44]
    DIRECTION INPUT ;
    USE SIGNAL ;
    ANTENNAGATEAREA 0.180700 ;
    PORT
      LAYER Metal2 ;
        RECT 156.760 1249.600 157.160 1250.000 ;
    END
  END weight_shift_in[44]
  PIN weight_shift_in[45]
    DIRECTION INPUT ;
    USE SIGNAL ;
    ANTENNAGATEAREA 0.180700 ;
    PORT
      LAYER Metal2 ;
        RECT 158.680 1249.600 159.080 1250.000 ;
    END
  END weight_shift_in[45]
  PIN weight_shift_in[46]
    DIRECTION INPUT ;
    USE SIGNAL ;
    ANTENNAGATEAREA 0.180700 ;
    PORT
      LAYER Metal2 ;
        RECT 160.600 1249.600 161.000 1250.000 ;
    END
  END weight_shift_in[46]
  PIN weight_shift_in[47]
    DIRECTION INPUT ;
    USE SIGNAL ;
    ANTENNAGATEAREA 0.180700 ;
    PORT
      LAYER Metal2 ;
        RECT 162.520 1249.600 162.920 1250.000 ;
    END
  END weight_shift_in[47]
  PIN weight_shift_in[48]
    DIRECTION INPUT ;
    USE SIGNAL ;
    ANTENNAGATEAREA 0.180700 ;
    PORT
      LAYER Metal2 ;
        RECT 164.440 1249.600 164.840 1250.000 ;
    END
  END weight_shift_in[48]
  PIN weight_shift_in[49]
    DIRECTION INPUT ;
    USE SIGNAL ;
    ANTENNAGATEAREA 0.180700 ;
    PORT
      LAYER Metal2 ;
        RECT 166.360 1249.600 166.760 1250.000 ;
    END
  END weight_shift_in[49]
  PIN weight_shift_in[4]
    DIRECTION INPUT ;
    USE SIGNAL ;
    ANTENNAGATEAREA 0.180700 ;
    PORT
      LAYER Metal2 ;
        RECT 79.960 1249.600 80.360 1250.000 ;
    END
  END weight_shift_in[4]
  PIN weight_shift_in[50]
    DIRECTION INPUT ;
    USE SIGNAL ;
    ANTENNAGATEAREA 0.180700 ;
    PORT
      LAYER Metal2 ;
        RECT 168.280 1249.600 168.680 1250.000 ;
    END
  END weight_shift_in[50]
  PIN weight_shift_in[51]
    DIRECTION INPUT ;
    USE SIGNAL ;
    ANTENNAGATEAREA 0.180700 ;
    PORT
      LAYER Metal2 ;
        RECT 170.200 1249.600 170.600 1250.000 ;
    END
  END weight_shift_in[51]
  PIN weight_shift_in[52]
    DIRECTION INPUT ;
    USE SIGNAL ;
    ANTENNAGATEAREA 0.180700 ;
    PORT
      LAYER Metal2 ;
        RECT 172.120 1249.600 172.520 1250.000 ;
    END
  END weight_shift_in[52]
  PIN weight_shift_in[53]
    DIRECTION INPUT ;
    USE SIGNAL ;
    ANTENNAGATEAREA 0.180700 ;
    PORT
      LAYER Metal2 ;
        RECT 174.040 1249.600 174.440 1250.000 ;
    END
  END weight_shift_in[53]
  PIN weight_shift_in[54]
    DIRECTION INPUT ;
    USE SIGNAL ;
    ANTENNAGATEAREA 0.180700 ;
    PORT
      LAYER Metal2 ;
        RECT 175.960 1249.600 176.360 1250.000 ;
    END
  END weight_shift_in[54]
  PIN weight_shift_in[55]
    DIRECTION INPUT ;
    USE SIGNAL ;
    ANTENNAGATEAREA 0.180700 ;
    PORT
      LAYER Metal2 ;
        RECT 177.880 1249.600 178.280 1250.000 ;
    END
  END weight_shift_in[55]
  PIN weight_shift_in[56]
    DIRECTION INPUT ;
    USE SIGNAL ;
    ANTENNAGATEAREA 0.180700 ;
    PORT
      LAYER Metal2 ;
        RECT 179.800 1249.600 180.200 1250.000 ;
    END
  END weight_shift_in[56]
  PIN weight_shift_in[57]
    DIRECTION INPUT ;
    USE SIGNAL ;
    ANTENNAGATEAREA 0.180700 ;
    PORT
      LAYER Metal2 ;
        RECT 181.720 1249.600 182.120 1250.000 ;
    END
  END weight_shift_in[57]
  PIN weight_shift_in[58]
    DIRECTION INPUT ;
    USE SIGNAL ;
    ANTENNAGATEAREA 0.180700 ;
    PORT
      LAYER Metal2 ;
        RECT 183.640 1249.600 184.040 1250.000 ;
    END
  END weight_shift_in[58]
  PIN weight_shift_in[59]
    DIRECTION INPUT ;
    USE SIGNAL ;
    ANTENNAGATEAREA 0.180700 ;
    PORT
      LAYER Metal2 ;
        RECT 185.560 1249.600 185.960 1250.000 ;
    END
  END weight_shift_in[59]
  PIN weight_shift_in[5]
    DIRECTION INPUT ;
    USE SIGNAL ;
    ANTENNAGATEAREA 0.180700 ;
    PORT
      LAYER Metal2 ;
        RECT 81.880 1249.600 82.280 1250.000 ;
    END
  END weight_shift_in[5]
  PIN weight_shift_in[60]
    DIRECTION INPUT ;
    USE SIGNAL ;
    ANTENNAGATEAREA 0.180700 ;
    PORT
      LAYER Metal2 ;
        RECT 187.480 1249.600 187.880 1250.000 ;
    END
  END weight_shift_in[60]
  PIN weight_shift_in[61]
    DIRECTION INPUT ;
    USE SIGNAL ;
    ANTENNAGATEAREA 0.180700 ;
    PORT
      LAYER Metal2 ;
        RECT 189.400 1249.600 189.800 1250.000 ;
    END
  END weight_shift_in[61]
  PIN weight_shift_in[62]
    DIRECTION INPUT ;
    USE SIGNAL ;
    ANTENNAGATEAREA 0.180700 ;
    PORT
      LAYER Metal2 ;
        RECT 191.320 1249.600 191.720 1250.000 ;
    END
  END weight_shift_in[62]
  PIN weight_shift_in[63]
    DIRECTION INPUT ;
    USE SIGNAL ;
    ANTENNAGATEAREA 0.180700 ;
    PORT
      LAYER Metal2 ;
        RECT 193.240 1249.600 193.640 1250.000 ;
    END
  END weight_shift_in[63]
  PIN weight_shift_in[6]
    DIRECTION INPUT ;
    USE SIGNAL ;
    ANTENNAGATEAREA 0.180700 ;
    PORT
      LAYER Metal2 ;
        RECT 83.800 1249.600 84.200 1250.000 ;
    END
  END weight_shift_in[6]
  PIN weight_shift_in[7]
    DIRECTION INPUT ;
    USE SIGNAL ;
    ANTENNAGATEAREA 0.180700 ;
    PORT
      LAYER Metal2 ;
        RECT 85.720 1249.600 86.120 1250.000 ;
    END
  END weight_shift_in[7]
  PIN weight_shift_in[8]
    DIRECTION INPUT ;
    USE SIGNAL ;
    ANTENNAGATEAREA 0.180700 ;
    PORT
      LAYER Metal2 ;
        RECT 87.640 1249.600 88.040 1250.000 ;
    END
  END weight_shift_in[8]
  PIN weight_shift_in[9]
    DIRECTION INPUT ;
    USE SIGNAL ;
    ANTENNAGATEAREA 0.180700 ;
    PORT
      LAYER Metal2 ;
        RECT 89.560 1249.600 89.960 1250.000 ;
    END
  END weight_shift_in[9]
  OBS
      LAYER GatPoly ;
        RECT 5.760 14.970 1244.160 1232.430 ;
      LAYER Metal1 ;
        RECT 5.760 14.900 1244.160 1232.500 ;
      LAYER Metal2 ;
        RECT 1.335 1249.390 72.070 1249.645 ;
        RECT 72.890 1249.390 73.990 1249.645 ;
        RECT 74.810 1249.390 75.910 1249.645 ;
        RECT 76.730 1249.390 77.830 1249.645 ;
        RECT 78.650 1249.390 79.750 1249.645 ;
        RECT 80.570 1249.390 81.670 1249.645 ;
        RECT 82.490 1249.390 83.590 1249.645 ;
        RECT 84.410 1249.390 85.510 1249.645 ;
        RECT 86.330 1249.390 87.430 1249.645 ;
        RECT 88.250 1249.390 89.350 1249.645 ;
        RECT 90.170 1249.390 91.270 1249.645 ;
        RECT 92.090 1249.390 93.190 1249.645 ;
        RECT 94.010 1249.390 95.110 1249.645 ;
        RECT 95.930 1249.390 97.030 1249.645 ;
        RECT 97.850 1249.390 98.950 1249.645 ;
        RECT 99.770 1249.390 100.870 1249.645 ;
        RECT 101.690 1249.390 102.790 1249.645 ;
        RECT 103.610 1249.390 104.710 1249.645 ;
        RECT 105.530 1249.390 106.630 1249.645 ;
        RECT 107.450 1249.390 108.550 1249.645 ;
        RECT 109.370 1249.390 110.470 1249.645 ;
        RECT 111.290 1249.390 112.390 1249.645 ;
        RECT 113.210 1249.390 114.310 1249.645 ;
        RECT 115.130 1249.390 116.230 1249.645 ;
        RECT 117.050 1249.390 118.150 1249.645 ;
        RECT 118.970 1249.390 120.070 1249.645 ;
        RECT 120.890 1249.390 121.990 1249.645 ;
        RECT 122.810 1249.390 123.910 1249.645 ;
        RECT 124.730 1249.390 125.830 1249.645 ;
        RECT 126.650 1249.390 127.750 1249.645 ;
        RECT 128.570 1249.390 129.670 1249.645 ;
        RECT 130.490 1249.390 131.590 1249.645 ;
        RECT 132.410 1249.390 133.510 1249.645 ;
        RECT 134.330 1249.390 135.430 1249.645 ;
        RECT 136.250 1249.390 137.350 1249.645 ;
        RECT 138.170 1249.390 139.270 1249.645 ;
        RECT 140.090 1249.390 141.190 1249.645 ;
        RECT 142.010 1249.390 143.110 1249.645 ;
        RECT 143.930 1249.390 145.030 1249.645 ;
        RECT 145.850 1249.390 146.950 1249.645 ;
        RECT 147.770 1249.390 148.870 1249.645 ;
        RECT 149.690 1249.390 150.790 1249.645 ;
        RECT 151.610 1249.390 152.710 1249.645 ;
        RECT 153.530 1249.390 154.630 1249.645 ;
        RECT 155.450 1249.390 156.550 1249.645 ;
        RECT 157.370 1249.390 158.470 1249.645 ;
        RECT 159.290 1249.390 160.390 1249.645 ;
        RECT 161.210 1249.390 162.310 1249.645 ;
        RECT 163.130 1249.390 164.230 1249.645 ;
        RECT 165.050 1249.390 166.150 1249.645 ;
        RECT 166.970 1249.390 168.070 1249.645 ;
        RECT 168.890 1249.390 169.990 1249.645 ;
        RECT 170.810 1249.390 171.910 1249.645 ;
        RECT 172.730 1249.390 173.830 1249.645 ;
        RECT 174.650 1249.390 175.750 1249.645 ;
        RECT 176.570 1249.390 177.670 1249.645 ;
        RECT 178.490 1249.390 179.590 1249.645 ;
        RECT 180.410 1249.390 181.510 1249.645 ;
        RECT 182.330 1249.390 183.430 1249.645 ;
        RECT 184.250 1249.390 185.350 1249.645 ;
        RECT 186.170 1249.390 187.270 1249.645 ;
        RECT 188.090 1249.390 189.190 1249.645 ;
        RECT 190.010 1249.390 191.110 1249.645 ;
        RECT 191.930 1249.390 193.030 1249.645 ;
        RECT 193.850 1249.390 194.950 1249.645 ;
        RECT 195.770 1249.390 196.870 1249.645 ;
        RECT 197.690 1249.390 198.790 1249.645 ;
        RECT 199.610 1249.390 200.710 1249.645 ;
        RECT 201.530 1249.390 202.630 1249.645 ;
        RECT 203.450 1249.390 204.550 1249.645 ;
        RECT 205.370 1249.390 206.470 1249.645 ;
        RECT 207.290 1249.390 208.390 1249.645 ;
        RECT 209.210 1249.390 210.310 1249.645 ;
        RECT 211.130 1249.390 212.230 1249.645 ;
        RECT 213.050 1249.390 214.150 1249.645 ;
        RECT 214.970 1249.390 216.070 1249.645 ;
        RECT 216.890 1249.390 217.990 1249.645 ;
        RECT 218.810 1249.390 219.910 1249.645 ;
        RECT 220.730 1249.390 221.830 1249.645 ;
        RECT 222.650 1249.390 223.750 1249.645 ;
        RECT 224.570 1249.390 225.670 1249.645 ;
        RECT 226.490 1249.390 227.590 1249.645 ;
        RECT 228.410 1249.390 229.510 1249.645 ;
        RECT 230.330 1249.390 231.430 1249.645 ;
        RECT 232.250 1249.390 233.350 1249.645 ;
        RECT 234.170 1249.390 235.270 1249.645 ;
        RECT 236.090 1249.390 237.190 1249.645 ;
        RECT 238.010 1249.390 239.110 1249.645 ;
        RECT 239.930 1249.390 241.030 1249.645 ;
        RECT 241.850 1249.390 242.950 1249.645 ;
        RECT 243.770 1249.390 244.870 1249.645 ;
        RECT 245.690 1249.390 246.790 1249.645 ;
        RECT 247.610 1249.390 248.710 1249.645 ;
        RECT 249.530 1249.390 250.630 1249.645 ;
        RECT 251.450 1249.390 252.550 1249.645 ;
        RECT 253.370 1249.390 254.470 1249.645 ;
        RECT 255.290 1249.390 256.390 1249.645 ;
        RECT 257.210 1249.390 258.310 1249.645 ;
        RECT 259.130 1249.390 260.230 1249.645 ;
        RECT 261.050 1249.390 262.150 1249.645 ;
        RECT 262.970 1249.390 264.070 1249.645 ;
        RECT 264.890 1249.390 265.990 1249.645 ;
        RECT 266.810 1249.390 267.910 1249.645 ;
        RECT 268.730 1249.390 269.830 1249.645 ;
        RECT 270.650 1249.390 271.750 1249.645 ;
        RECT 272.570 1249.390 273.670 1249.645 ;
        RECT 274.490 1249.390 275.590 1249.645 ;
        RECT 276.410 1249.390 277.510 1249.645 ;
        RECT 278.330 1249.390 279.430 1249.645 ;
        RECT 280.250 1249.390 281.350 1249.645 ;
        RECT 282.170 1249.390 283.270 1249.645 ;
        RECT 284.090 1249.390 285.190 1249.645 ;
        RECT 286.010 1249.390 287.110 1249.645 ;
        RECT 287.930 1249.390 289.030 1249.645 ;
        RECT 289.850 1249.390 290.950 1249.645 ;
        RECT 291.770 1249.390 292.870 1249.645 ;
        RECT 293.690 1249.390 294.790 1249.645 ;
        RECT 295.610 1249.390 296.710 1249.645 ;
        RECT 297.530 1249.390 298.630 1249.645 ;
        RECT 299.450 1249.390 300.550 1249.645 ;
        RECT 301.370 1249.390 302.470 1249.645 ;
        RECT 303.290 1249.390 304.390 1249.645 ;
        RECT 305.210 1249.390 306.310 1249.645 ;
        RECT 307.130 1249.390 308.230 1249.645 ;
        RECT 309.050 1249.390 310.150 1249.645 ;
        RECT 310.970 1249.390 312.070 1249.645 ;
        RECT 312.890 1249.390 313.990 1249.645 ;
        RECT 314.810 1249.390 315.910 1249.645 ;
        RECT 316.730 1249.390 317.830 1249.645 ;
        RECT 318.650 1249.390 319.750 1249.645 ;
        RECT 320.570 1249.390 321.670 1249.645 ;
        RECT 322.490 1249.390 323.590 1249.645 ;
        RECT 324.410 1249.390 325.510 1249.645 ;
        RECT 326.330 1249.390 327.430 1249.645 ;
        RECT 328.250 1249.390 329.350 1249.645 ;
        RECT 330.170 1249.390 331.270 1249.645 ;
        RECT 332.090 1249.390 333.190 1249.645 ;
        RECT 334.010 1249.390 335.110 1249.645 ;
        RECT 335.930 1249.390 337.030 1249.645 ;
        RECT 337.850 1249.390 338.950 1249.645 ;
        RECT 339.770 1249.390 340.870 1249.645 ;
        RECT 341.690 1249.390 342.790 1249.645 ;
        RECT 343.610 1249.390 344.710 1249.645 ;
        RECT 345.530 1249.390 346.630 1249.645 ;
        RECT 347.450 1249.390 348.550 1249.645 ;
        RECT 349.370 1249.390 350.470 1249.645 ;
        RECT 351.290 1249.390 352.390 1249.645 ;
        RECT 353.210 1249.390 354.310 1249.645 ;
        RECT 355.130 1249.390 356.230 1249.645 ;
        RECT 357.050 1249.390 358.150 1249.645 ;
        RECT 358.970 1249.390 360.070 1249.645 ;
        RECT 360.890 1249.390 361.990 1249.645 ;
        RECT 362.810 1249.390 363.910 1249.645 ;
        RECT 364.730 1249.390 365.830 1249.645 ;
        RECT 366.650 1249.390 367.750 1249.645 ;
        RECT 368.570 1249.390 369.670 1249.645 ;
        RECT 370.490 1249.390 371.590 1249.645 ;
        RECT 372.410 1249.390 373.510 1249.645 ;
        RECT 374.330 1249.390 375.430 1249.645 ;
        RECT 376.250 1249.390 377.350 1249.645 ;
        RECT 378.170 1249.390 379.270 1249.645 ;
        RECT 380.090 1249.390 381.190 1249.645 ;
        RECT 382.010 1249.390 383.110 1249.645 ;
        RECT 383.930 1249.390 385.030 1249.645 ;
        RECT 385.850 1249.390 386.950 1249.645 ;
        RECT 387.770 1249.390 388.870 1249.645 ;
        RECT 389.690 1249.390 390.790 1249.645 ;
        RECT 391.610 1249.390 392.710 1249.645 ;
        RECT 393.530 1249.390 394.630 1249.645 ;
        RECT 395.450 1249.390 396.550 1249.645 ;
        RECT 397.370 1249.390 398.470 1249.645 ;
        RECT 399.290 1249.390 400.390 1249.645 ;
        RECT 401.210 1249.390 402.310 1249.645 ;
        RECT 403.130 1249.390 404.230 1249.645 ;
        RECT 405.050 1249.390 406.150 1249.645 ;
        RECT 406.970 1249.390 408.070 1249.645 ;
        RECT 408.890 1249.390 409.990 1249.645 ;
        RECT 410.810 1249.390 411.910 1249.645 ;
        RECT 412.730 1249.390 413.830 1249.645 ;
        RECT 414.650 1249.390 415.750 1249.645 ;
        RECT 416.570 1249.390 417.670 1249.645 ;
        RECT 418.490 1249.390 419.590 1249.645 ;
        RECT 420.410 1249.390 421.510 1249.645 ;
        RECT 422.330 1249.390 423.430 1249.645 ;
        RECT 424.250 1249.390 425.350 1249.645 ;
        RECT 426.170 1249.390 427.270 1249.645 ;
        RECT 428.090 1249.390 429.190 1249.645 ;
        RECT 430.010 1249.390 431.110 1249.645 ;
        RECT 431.930 1249.390 433.030 1249.645 ;
        RECT 433.850 1249.390 434.950 1249.645 ;
        RECT 435.770 1249.390 436.870 1249.645 ;
        RECT 437.690 1249.390 438.790 1249.645 ;
        RECT 439.610 1249.390 440.710 1249.645 ;
        RECT 441.530 1249.390 442.630 1249.645 ;
        RECT 443.450 1249.390 444.550 1249.645 ;
        RECT 445.370 1249.390 446.470 1249.645 ;
        RECT 447.290 1249.390 448.390 1249.645 ;
        RECT 449.210 1249.390 450.310 1249.645 ;
        RECT 451.130 1249.390 452.230 1249.645 ;
        RECT 453.050 1249.390 454.150 1249.645 ;
        RECT 454.970 1249.390 456.070 1249.645 ;
        RECT 456.890 1249.390 457.990 1249.645 ;
        RECT 458.810 1249.390 459.910 1249.645 ;
        RECT 460.730 1249.390 461.830 1249.645 ;
        RECT 462.650 1249.390 463.750 1249.645 ;
        RECT 464.570 1249.390 465.670 1249.645 ;
        RECT 466.490 1249.390 467.590 1249.645 ;
        RECT 468.410 1249.390 469.510 1249.645 ;
        RECT 470.330 1249.390 471.430 1249.645 ;
        RECT 472.250 1249.390 473.350 1249.645 ;
        RECT 474.170 1249.390 475.270 1249.645 ;
        RECT 476.090 1249.390 477.190 1249.645 ;
        RECT 478.010 1249.390 479.110 1249.645 ;
        RECT 479.930 1249.390 481.030 1249.645 ;
        RECT 481.850 1249.390 482.950 1249.645 ;
        RECT 483.770 1249.390 484.870 1249.645 ;
        RECT 485.690 1249.390 486.790 1249.645 ;
        RECT 487.610 1249.390 488.710 1249.645 ;
        RECT 489.530 1249.390 490.630 1249.645 ;
        RECT 491.450 1249.390 492.550 1249.645 ;
        RECT 493.370 1249.390 494.470 1249.645 ;
        RECT 495.290 1249.390 496.390 1249.645 ;
        RECT 497.210 1249.390 498.310 1249.645 ;
        RECT 499.130 1249.390 500.230 1249.645 ;
        RECT 501.050 1249.390 502.150 1249.645 ;
        RECT 502.970 1249.390 504.070 1249.645 ;
        RECT 504.890 1249.390 505.990 1249.645 ;
        RECT 506.810 1249.390 507.910 1249.645 ;
        RECT 508.730 1249.390 509.830 1249.645 ;
        RECT 510.650 1249.390 511.750 1249.645 ;
        RECT 512.570 1249.390 513.670 1249.645 ;
        RECT 514.490 1249.390 515.590 1249.645 ;
        RECT 516.410 1249.390 517.510 1249.645 ;
        RECT 518.330 1249.390 519.430 1249.645 ;
        RECT 520.250 1249.390 521.350 1249.645 ;
        RECT 522.170 1249.390 523.270 1249.645 ;
        RECT 524.090 1249.390 525.190 1249.645 ;
        RECT 526.010 1249.390 527.110 1249.645 ;
        RECT 527.930 1249.390 529.030 1249.645 ;
        RECT 529.850 1249.390 530.950 1249.645 ;
        RECT 531.770 1249.390 532.870 1249.645 ;
        RECT 533.690 1249.390 534.790 1249.645 ;
        RECT 535.610 1249.390 536.710 1249.645 ;
        RECT 537.530 1249.390 538.630 1249.645 ;
        RECT 539.450 1249.390 540.550 1249.645 ;
        RECT 541.370 1249.390 542.470 1249.645 ;
        RECT 543.290 1249.390 544.390 1249.645 ;
        RECT 545.210 1249.390 546.310 1249.645 ;
        RECT 547.130 1249.390 548.230 1249.645 ;
        RECT 549.050 1249.390 550.150 1249.645 ;
        RECT 550.970 1249.390 552.070 1249.645 ;
        RECT 552.890 1249.390 553.990 1249.645 ;
        RECT 554.810 1249.390 555.910 1249.645 ;
        RECT 556.730 1249.390 557.830 1249.645 ;
        RECT 558.650 1249.390 559.750 1249.645 ;
        RECT 560.570 1249.390 561.670 1249.645 ;
        RECT 562.490 1249.390 563.590 1249.645 ;
        RECT 564.410 1249.390 565.510 1249.645 ;
        RECT 566.330 1249.390 567.430 1249.645 ;
        RECT 568.250 1249.390 569.350 1249.645 ;
        RECT 570.170 1249.390 571.270 1249.645 ;
        RECT 572.090 1249.390 573.190 1249.645 ;
        RECT 574.010 1249.390 575.110 1249.645 ;
        RECT 575.930 1249.390 577.030 1249.645 ;
        RECT 577.850 1249.390 578.950 1249.645 ;
        RECT 579.770 1249.390 580.870 1249.645 ;
        RECT 581.690 1249.390 582.790 1249.645 ;
        RECT 583.610 1249.390 584.710 1249.645 ;
        RECT 585.530 1249.390 586.630 1249.645 ;
        RECT 587.450 1249.390 588.550 1249.645 ;
        RECT 589.370 1249.390 590.470 1249.645 ;
        RECT 591.290 1249.390 592.390 1249.645 ;
        RECT 593.210 1249.390 594.310 1249.645 ;
        RECT 595.130 1249.390 596.230 1249.645 ;
        RECT 597.050 1249.390 598.150 1249.645 ;
        RECT 598.970 1249.390 600.070 1249.645 ;
        RECT 600.890 1249.390 601.990 1249.645 ;
        RECT 602.810 1249.390 603.910 1249.645 ;
        RECT 604.730 1249.390 605.830 1249.645 ;
        RECT 606.650 1249.390 607.750 1249.645 ;
        RECT 608.570 1249.390 609.670 1249.645 ;
        RECT 610.490 1249.390 611.590 1249.645 ;
        RECT 612.410 1249.390 613.510 1249.645 ;
        RECT 614.330 1249.390 615.430 1249.645 ;
        RECT 616.250 1249.390 617.350 1249.645 ;
        RECT 618.170 1249.390 619.270 1249.645 ;
        RECT 620.090 1249.390 621.190 1249.645 ;
        RECT 622.010 1249.390 623.110 1249.645 ;
        RECT 623.930 1249.390 625.030 1249.645 ;
        RECT 625.850 1249.390 626.950 1249.645 ;
        RECT 627.770 1249.390 628.870 1249.645 ;
        RECT 629.690 1249.390 630.790 1249.645 ;
        RECT 631.610 1249.390 632.710 1249.645 ;
        RECT 633.530 1249.390 634.630 1249.645 ;
        RECT 635.450 1249.390 636.550 1249.645 ;
        RECT 637.370 1249.390 638.470 1249.645 ;
        RECT 639.290 1249.390 640.390 1249.645 ;
        RECT 641.210 1249.390 642.310 1249.645 ;
        RECT 643.130 1249.390 644.230 1249.645 ;
        RECT 645.050 1249.390 646.150 1249.645 ;
        RECT 646.970 1249.390 648.070 1249.645 ;
        RECT 648.890 1249.390 649.990 1249.645 ;
        RECT 650.810 1249.390 651.910 1249.645 ;
        RECT 652.730 1249.390 653.830 1249.645 ;
        RECT 654.650 1249.390 655.750 1249.645 ;
        RECT 656.570 1249.390 657.670 1249.645 ;
        RECT 658.490 1249.390 659.590 1249.645 ;
        RECT 660.410 1249.390 661.510 1249.645 ;
        RECT 662.330 1249.390 663.430 1249.645 ;
        RECT 664.250 1249.390 665.350 1249.645 ;
        RECT 666.170 1249.390 667.270 1249.645 ;
        RECT 668.090 1249.390 669.190 1249.645 ;
        RECT 670.010 1249.390 671.110 1249.645 ;
        RECT 671.930 1249.390 673.030 1249.645 ;
        RECT 673.850 1249.390 674.950 1249.645 ;
        RECT 675.770 1249.390 676.870 1249.645 ;
        RECT 677.690 1249.390 678.790 1249.645 ;
        RECT 679.610 1249.390 680.710 1249.645 ;
        RECT 681.530 1249.390 682.630 1249.645 ;
        RECT 683.450 1249.390 684.550 1249.645 ;
        RECT 685.370 1249.390 686.470 1249.645 ;
        RECT 687.290 1249.390 688.390 1249.645 ;
        RECT 689.210 1249.390 690.310 1249.645 ;
        RECT 691.130 1249.390 692.230 1249.645 ;
        RECT 693.050 1249.390 694.150 1249.645 ;
        RECT 694.970 1249.390 696.070 1249.645 ;
        RECT 696.890 1249.390 697.990 1249.645 ;
        RECT 698.810 1249.390 699.910 1249.645 ;
        RECT 700.730 1249.390 701.830 1249.645 ;
        RECT 702.650 1249.390 703.750 1249.645 ;
        RECT 704.570 1249.390 705.670 1249.645 ;
        RECT 706.490 1249.390 707.590 1249.645 ;
        RECT 708.410 1249.390 709.510 1249.645 ;
        RECT 710.330 1249.390 711.430 1249.645 ;
        RECT 712.250 1249.390 713.350 1249.645 ;
        RECT 714.170 1249.390 715.270 1249.645 ;
        RECT 716.090 1249.390 717.190 1249.645 ;
        RECT 718.010 1249.390 719.110 1249.645 ;
        RECT 719.930 1249.390 721.030 1249.645 ;
        RECT 721.850 1249.390 722.950 1249.645 ;
        RECT 723.770 1249.390 724.870 1249.645 ;
        RECT 725.690 1249.390 726.790 1249.645 ;
        RECT 727.610 1249.390 728.710 1249.645 ;
        RECT 729.530 1249.390 730.630 1249.645 ;
        RECT 731.450 1249.390 732.550 1249.645 ;
        RECT 733.370 1249.390 734.470 1249.645 ;
        RECT 735.290 1249.390 736.390 1249.645 ;
        RECT 737.210 1249.390 738.310 1249.645 ;
        RECT 739.130 1249.390 740.230 1249.645 ;
        RECT 741.050 1249.390 742.150 1249.645 ;
        RECT 742.970 1249.390 744.070 1249.645 ;
        RECT 744.890 1249.390 745.990 1249.645 ;
        RECT 746.810 1249.390 747.910 1249.645 ;
        RECT 748.730 1249.390 749.830 1249.645 ;
        RECT 750.650 1249.390 751.750 1249.645 ;
        RECT 752.570 1249.390 753.670 1249.645 ;
        RECT 754.490 1249.390 755.590 1249.645 ;
        RECT 756.410 1249.390 757.510 1249.645 ;
        RECT 758.330 1249.390 759.430 1249.645 ;
        RECT 760.250 1249.390 761.350 1249.645 ;
        RECT 762.170 1249.390 763.270 1249.645 ;
        RECT 764.090 1249.390 765.190 1249.645 ;
        RECT 766.010 1249.390 767.110 1249.645 ;
        RECT 767.930 1249.390 769.030 1249.645 ;
        RECT 769.850 1249.390 770.950 1249.645 ;
        RECT 771.770 1249.390 772.870 1249.645 ;
        RECT 773.690 1249.390 774.790 1249.645 ;
        RECT 775.610 1249.390 776.710 1249.645 ;
        RECT 777.530 1249.390 778.630 1249.645 ;
        RECT 779.450 1249.390 780.550 1249.645 ;
        RECT 781.370 1249.390 782.470 1249.645 ;
        RECT 783.290 1249.390 784.390 1249.645 ;
        RECT 785.210 1249.390 786.310 1249.645 ;
        RECT 787.130 1249.390 788.230 1249.645 ;
        RECT 789.050 1249.390 790.150 1249.645 ;
        RECT 790.970 1249.390 792.070 1249.645 ;
        RECT 792.890 1249.390 793.990 1249.645 ;
        RECT 794.810 1249.390 795.910 1249.645 ;
        RECT 796.730 1249.390 797.830 1249.645 ;
        RECT 798.650 1249.390 799.750 1249.645 ;
        RECT 800.570 1249.390 801.670 1249.645 ;
        RECT 802.490 1249.390 803.590 1249.645 ;
        RECT 804.410 1249.390 805.510 1249.645 ;
        RECT 806.330 1249.390 807.430 1249.645 ;
        RECT 808.250 1249.390 809.350 1249.645 ;
        RECT 810.170 1249.390 811.270 1249.645 ;
        RECT 812.090 1249.390 813.190 1249.645 ;
        RECT 814.010 1249.390 815.110 1249.645 ;
        RECT 815.930 1249.390 817.030 1249.645 ;
        RECT 817.850 1249.390 818.950 1249.645 ;
        RECT 819.770 1249.390 820.870 1249.645 ;
        RECT 821.690 1249.390 822.790 1249.645 ;
        RECT 823.610 1249.390 824.710 1249.645 ;
        RECT 825.530 1249.390 826.630 1249.645 ;
        RECT 827.450 1249.390 828.550 1249.645 ;
        RECT 829.370 1249.390 830.470 1249.645 ;
        RECT 831.290 1249.390 832.390 1249.645 ;
        RECT 833.210 1249.390 834.310 1249.645 ;
        RECT 835.130 1249.390 836.230 1249.645 ;
        RECT 837.050 1249.390 838.150 1249.645 ;
        RECT 838.970 1249.390 840.070 1249.645 ;
        RECT 840.890 1249.390 841.990 1249.645 ;
        RECT 842.810 1249.390 843.910 1249.645 ;
        RECT 844.730 1249.390 845.830 1249.645 ;
        RECT 846.650 1249.390 847.750 1249.645 ;
        RECT 848.570 1249.390 849.670 1249.645 ;
        RECT 850.490 1249.390 851.590 1249.645 ;
        RECT 852.410 1249.390 853.510 1249.645 ;
        RECT 854.330 1249.390 855.430 1249.645 ;
        RECT 856.250 1249.390 857.350 1249.645 ;
        RECT 858.170 1249.390 859.270 1249.645 ;
        RECT 860.090 1249.390 861.190 1249.645 ;
        RECT 862.010 1249.390 863.110 1249.645 ;
        RECT 863.930 1249.390 865.030 1249.645 ;
        RECT 865.850 1249.390 866.950 1249.645 ;
        RECT 867.770 1249.390 868.870 1249.645 ;
        RECT 869.690 1249.390 870.790 1249.645 ;
        RECT 871.610 1249.390 872.710 1249.645 ;
        RECT 873.530 1249.390 874.630 1249.645 ;
        RECT 875.450 1249.390 876.550 1249.645 ;
        RECT 877.370 1249.390 878.470 1249.645 ;
        RECT 879.290 1249.390 880.390 1249.645 ;
        RECT 881.210 1249.390 882.310 1249.645 ;
        RECT 883.130 1249.390 884.230 1249.645 ;
        RECT 885.050 1249.390 886.150 1249.645 ;
        RECT 886.970 1249.390 888.070 1249.645 ;
        RECT 888.890 1249.390 889.990 1249.645 ;
        RECT 890.810 1249.390 891.910 1249.645 ;
        RECT 892.730 1249.390 893.830 1249.645 ;
        RECT 894.650 1249.390 895.750 1249.645 ;
        RECT 896.570 1249.390 897.670 1249.645 ;
        RECT 898.490 1249.390 899.590 1249.645 ;
        RECT 900.410 1249.390 901.510 1249.645 ;
        RECT 902.330 1249.390 903.430 1249.645 ;
        RECT 904.250 1249.390 905.350 1249.645 ;
        RECT 906.170 1249.390 907.270 1249.645 ;
        RECT 908.090 1249.390 909.190 1249.645 ;
        RECT 910.010 1249.390 911.110 1249.645 ;
        RECT 911.930 1249.390 913.030 1249.645 ;
        RECT 913.850 1249.390 914.950 1249.645 ;
        RECT 915.770 1249.390 916.870 1249.645 ;
        RECT 917.690 1249.390 918.790 1249.645 ;
        RECT 919.610 1249.390 920.710 1249.645 ;
        RECT 921.530 1249.390 922.630 1249.645 ;
        RECT 923.450 1249.390 924.550 1249.645 ;
        RECT 925.370 1249.390 926.470 1249.645 ;
        RECT 927.290 1249.390 928.390 1249.645 ;
        RECT 929.210 1249.390 930.310 1249.645 ;
        RECT 931.130 1249.390 932.230 1249.645 ;
        RECT 933.050 1249.390 934.150 1249.645 ;
        RECT 934.970 1249.390 936.070 1249.645 ;
        RECT 936.890 1249.390 937.990 1249.645 ;
        RECT 938.810 1249.390 939.910 1249.645 ;
        RECT 940.730 1249.390 941.830 1249.645 ;
        RECT 942.650 1249.390 943.750 1249.645 ;
        RECT 944.570 1249.390 945.670 1249.645 ;
        RECT 946.490 1249.390 947.590 1249.645 ;
        RECT 948.410 1249.390 949.510 1249.645 ;
        RECT 950.330 1249.390 951.430 1249.645 ;
        RECT 952.250 1249.390 953.350 1249.645 ;
        RECT 954.170 1249.390 955.270 1249.645 ;
        RECT 956.090 1249.390 957.190 1249.645 ;
        RECT 958.010 1249.390 959.110 1249.645 ;
        RECT 959.930 1249.390 961.030 1249.645 ;
        RECT 961.850 1249.390 962.950 1249.645 ;
        RECT 963.770 1249.390 964.870 1249.645 ;
        RECT 965.690 1249.390 966.790 1249.645 ;
        RECT 967.610 1249.390 968.710 1249.645 ;
        RECT 969.530 1249.390 970.630 1249.645 ;
        RECT 971.450 1249.390 972.550 1249.645 ;
        RECT 973.370 1249.390 974.470 1249.645 ;
        RECT 975.290 1249.390 976.390 1249.645 ;
        RECT 977.210 1249.390 978.310 1249.645 ;
        RECT 979.130 1249.390 980.230 1249.645 ;
        RECT 981.050 1249.390 982.150 1249.645 ;
        RECT 982.970 1249.390 984.070 1249.645 ;
        RECT 984.890 1249.390 985.990 1249.645 ;
        RECT 986.810 1249.390 987.910 1249.645 ;
        RECT 988.730 1249.390 989.830 1249.645 ;
        RECT 990.650 1249.390 991.750 1249.645 ;
        RECT 992.570 1249.390 993.670 1249.645 ;
        RECT 994.490 1249.390 995.590 1249.645 ;
        RECT 996.410 1249.390 997.510 1249.645 ;
        RECT 998.330 1249.390 999.430 1249.645 ;
        RECT 1000.250 1249.390 1001.350 1249.645 ;
        RECT 1002.170 1249.390 1003.270 1249.645 ;
        RECT 1004.090 1249.390 1005.190 1249.645 ;
        RECT 1006.010 1249.390 1007.110 1249.645 ;
        RECT 1007.930 1249.390 1009.030 1249.645 ;
        RECT 1009.850 1249.390 1010.950 1249.645 ;
        RECT 1011.770 1249.390 1012.870 1249.645 ;
        RECT 1013.690 1249.390 1014.790 1249.645 ;
        RECT 1015.610 1249.390 1016.710 1249.645 ;
        RECT 1017.530 1249.390 1018.630 1249.645 ;
        RECT 1019.450 1249.390 1020.550 1249.645 ;
        RECT 1021.370 1249.390 1022.470 1249.645 ;
        RECT 1023.290 1249.390 1024.390 1249.645 ;
        RECT 1025.210 1249.390 1026.310 1249.645 ;
        RECT 1027.130 1249.390 1028.230 1249.645 ;
        RECT 1029.050 1249.390 1030.150 1249.645 ;
        RECT 1030.970 1249.390 1032.070 1249.645 ;
        RECT 1032.890 1249.390 1033.990 1249.645 ;
        RECT 1034.810 1249.390 1035.910 1249.645 ;
        RECT 1036.730 1249.390 1037.830 1249.645 ;
        RECT 1038.650 1249.390 1039.750 1249.645 ;
        RECT 1040.570 1249.390 1041.670 1249.645 ;
        RECT 1042.490 1249.390 1043.590 1249.645 ;
        RECT 1044.410 1249.390 1045.510 1249.645 ;
        RECT 1046.330 1249.390 1047.430 1249.645 ;
        RECT 1048.250 1249.390 1049.350 1249.645 ;
        RECT 1050.170 1249.390 1051.270 1249.645 ;
        RECT 1052.090 1249.390 1053.190 1249.645 ;
        RECT 1054.010 1249.390 1055.110 1249.645 ;
        RECT 1055.930 1249.390 1057.030 1249.645 ;
        RECT 1057.850 1249.390 1058.950 1249.645 ;
        RECT 1059.770 1249.390 1060.870 1249.645 ;
        RECT 1061.690 1249.390 1062.790 1249.645 ;
        RECT 1063.610 1249.390 1064.710 1249.645 ;
        RECT 1065.530 1249.390 1066.630 1249.645 ;
        RECT 1067.450 1249.390 1068.550 1249.645 ;
        RECT 1069.370 1249.390 1070.470 1249.645 ;
        RECT 1071.290 1249.390 1072.390 1249.645 ;
        RECT 1073.210 1249.390 1074.310 1249.645 ;
        RECT 1075.130 1249.390 1076.230 1249.645 ;
        RECT 1077.050 1249.390 1078.150 1249.645 ;
        RECT 1078.970 1249.390 1080.070 1249.645 ;
        RECT 1080.890 1249.390 1081.990 1249.645 ;
        RECT 1082.810 1249.390 1083.910 1249.645 ;
        RECT 1084.730 1249.390 1085.830 1249.645 ;
        RECT 1086.650 1249.390 1087.750 1249.645 ;
        RECT 1088.570 1249.390 1089.670 1249.645 ;
        RECT 1090.490 1249.390 1091.590 1249.645 ;
        RECT 1092.410 1249.390 1093.510 1249.645 ;
        RECT 1094.330 1249.390 1095.430 1249.645 ;
        RECT 1096.250 1249.390 1097.350 1249.645 ;
        RECT 1098.170 1249.390 1099.270 1249.645 ;
        RECT 1100.090 1249.390 1101.190 1249.645 ;
        RECT 1102.010 1249.390 1103.110 1249.645 ;
        RECT 1103.930 1249.390 1105.030 1249.645 ;
        RECT 1105.850 1249.390 1106.950 1249.645 ;
        RECT 1107.770 1249.390 1108.870 1249.645 ;
        RECT 1109.690 1249.390 1110.790 1249.645 ;
        RECT 1111.610 1249.390 1112.710 1249.645 ;
        RECT 1113.530 1249.390 1114.630 1249.645 ;
        RECT 1115.450 1249.390 1116.550 1249.645 ;
        RECT 1117.370 1249.390 1118.470 1249.645 ;
        RECT 1119.290 1249.390 1120.390 1249.645 ;
        RECT 1121.210 1249.390 1122.310 1249.645 ;
        RECT 1123.130 1249.390 1124.230 1249.645 ;
        RECT 1125.050 1249.390 1126.150 1249.645 ;
        RECT 1126.970 1249.390 1128.070 1249.645 ;
        RECT 1128.890 1249.390 1129.990 1249.645 ;
        RECT 1130.810 1249.390 1131.910 1249.645 ;
        RECT 1132.730 1249.390 1133.830 1249.645 ;
        RECT 1134.650 1249.390 1135.750 1249.645 ;
        RECT 1136.570 1249.390 1137.670 1249.645 ;
        RECT 1138.490 1249.390 1139.590 1249.645 ;
        RECT 1140.410 1249.390 1141.510 1249.645 ;
        RECT 1142.330 1249.390 1143.430 1249.645 ;
        RECT 1144.250 1249.390 1145.350 1249.645 ;
        RECT 1146.170 1249.390 1147.270 1249.645 ;
        RECT 1148.090 1249.390 1149.190 1249.645 ;
        RECT 1150.010 1249.390 1151.110 1249.645 ;
        RECT 1151.930 1249.390 1153.030 1249.645 ;
        RECT 1153.850 1249.390 1154.950 1249.645 ;
        RECT 1155.770 1249.390 1156.870 1249.645 ;
        RECT 1157.690 1249.390 1158.790 1249.645 ;
        RECT 1159.610 1249.390 1160.710 1249.645 ;
        RECT 1161.530 1249.390 1162.630 1249.645 ;
        RECT 1163.450 1249.390 1164.550 1249.645 ;
        RECT 1165.370 1249.390 1166.470 1249.645 ;
        RECT 1167.290 1249.390 1168.390 1249.645 ;
        RECT 1169.210 1249.390 1170.310 1249.645 ;
        RECT 1171.130 1249.390 1172.230 1249.645 ;
        RECT 1173.050 1249.390 1174.150 1249.645 ;
        RECT 1174.970 1249.390 1176.070 1249.645 ;
        RECT 1176.890 1249.390 1243.785 1249.645 ;
        RECT 1.335 14.975 1243.785 1249.390 ;
      LAYER Metal3 ;
        RECT 0.400 1233.950 1243.825 1249.600 ;
        RECT 0.610 1233.130 1243.825 1233.950 ;
        RECT 0.400 1216.310 1243.825 1233.130 ;
        RECT 0.610 1215.490 1243.825 1216.310 ;
        RECT 0.400 1198.670 1243.825 1215.490 ;
        RECT 0.610 1197.850 1243.825 1198.670 ;
        RECT 0.400 1181.030 1243.825 1197.850 ;
        RECT 0.610 1180.210 1243.825 1181.030 ;
        RECT 0.400 1163.390 1243.825 1180.210 ;
        RECT 0.610 1162.570 1243.825 1163.390 ;
        RECT 0.400 1145.750 1243.825 1162.570 ;
        RECT 0.610 1144.930 1243.825 1145.750 ;
        RECT 0.400 1128.110 1243.825 1144.930 ;
        RECT 0.610 1127.290 1243.825 1128.110 ;
        RECT 0.400 1110.470 1243.825 1127.290 ;
        RECT 0.610 1109.650 1243.825 1110.470 ;
        RECT 0.400 1092.830 1243.825 1109.650 ;
        RECT 0.610 1092.010 1243.825 1092.830 ;
        RECT 0.400 1075.190 1243.825 1092.010 ;
        RECT 0.610 1074.370 1243.825 1075.190 ;
        RECT 0.400 1057.550 1243.825 1074.370 ;
        RECT 0.610 1056.730 1243.825 1057.550 ;
        RECT 0.400 1039.910 1243.825 1056.730 ;
        RECT 0.610 1039.090 1243.825 1039.910 ;
        RECT 0.400 1022.270 1243.825 1039.090 ;
        RECT 0.610 1021.450 1243.825 1022.270 ;
        RECT 0.400 1004.630 1243.825 1021.450 ;
        RECT 0.610 1003.810 1243.825 1004.630 ;
        RECT 0.400 986.990 1243.825 1003.810 ;
        RECT 0.610 986.170 1243.825 986.990 ;
        RECT 0.400 969.350 1243.825 986.170 ;
        RECT 0.610 968.530 1243.825 969.350 ;
        RECT 0.400 951.710 1243.825 968.530 ;
        RECT 0.610 950.890 1243.825 951.710 ;
        RECT 0.400 934.070 1243.825 950.890 ;
        RECT 0.610 933.250 1243.825 934.070 ;
        RECT 0.400 916.430 1243.825 933.250 ;
        RECT 0.610 915.610 1243.825 916.430 ;
        RECT 0.400 898.790 1243.825 915.610 ;
        RECT 0.610 897.970 1243.825 898.790 ;
        RECT 0.400 881.150 1243.825 897.970 ;
        RECT 0.610 880.330 1243.825 881.150 ;
        RECT 0.400 863.510 1243.825 880.330 ;
        RECT 0.610 862.690 1243.825 863.510 ;
        RECT 0.400 845.870 1243.825 862.690 ;
        RECT 0.610 845.050 1243.825 845.870 ;
        RECT 0.400 828.230 1243.825 845.050 ;
        RECT 0.610 827.410 1243.825 828.230 ;
        RECT 0.400 810.590 1243.825 827.410 ;
        RECT 0.610 809.770 1243.825 810.590 ;
        RECT 0.400 792.950 1243.825 809.770 ;
        RECT 0.610 792.130 1243.825 792.950 ;
        RECT 0.400 775.310 1243.825 792.130 ;
        RECT 0.610 774.490 1243.825 775.310 ;
        RECT 0.400 757.670 1243.825 774.490 ;
        RECT 0.610 756.850 1243.825 757.670 ;
        RECT 0.400 740.030 1243.825 756.850 ;
        RECT 0.610 739.210 1243.825 740.030 ;
        RECT 0.400 722.390 1243.825 739.210 ;
        RECT 0.610 721.570 1243.825 722.390 ;
        RECT 0.400 704.750 1243.825 721.570 ;
        RECT 0.610 703.930 1243.825 704.750 ;
        RECT 0.400 687.110 1243.825 703.930 ;
        RECT 0.610 686.290 1243.825 687.110 ;
        RECT 0.400 669.470 1243.825 686.290 ;
        RECT 0.610 668.650 1243.825 669.470 ;
        RECT 0.400 651.830 1243.825 668.650 ;
        RECT 0.610 651.010 1243.825 651.830 ;
        RECT 0.400 634.190 1243.825 651.010 ;
        RECT 0.610 633.370 1243.825 634.190 ;
        RECT 0.400 616.550 1243.825 633.370 ;
        RECT 0.610 615.730 1243.825 616.550 ;
        RECT 0.400 598.910 1243.825 615.730 ;
        RECT 0.610 598.090 1243.825 598.910 ;
        RECT 0.400 581.270 1243.825 598.090 ;
        RECT 0.610 580.450 1243.825 581.270 ;
        RECT 0.400 563.630 1243.825 580.450 ;
        RECT 0.610 562.810 1243.825 563.630 ;
        RECT 0.400 545.990 1243.825 562.810 ;
        RECT 0.610 545.170 1243.825 545.990 ;
        RECT 0.400 528.350 1243.825 545.170 ;
        RECT 0.610 527.530 1243.825 528.350 ;
        RECT 0.400 510.710 1243.825 527.530 ;
        RECT 0.610 509.890 1243.825 510.710 ;
        RECT 0.400 493.070 1243.825 509.890 ;
        RECT 0.610 492.250 1243.825 493.070 ;
        RECT 0.400 475.430 1243.825 492.250 ;
        RECT 0.610 474.610 1243.825 475.430 ;
        RECT 0.400 457.790 1243.825 474.610 ;
        RECT 0.610 456.970 1243.825 457.790 ;
        RECT 0.400 440.150 1243.825 456.970 ;
        RECT 0.610 439.330 1243.825 440.150 ;
        RECT 0.400 422.510 1243.825 439.330 ;
        RECT 0.610 421.690 1243.825 422.510 ;
        RECT 0.400 404.870 1243.825 421.690 ;
        RECT 0.610 404.050 1243.825 404.870 ;
        RECT 0.400 387.230 1243.825 404.050 ;
        RECT 0.610 386.410 1243.825 387.230 ;
        RECT 0.400 369.590 1243.825 386.410 ;
        RECT 0.610 368.770 1243.825 369.590 ;
        RECT 0.400 351.950 1243.825 368.770 ;
        RECT 0.610 351.130 1243.825 351.950 ;
        RECT 0.400 334.310 1243.825 351.130 ;
        RECT 0.610 333.490 1243.825 334.310 ;
        RECT 0.400 316.670 1243.825 333.490 ;
        RECT 0.610 315.850 1243.825 316.670 ;
        RECT 0.400 299.030 1243.825 315.850 ;
        RECT 0.610 298.210 1243.825 299.030 ;
        RECT 0.400 281.390 1243.825 298.210 ;
        RECT 0.610 280.570 1243.825 281.390 ;
        RECT 0.400 263.750 1243.825 280.570 ;
        RECT 0.610 262.930 1243.825 263.750 ;
        RECT 0.400 246.110 1243.825 262.930 ;
        RECT 0.610 245.290 1243.825 246.110 ;
        RECT 0.400 228.470 1243.825 245.290 ;
        RECT 0.610 227.650 1243.825 228.470 ;
        RECT 0.400 210.830 1243.825 227.650 ;
        RECT 0.610 210.010 1243.825 210.830 ;
        RECT 0.400 193.190 1243.825 210.010 ;
        RECT 0.610 192.370 1243.825 193.190 ;
        RECT 0.400 175.550 1243.825 192.370 ;
        RECT 0.610 174.730 1243.825 175.550 ;
        RECT 0.400 157.910 1243.825 174.730 ;
        RECT 0.610 157.090 1243.825 157.910 ;
        RECT 0.400 140.270 1243.825 157.090 ;
        RECT 0.610 139.450 1243.825 140.270 ;
        RECT 0.400 122.630 1243.825 139.450 ;
        RECT 0.610 121.810 1243.825 122.630 ;
        RECT 0.400 104.990 1243.825 121.810 ;
        RECT 0.610 104.170 1243.825 104.990 ;
        RECT 0.400 87.350 1243.825 104.170 ;
        RECT 0.610 86.530 1243.825 87.350 ;
        RECT 0.400 69.710 1243.825 86.530 ;
        RECT 0.610 68.890 1243.825 69.710 ;
        RECT 0.400 52.070 1243.825 68.890 ;
        RECT 0.610 51.250 1243.825 52.070 ;
        RECT 0.400 34.430 1243.825 51.250 ;
        RECT 0.610 33.610 1243.825 34.430 ;
        RECT 0.400 16.790 1243.825 33.610 ;
        RECT 0.610 15.970 1243.825 16.790 ;
        RECT 0.400 15.020 1243.825 15.970 ;
      LAYER Metal4 ;
        RECT 6.140 1232.710 1238.020 1234.525 ;
        RECT 6.140 55.715 15.050 1232.710 ;
        RECT 16.470 55.715 18.050 1232.710 ;
        RECT 19.470 55.715 65.050 1232.710 ;
        RECT 66.470 55.715 68.050 1232.710 ;
        RECT 69.470 55.715 115.050 1232.710 ;
        RECT 116.470 55.715 118.050 1232.710 ;
        RECT 119.470 55.715 165.050 1232.710 ;
        RECT 166.470 55.715 168.050 1232.710 ;
        RECT 169.470 55.715 215.050 1232.710 ;
        RECT 216.470 55.715 218.050 1232.710 ;
        RECT 219.470 55.715 265.050 1232.710 ;
        RECT 266.470 55.715 268.050 1232.710 ;
        RECT 269.470 55.715 315.050 1232.710 ;
        RECT 316.470 55.715 318.050 1232.710 ;
        RECT 319.470 55.715 365.050 1232.710 ;
        RECT 366.470 55.715 368.050 1232.710 ;
        RECT 369.470 55.715 415.050 1232.710 ;
        RECT 416.470 55.715 418.050 1232.710 ;
        RECT 419.470 55.715 465.050 1232.710 ;
        RECT 466.470 55.715 468.050 1232.710 ;
        RECT 469.470 55.715 515.050 1232.710 ;
        RECT 516.470 55.715 518.050 1232.710 ;
        RECT 519.470 55.715 565.050 1232.710 ;
        RECT 566.470 55.715 568.050 1232.710 ;
        RECT 569.470 55.715 615.050 1232.710 ;
        RECT 616.470 55.715 618.050 1232.710 ;
        RECT 619.470 55.715 665.050 1232.710 ;
        RECT 666.470 55.715 668.050 1232.710 ;
        RECT 669.470 55.715 715.050 1232.710 ;
        RECT 716.470 55.715 718.050 1232.710 ;
        RECT 719.470 55.715 765.050 1232.710 ;
        RECT 766.470 55.715 768.050 1232.710 ;
        RECT 769.470 55.715 815.050 1232.710 ;
        RECT 816.470 55.715 818.050 1232.710 ;
        RECT 819.470 55.715 865.050 1232.710 ;
        RECT 866.470 55.715 868.050 1232.710 ;
        RECT 869.470 55.715 915.050 1232.710 ;
        RECT 916.470 55.715 918.050 1232.710 ;
        RECT 919.470 55.715 965.050 1232.710 ;
        RECT 966.470 55.715 968.050 1232.710 ;
        RECT 969.470 55.715 1015.050 1232.710 ;
        RECT 1016.470 55.715 1018.050 1232.710 ;
        RECT 1019.470 55.715 1065.050 1232.710 ;
        RECT 1066.470 55.715 1068.050 1232.710 ;
        RECT 1069.470 55.715 1115.050 1232.710 ;
        RECT 1116.470 55.715 1118.050 1232.710 ;
        RECT 1119.470 55.715 1165.050 1232.710 ;
        RECT 1166.470 55.715 1168.050 1232.710 ;
        RECT 1169.470 55.715 1215.050 1232.710 ;
        RECT 1216.470 55.715 1218.050 1232.710 ;
        RECT 1219.470 55.715 1238.020 1232.710 ;
      LAYER TopMetal1 ;
        RECT 31.340 278.980 1074.580 1229.100 ;
  END
END systolic_array
END LIBRARY

